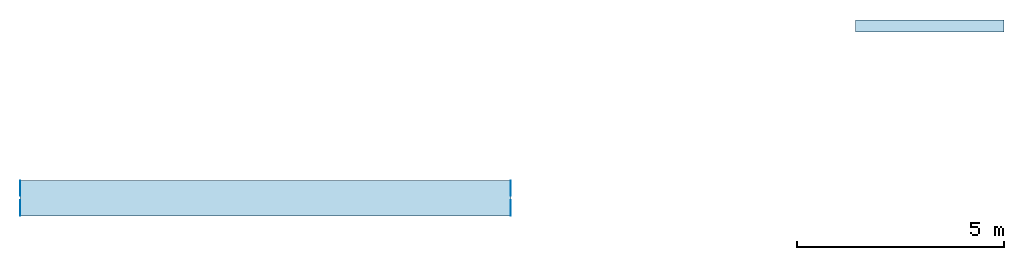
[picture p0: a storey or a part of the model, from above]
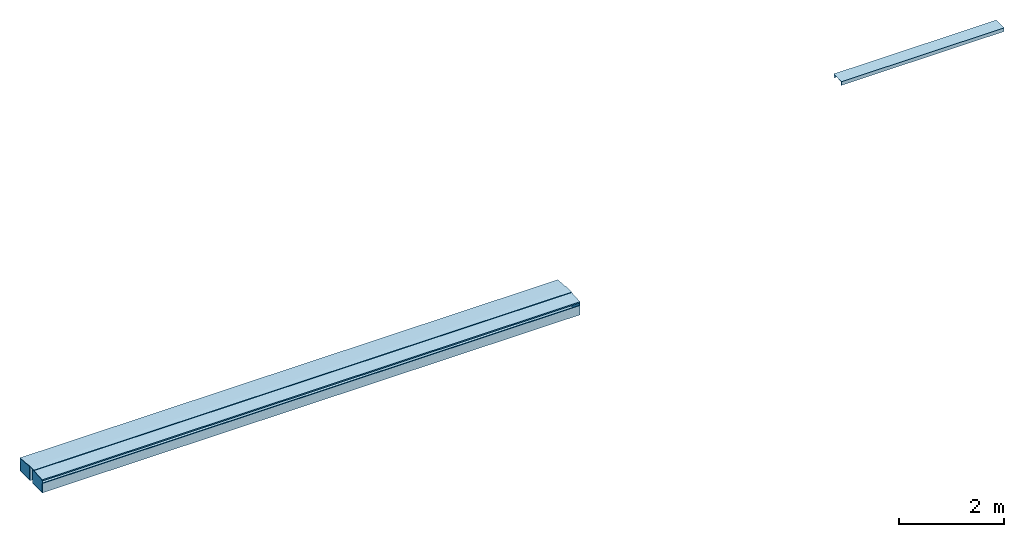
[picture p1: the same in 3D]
Properties of the parts of a building model (IFC2X3), part 1 of 5

# File
Description: ViewDefinition [CoordinationView_V2.0]
File name: ind. 00
Time: 2021-08-19T08:42:44
Written by: The EXPRESS Data Manager Version 5.02.0100.07 : 28 Aug 2013
Made in: 20180216_1515(x64) - Exporter 19.0.0.405 - Interface utilisateur alternative 19.0.0.405
Comment: STEP Physical File produced by: The EXPRESS Data Manager Version 5.02.0100.07 : 28 Aug 2013 * Module: EDMstepFileFactory/EDMstandAlone * Creation date: Thu Aug 19 08:42:44 2021 * Host: djaffar * Database: C:\Users\djaffar\AppData\Local\Temp\{09F7AAD4-CD3B-48EF-BE17-3F017BB1FF19}\ifc * Database version: 5507 * Database creation date: Thu Aug 19 08:42:33 2021 * Schema: IFC2X3 * Model: DataRepository.ifc * Model creation date: Thu Aug 19 08:42:33 2021 * Header model: DataRepository.ifc_HeaderModel * Header model creation date: Thu Aug 19 08:42:33 2021 * EDMuser: sdai-user * EDMgroup: sdai-group * License ID and type: 5605 : Permanent license. Expiry date: * EDMstepFileFactory options: 020000

# IfcProject, ind. 00
LongName: Extension de la préfecture de Mayotte; Phase: DCE

# IfcSite, Surface:959592
RefLatitude: -12, -46, -34, -218063; RefLongitude: 45, 13, 48, 547668; RefElevation: 0 m
Autre - Catégorie: Topographie; Déblais: 0 m3; Déblais/remblais net: 0 m3; Remblais: 0 m3
Cotes - Surface: 0.0941983 m2; Surface projetée: 0.0941764 m2
Données d'identification - Sous-projet: Sous-projet 1; Variantes: Terrain : projet
Matériaux et finitions - Matériau: AA-Herbe
Phase de construction - Phase de création: Nouvelle construction

# IfcBuilding, ExPREF
LongName: ExPREF
Pset_BuildingCommon - NumberOfStoreys: 6
Autre - Adresse du projet: BP 676 - Kawéni, Mamoudzou, Mayotte; Catégorie: Informations sur le projet; Date de fin du projet: Aout. 2021; Etat du projet: DCE; Nom du client: Préfecture de Mayotte; Nom du projet: Extension de la préfecture de Mayotte; Numéro de projet: ind. 00
Données d'identification - Auteur: hugo; Nom de l'organisation: Préfecture de Mayotte; Nom du bâtiment: ExPREF; Sous-projet: Infos sur le projet

# IfcBuildingStorey (6)
In: ExPREF
Autre - Catégorie: Niveaux; Famille: Niveau: Ligne du Niveau; Famille et type: Niveau: Ligne du Niveau; ID du type: Niveau: Ligne du Niveau; Type: Niveau: Ligne du Niveau
Cotes - Hauteur de calcul: 0 m
Données d'identification - Structure: no; Etage de bâtiment: yes; Sous-projet: Niveaux et quadrillages partagés
Autre(Type) - Catégorie: Niveaux; Nom de la famille: Niveau
Contraintes(Type) - Base de l'élévation: Point de base du projet
Données d'identification(Type) - Nom du type: Ligne du Niveau; Sous-projet: Types de niveaux
Graphismes(Type) - Couleur: 0; Epaisseur des lignes: 1; Motif des lignes: Plein; Symbole: Marqueur de niveau élévation 200ieme: Marqueur de niveau élévation 200ieme; Valeur par défaut du symbole à l'extrémité 1: no; Valeur par défaut du symbole à l'extrémité 2: yes
Name | LongName = Nom | Elevation (m) | Elévation (m)
R-1 | R-1 | -4.62 | -4.62 | Données d'identification - Variantes: Modèle de base
RDC | RDC | -6.89719e-12 | 0 | Données d'identification - Variantes: Modèle de base
R+1 | R+1 | 4.27 | 4.27 | Données d'identification - Variantes: Modèle de base
R+2 | R+2 | 7.83 | 7.83
Toiture | Toiture | 11.05 | 11.05
Couverture | Couverture | 13 | 13

# IfcBeam: Poutre - Bois de construction de dimensions courantes:A-24x10 cm (8)
In: R+2
Type - PredefinedType: BEAM
Type - Autre - Catégorie: Ossature; Nom de la famille: Poutre - Bois de construction de dimensions courantes
Type - Cotes - b: 0.24 m; d: 0.1 m
Type - Données d'identification - Nom du type: A-24x10 cm; Sous-projet: Famille : Ossature : Poutre - Bois de construction de dimensions courantes
Type - Structure - A: 0.002419 m2; Forme de coupe: 0
Material: AA-bois poutres
Pset_BeamCommon - LoadBearing: yes; IsExternal: no; Slope: 0 deg; Reference: Poutre - Bois de construction de dimensions courantes:A-24x10 cm
Autre - Famille: Poutre - Bois de construction de dimensions courantes: A-24x10 cm; Famille et type: Poutre - Bois de construction de dimensions courantes: A-24x10 cm; ID du type: Poutre - Bois de construction de dimensions courantes: A-24x10 cm; Type: Poutre - Bois de construction de dimensions courantes: A-24x10 cm
Contraintes - Décalage du niveau d'arrivée: 0.1 m; Décalage du niveau de départ: 0.1 m; Elévation du niveau de référence: 7.83 m; Niveau de référence: Niveau: R+2; Rotation de la section: 0 deg
Cotes - Elévation à la base: 7.83 m; Elévation en haut: 7.93 m; Volume: 0.0168 m3
Données d'identification - Sous-projet: BTC
Matériaux et finitions - Matériau structurel: AA-bois poutres
Phase de construction - Phase de création: Nouvelle construction
Position géométrique - Etat de la jonction: Deux jonctions activées; Extension de départ: 0.00268381 m; Extension de fin: -0.021 m; Justification Y: Origine; Justification YZ: Uniforme; Justification Z: Haut; Valeur de décalage Y: 0 m; Valeur de décalage Z: 0 m
Structure - Activer le modèle analytique: yes; Emplacement du symbole filaire: Centre de la géométrie; Longueur de coupe: 0.7 m; Type d'attachement de début: Elévation d'arrivée; Type d'attachement de fin: Elévation d'arrivée; Utilisation structurelle: Autre
Name (Poutre - Bois de construction de dimensions courantes:A-24x10 cm:...) | Longueur (m) | Réduction du joint de début (m) | Réduction du joint d'extrémité (m) | Group
2029215 | 0.679 | 0.000505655 | 0.000494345 | Groupe de modèles:mur BTC R+2:2029197
2029217 | 0.697 | 0 | -0.001 | Groupe de modèles:mur BTC R+2:2029197 | Données d'identification - Variantes: Modèle de base
2029649 | 0.679 | 0.000505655 | 0.000494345 | Groupe de modèles:mur BTC R+2:2029648
2029651 | 0.697 | 0 | -0.001 | Groupe de modèles:mur BTC R+2:2029648
2029723 | 0.679 | 0.000505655 | 0.000494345 | Groupe de modèles:mur BTC R+2:2029722
2029725 | 0.697 | 0 | -0.001 | Groupe de modèles:mur BTC R+2:2029722
2029801 | 0.679 | 0.000505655 | 0.000494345 | Groupe de modèles:mur BTC R+2:2029800 | Données d'identification - Variantes: Modèle de base
2029803 | 0.697 | 0 | -0.001 | Groupe de modèles:mur BTC R+2:2029800 | Données d'identification - Variantes: Modèle de base

# IfcBuildingElementProxy: R+2 naco + fenetre (3)
In: R+1
Type - Material: AA-Aluminium, AA-vitrage, AA-bois menuiseries
Type - Autre - Catégorie: Modèles génériques; Nom de la famille: R+1 naco + fenetre
Type - Cotes - hauteur: 3.81 m
Type - Données d'identification - Nom du type: R+2 naco + fenetre; Sous-projet: Famille : Modèles génériques : R+1 naco + fenetre
Type - Matériaux et finitions - matériau: AA-bois menuiseries; VITRAGE: AA-vitrage
Pset_BuildingElementProxyCommon - Reference: R+1 naco + fenetre:R+2 naco + fenetre
Autre - Famille: R+1 naco + fenetre: R+2 naco + fenetre; Famille et type: R+1 naco + fenetre: R+2 naco + fenetre; ID du type: R+1 naco + fenetre: R+2 naco + fenetre; Type: R+1 naco + fenetre: R+2 naco + fenetre
Contraintes - Niveau: Niveau: R+1; Décalage: 0 m; Se déplace avec les éléments voisins: no; Hôte: Niveau : R+1
Cotes - Surface: 9.87923 m2; Volume: 0.297217 m3
Données d'identification - Sous-projet: Menuiseries EXT
Phase de construction - Phase de création: Nouvelle construction
Name (R+1 naco + fenetre:R+2 naco + fenetre:...)
1082547 | Données d'identification - Variantes: Modèle de base
1082558
1082559

# IfcBuildingElementProxy: R+2 naco + naco (4)
In: R+2
Type - Material: AA-Aluminium, AA-vitrage, AA-bois menuiseries
Type - Autre - Catégorie: Modèles génériques; Nom de la famille: R+2 naco + naco
Type - Cotes - hauteur 2: 2.94 m
Type - Données d'identification - Nom du type: R+2 naco + naco; Sous-projet: Famille : Modèles génériques : R+2 naco + naco
Type - Matériaux et finitions - matériau: AA-bois menuiseries; VITRAGE: AA-vitrage
Pset_BuildingElementProxyCommon - Reference: R+2 naco + naco:R+2 naco + naco
Autre - Famille: R+2 naco + naco: R+2 naco + naco; Famille et type: R+2 naco + naco: R+2 naco + naco; ID du type: R+2 naco + naco: R+2 naco + naco; Type: R+2 naco + naco: R+2 naco + naco
Contraintes - Niveau: Niveau: R+2; Décalage: 0 m; Se déplace avec les éléments voisins: no; Hôte: Niveau : R+2
Cotes - Surface: 9.59008 m2; Volume: 0.274164 m3
Données d'identification - Sous-projet: Menuiseries EXT
Phase de construction - Phase de création: Nouvelle construction
Name (R+2 naco + naco:R+2 naco + naco:...) | Variantes
689299 | Modèle de base
690346
691358 | Modèle de base
1266362 | Modèle de base

# IfcBuildingElementProxy: R+2 porte + fenetre (18)
In: R+1
Type - Material: AA-Aluminium, AA-vitrage, AA-bois menuiseries
Type - Autre - Catégorie: Modèles génériques; Nom de la famille: R+1 porte + fenetre
Type - Cotes - hauteur: 3.81 m
Type - Données d'identification - Nom du type: R+2 porte + fenetre; Sous-projet: Famille : Modèles génériques : R+1 porte + fenetre
Type - Matériaux et finitions - matériau: AA-bois menuiseries; VITRAGE: AA-vitrage
Pset_BuildingElementProxyCommon - Reference: R+1 porte + fenetre:R+2 porte + fenetre
Autre - Famille: R+1 porte + fenetre: R+2 porte + fenetre; Famille et type: R+1 porte + fenetre: R+2 porte + fenetre; ID du type: R+1 porte + fenetre: R+2 porte + fenetre; Type: R+1 porte + fenetre: R+2 porte + fenetre
Contraintes - Niveau: Niveau: R+1; Décalage: 0 m; Se déplace avec les éléments voisins: no
Cotes - Surface: 9.82578 m2; Volume: 0.313711 m3
Données d'identification - Sous-projet: Menuiseries EXT
Phase de construction - Phase de création: Nouvelle construction
Name (R+1 porte + fenetre:R+2 porte + fenetre:...) | Hôte | Variantes
684139 | Niveau : R+1 | Modèle de base
686462 | Sol : A-sol souple
687418 | Niveau : R+1 | Modèle de base
687426 | Niveau : R+1 | Modèle de base
687459 | Sol : A-sol souple | Modèle de base
687583 | Niveau : R+1 | Modèle de base
687584 | Niveau : R+1
687585 | Niveau : R+1
687586 | Niveau : R+1
687587 | Sol : A-sol souple | Modèle de base
687623 | Sol : A-sol souple
687642 | Niveau : R+1
687659 | Niveau : R+1 | Modèle de base
687676 | Niveau : R+1 | Modèle de base
687716 | Sol : A-sol souple | Modèle de base
687720 | Niveau : R+1 | Modèle de base
687724 | Niveau : R+1 | Modèle de base
687728 | Niveau : R+1 | Modèle de base

# IfcBuildingElementProxy: R+2 porte + fenetre (5)
In: R+2
Type - Material: AA-Aluminium, AA-vitrage, AA-bois menuiseries
Type - Autre - Catégorie: Modèles génériques; Nom de la famille: R+2 porte + fenetre
Type - Cotes - hauteur: 3.81 m; hauteur 2: 2.94 m
Type - Données d'identification - Nom du type: R+2 porte + fenetre; Sous-projet: Famille : Modèles génériques : R+2 porte + fenetre
Type - Matériaux et finitions - matériau: AA-bois menuiseries; VITRAGE: AA-vitrage
Pset_BuildingElementProxyCommon - Reference: R+2 porte + fenetre:R+2 porte + fenetre
Autre - Famille: R+2 porte + fenetre: R+2 porte + fenetre; Famille et type: R+2 porte + fenetre: R+2 porte + fenetre; ID du type: R+2 porte + fenetre: R+2 porte + fenetre; Type: R+2 porte + fenetre: R+2 porte + fenetre
Contraintes - Niveau: Niveau: R+2; Décalage: 0 m; Se déplace avec les éléments voisins: no
Cotes - Surface: 9.43234 m2; Volume: 0.308301 m3
Données d'identification - Sous-projet: Menuiseries EXT
Phase de construction - Phase de création: Nouvelle construction
Name (R+2 porte + fenetre:R+2 porte + fenetre:...) | Hôte | Variantes
689121 | Niveau : R+2 | Modèle de base
689284 | Sol : A-sol souple | Modèle de base
691381 | Niveau : R+2 | Modèle de base
691417 | Niveau : R+2
691418 | Sol : A-sol souple | Modèle de base

# IfcBuildingElementProxy: R+2 porte + fenetre préfet, R+2 porte + fenetre préfet:R+2 porte + fenetre préfet:1084761
In: R+2
Type - Material: AA-vitrage, AA-bois menuiseries
Type - Autre - Catégorie: Modèles génériques; Nom de la famille: R+2 porte + fenetre préfet
Type - Cotes - hauteur: 3.81 m
Type - Données d'identification - Nom du type: R+2 porte + fenetre préfet; Sous-projet: Famille : Modèles génériques : R+2 porte + fenetre préfet
Type - Matériaux et finitions - matériau: AA-bois menuiseries; VITRAGE: AA-vitrage
Pset_BuildingElementProxyCommon - Reference: R+2 porte + fenetre préfet:R+2 porte + fenetre préfet
Autre - Famille: R+2 porte + fenetre préfet: R+2 porte + fenetre préfet; Famille et type: R+2 porte + fenetre préfet: R+2 porte + fenetre préfet; ID du type: R+2 porte + fenetre préfet: R+2 porte + fenetre préfet; Type: R+2 porte + fenetre préfet: R+2 porte + fenetre préfet
Contraintes - Niveau: Niveau: R+2; Décalage: 0 m; Se déplace avec les éléments voisins: no; Hôte: Niveau : R+2
Cotes - Surface: 8.72555 m2; Volume: 0.419537 m3
Données d'identification - Sous-projet: Menuiseries EXT
Phase de construction - Phase de création: Nouvelle construction

# IfcBuildingElementProxy: R+2 porte + fenetre préfet symétrie, R+2 porte + fenetre préfet symétrie:R+2 porte + fenetre préfet symétrie:1084723
In: R+2
Type - Material: AA-vitrage, AA-bois menuiseries
Type - Autre - Catégorie: Modèles génériques; Nom de la famille: R+2 porte + fenetre préfet symétrie
Type - Cotes - hauteur: 3.81 m
Type - Données d'identification - Nom du type: R+2 porte + fenetre préfet symétrie; Sous-projet: Famille : Modèles génériques : R+2 porte + fenetre préfet symétrie
Type - Matériaux et finitions - matériau: AA-bois menuiseries; VITRAGE: AA-vitrage
Pset_BuildingElementProxyCommon - Reference: R+2 porte + fenetre préfet symétrie:R+2 porte + fenetre préfet symétrie
Autre - Famille: R+2 porte + fenetre préfet symétrie: R+2 porte + fenetre préfet symétrie; Famille et type: R+2 porte + fenetre préfet symétrie: R+2 porte + fenetre préfet symétrie; ID du type: R+2 porte + fenetre préfet symétrie: R+2 porte + fenetre préfet symétrie; Type: R+2 porte + fenetre préfet symétrie: R+2 porte + fenetre préfet symétrie
Contraintes - Niveau: Niveau: R+2; Décalage: 0 m; Se déplace avec les éléments voisins: no; Hôte: Niveau : R+2
Cotes - Surface: 8.72555 m2; Volume: 0.419537 m3
Données d'identification - Sous-projet: Menuiseries EXT
Phase de construction - Phase de création: Nouvelle construction

# IfcBuildingElementProxy: R+2 porte + naco, R+1 porte + naco:R+2 porte + naco:687502
In: R+1
Type - Material: AA-Aluminium, AA-vitrage, AA-bois menuiseries
Type - Autre - Catégorie: Modèles génériques; Nom de la famille: R+1 porte + naco
Type - Cotes - hauteur: 3.81 m
Type - Données d'identification - Nom du type: R+2 porte + naco; Sous-projet: Famille : Modèles génériques : R+1 porte + naco
Type - Matériaux et finitions - matériau: AA-bois menuiseries; VITRAGE: AA-vitrage
Pset_BuildingElementProxyCommon - Reference: R+1 porte + naco:R+2 porte + naco
Autre - Famille: R+1 porte + naco: R+2 porte + naco; Famille et type: R+1 porte + naco: R+2 porte + naco; ID du type: R+1 porte + naco: R+2 porte + naco; Type: R+1 porte + naco: R+2 porte + naco
Contraintes - Niveau: Niveau: R+1; Décalage: 0 m; Se déplace avec les éléments voisins: no; Hôte: Niveau : R+1
Cotes - Surface: 9.93006 m2; Volume: 0.296068 m3
Données d'identification - Sous-projet: Menuiseries EXT; Variantes: Modèle de base
Phase de construction - Phase de création: Nouvelle construction

# IfcBuildingElementProxy: R+2 porte + porte préfet, R+2 porte + porte préfet:R+2 porte + porte préfet:2585432
In: R+2
Type - Material: AA-vitrage, AA-bois menuiseries
Type - Autre - Catégorie: Modèles génériques; Nom de la famille: R+2 porte + porte préfet
Type - Cotes - hauteur: 3.81 m
Type - Données d'identification - Nom du type: R+2 porte + porte préfet; Sous-projet: Famille : Modèles génériques : R+2 porte + porte préfet
Type - Matériaux et finitions - matériau: AA-bois menuiseries; VITRAGE: AA-vitrage
Pset_BuildingElementProxyCommon - Reference: R+2 porte + porte préfet:R+2 porte + porte préfet
Autre - Famille: R+2 porte + porte préfet: R+2 porte + porte préfet; Famille et type: R+2 porte + porte préfet: R+2 porte + porte préfet; ID du type: R+2 porte + porte préfet: R+2 porte + porte préfet; Type: R+2 porte + porte préfet: R+2 porte + porte préfet
Contraintes - Niveau: Niveau: R+2; Décalage: 0 m; Se déplace avec les éléments voisins: no; Hôte: Niveau : R+2
Cotes - Surface: 7.6809 m2; Volume: 0.348288 m3
Données d'identification - Sous-projet: Menuiseries EXT; Variantes: Modèle de base
Phase de construction - Phase de création: Nouvelle construction

# IfcBuildingElementProxy: R-1 fenetre, R-1 fenetre:R-1 fenetre:1587044
In: R-1
Type - Material: AA-Aluminium, AA-vitrage
Type - Autre - Catégorie: Modèles génériques; Nom de la famille: R-1 fenetre
Type - Cotes - hauteur: 3.81 m
Type - Données d'identification - Nom du type: R-1 fenetre; Sous-projet: Famille : Modèles génériques : R-1 fenetre
Type - Matériaux et finitions - matériau: AA-Aluminium; VITRAGE: AA-vitrage
Pset_BuildingElementProxyCommon - Reference: R-1 fenetre:R-1 fenetre
Autre - Famille: R-1 fenetre: R-1 fenetre; Famille et type: R-1 fenetre: R-1 fenetre; ID du type: R-1 fenetre: R-1 fenetre; Type: R-1 fenetre: R-1 fenetre
Contraintes - Décalage: 0 m; Se déplace avec les éléments voisins: no; Niveau: Niveau: R-1; Hôte: Niveau : R-1
Cotes - Surface: 4.49756 m2; Volume: 0.131276 m3
Données d'identification - Sous-projet: Menuiseries EXT; Variantes: Modèle de base
Phase de construction - Phase de création: Nouvelle construction

# IfcBuildingElementProxy: R-1 porte + fenetre (4)
In: R-1
Type - Material: AA-Aluminium, AA-vitrage
Type - Autre - Catégorie: Modèles génériques; Nom de la famille: R-1 porte + fenetre
Type - Cotes - hauteur: 3.81 m
Type - Données d'identification - Nom du type: R-1 porte + fenetre; Sous-projet: Famille : Modèles génériques : R-1 porte + fenetre
Type - Matériaux et finitions - matériau: AA-Aluminium; VITRAGE: AA-vitrage
Pset_BuildingElementProxyCommon - Reference: R-1 porte + fenetre:R-1 porte + fenetre
Autre - Famille: R-1 porte + fenetre: R-1 porte + fenetre; Famille et type: R-1 porte + fenetre: R-1 porte + fenetre; ID du type: R-1 porte + fenetre: R-1 porte + fenetre; Type: R-1 porte + fenetre: R-1 porte + fenetre
Contraintes - Décalage: 0 m; Se déplace avec les éléments voisins: no; Niveau: Niveau: R-1
Cotes - Surface: 10.6055 m2; Volume: 0.324278 m3
Données d'identification - Sous-projet: Menuiseries EXT
Phase de construction - Phase de création: Nouvelle construction
Name (R-1 porte + fenetre:R-1 porte + fenetre:...) | Hôte
1079695 | Niveau : R-1 | Données d'identification - Variantes: Modèle de base
1079696 | Niveau : R-1
1079697 | Sol : A-dalle béton 13 cm
1079698 | Sol : A-dalle béton 13 cm | Données d'identification - Variantes: Modèle de base

# IfcBuildingElementProxy: RDC fenetre + fenetre (3)
In: RDC
Type - Material: AA-Aluminium, AA-vitrage, AA-bois menuiseries
Type - Autre - Catégorie: Modèles génériques; Nom de la famille: RDC fenetre + fenetre
Type - Cotes - hauteur: 3.81 m
Type - Données d'identification - Nom du type: RDC fenetre + fenetre; Sous-projet: Famille : Modèles génériques : RDC fenetre + fenetre
Type - Matériaux et finitions - matériau: AA-bois menuiseries; VITRAGE: AA-vitrage
Pset_BuildingElementProxyCommon - Reference: RDC fenetre + fenetre:RDC fenetre + fenetre
Autre - Famille: RDC fenetre + fenetre: RDC fenetre + fenetre; Famille et type: RDC fenetre + fenetre: RDC fenetre + fenetre; ID du type: RDC fenetre + fenetre: RDC fenetre + fenetre; Type: RDC fenetre + fenetre: RDC fenetre + fenetre
Contraintes - Niveau: Niveau: RDC; Décalage: 0 m; Se déplace avec les éléments voisins: no; Hôte: Niveau : RDC
Cotes - Surface: 11.7825 m2; Volume: 0.321997 m3
Données d'identification - Sous-projet: Menuiseries EXT; Variantes: Modèle de base
Phase de construction - Phase de création: Nouvelle construction
Name (RDC fenetre + fenetre:RDC fenetre + fenetre:...)
698890
1082484
1082492

# IfcBuildingElementProxy: RDC naco + naco (11)
In: RDC
Type - Material: AA-bois menuiseries, AA-vitrage
Type - Autre - Catégorie: Modèles génériques; Nom de la famille: RDC naco + naco
Type - Cotes - hauteur: 3.81 m
Type - Données d'identification - Nom du type: RDC naco + naco; Sous-projet: Famille : Modèles génériques : RDC naco + naco
Type - Matériaux et finitions - matériau: AA-bois menuiseries; VITRAGE: AA-vitrage
Pset_BuildingElementProxyCommon - Reference: RDC naco + naco:RDC naco + naco
Autre - Famille: RDC naco + naco: RDC naco + naco; Famille et type: RDC naco + naco: RDC naco + naco; ID du type: RDC naco + naco: RDC naco + naco; Type: RDC naco + naco: RDC naco + naco
Contraintes - Niveau: Niveau: RDC; Décalage: 0 m; Se déplace avec les éléments voisins: no
Cotes - Surface: 11.9298 m2; Volume: 0.318379 m3
Données d'identification - Sous-projet: Menuiseries EXT
Phase de construction - Phase de création: Nouvelle construction
Name (RDC naco + naco:RDC naco + naco:...) | Hôte | Variantes
645344 | Sol : A-dalle béton ext 27.5 cm | Modèle de base
645476 | Sol : A-dalle béton ext 27.5 cm | Modèle de base
645512 | Sol : A-dalle béton ext 27.5 cm
647160 | Niveau : RDC | Modèle de base
680898 | Niveau : RDC | Modèle de base
680917 | Niveau : RDC | Modèle de base
680996 | Niveau : RDC
680997 | Niveau : RDC
681126 | Sol : A-dalle béton ext 27.5 cm
681127 | Sol : A-dalle béton ext 27.5 cm
681128 | Sol : A-dalle béton ext 27.5 cm | Modèle de base

# IfcBuildingElementProxy: RDC porte + fenetre (4)
In: RDC
Type - Material: AA-Aluminium, AA-vitrage, AA-bois menuiseries
Type - Autre - Catégorie: Modèles génériques; Nom de la famille: RDC porte + fenetre
Type - Cotes - hauteur: 3.81 m
Type - Données d'identification - Nom du type: RDC porte + fenetre; Sous-projet: Famille : Modèles génériques : RDC porte + fenetre
Type - Matériaux et finitions - matériau: AA-bois menuiseries; VITRAGE: AA-vitrage
Type - Texte - type porte: ME-pf
Pset_BuildingElementProxyCommon - Reference: RDC porte + fenetre:RDC porte + fenetre
Autre - Famille: RDC porte + fenetre: RDC porte + fenetre; Famille et type: RDC porte + fenetre: RDC porte + fenetre; ID du type: RDC porte + fenetre: RDC porte + fenetre; Type: RDC porte + fenetre: RDC porte + fenetre
Contraintes - Niveau: Niveau: RDC; Décalage: 0 m; Se déplace avec les éléments voisins: no
Cotes - Surface: 11.729 m2; Volume: 0.338491 m3
Données d'identification - Sous-projet: Menuiseries EXT
Phase de construction - Phase de création: Nouvelle construction
Name (RDC porte + fenetre:RDC porte + fenetre:...) | Hôte
642411 | Sol : A-dalle béton ext 27.5 cm
680965 | Niveau : RDC
680998 | Niveau : RDC | Données d'identification - Variantes: Modèle de base
681076 | Niveau : RDC

# IfcBuildingElementProxy: RDC porte + naco, RDC porte + naco:RDC porte + naco:681059
In: RDC
Type - Material: AA-Aluminium, AA-vitrage, AA-bois menuiseries
Type - Autre - Catégorie: Modèles génériques; Nom de la famille: RDC porte + naco
Type - Cotes - hauteur: 3.81 m
Type - Données d'identification - Nom du type: RDC porte + naco; Sous-projet: Famille : Modèles génériques : RDC porte + naco
Type - Matériaux et finitions - matériau: AA-bois menuiseries; VITRAGE: AA-vitrage
Pset_BuildingElementProxyCommon - Reference: RDC porte + naco:RDC porte + naco
Autre - Famille: RDC porte + naco: RDC porte + naco; Famille et type: RDC porte + naco: RDC porte + naco; ID du type: RDC porte + naco: RDC porte + naco; Type: RDC porte + naco: RDC porte + naco
Contraintes - Niveau: Niveau: RDC; Décalage: 0 m; Se déplace avec les éléments voisins: no; Hôte: Niveau : RDC
Cotes - Surface: 11.8539 m2; Volume: 0.327373 m3
Données d'identification - Sous-projet: Menuiseries EXT; Variantes: Modèle de base
Phase de construction - Phase de création: Nouvelle construction

# IfcBuildingElementProxy: RDC porte + naco symétrie (3)
In: RDC
Type - Material: AA-Aluminium, AA-vitrage, AA-bois menuiseries
Type - Autre - Catégorie: Modèles génériques; Nom de la famille: RDC porte + naco symétrie
Type - Cotes - hauteur: 3.81 m
Type - Données d'identification - Nom du type: RDC porte + naco symétrie; Sous-projet: Famille : Modèles génériques : RDC porte + naco symétrie
Type - Matériaux et finitions - matériau: AA-bois menuiseries; VITRAGE: AA-vitrage
Pset_BuildingElementProxyCommon - Reference: RDC porte + naco symétrie:RDC porte + naco symétrie
Autre - Famille: RDC porte + naco symétrie: RDC porte + naco symétrie; Famille et type: RDC porte + naco symétrie: RDC porte + naco symétrie; ID du type: RDC porte + naco symétrie: RDC porte + naco symétrie; Type: RDC porte + naco symétrie: RDC porte + naco symétrie
Contraintes - Niveau: Niveau: RDC; Se déplace avec les éléments voisins: no
Cotes - Surface: 11.8539 m2; Volume: 0.327373 m3
Données d'identification - Sous-projet: Menuiseries EXT
Phase de construction - Phase de création: Nouvelle construction
Name (RDC porte + naco symétrie:RDC porte + naco symétrie:...) | Décalage (m) | Hôte | Variantes
681024 | 0 | Niveau : RDC | Modèle de base
1340747 | 0.01 | Sol : A-isolant 4.5 cm
2572841 | 0 | Sol : A-sol souple | Modèle de base

# IfcColumn: HEA160 (8)
In: R+2
Type - ElementType: HEA160; PredefinedType: COLUMN
Type - Analyse structurelle - Aire sectionnelle: 0.00388 m2; Module d'élasticité - axe faible: 0.0000769 m3; Module d'élasticité - axe fort: 0.00022 m3; Module plastique - axe faible: 0.0001176 m3; Module plastique - axe fort: 0.0002451 m3; Moment d'inertie - axe faible: 0.000713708; Moment d'inertie - axe fort: 0.00193489; Moment d'inertie de torsion: 0; Périmètre: 0.276149 m2; Poids nominal: 298.121; Rayon d'inertie sectoriel: 0
Type - Autre - Catégorie: Poteaux porteurs; Nom de la famille: potelet bois
Type - Cotes - Espacement du boulon: 0.099 m
Type - Données d'identification - Identifiant du nom de la coupe: HEA160; Nom de code: EURONORM 53-62; DIN 1025-3; NF A 45-201; Nom du type: HEA160; Sous-projet: Famille : Poteaux porteurs : potelet bois
Type - Géométrie de coupe structurelle - Centre de gravité horizontal: 0.08 m; Centre de gravité vertical: 0.076 m; Congé de l'âme: 0.015 m; Epaisseur de l'aile: 0.009 m; Epaisseur de l'âme: 0.012 m; Hauteur: 0.152 m; Largeur: 0.16 m
Type - Structure - Forme de coupe: 8
Material: AA-bois poutres
Pset_ColumnCommon - LoadBearing: yes; IsExternal: no; Reference: potelet bois:HEA160
Autre - Famille: potelet bois: HEA160; Famille et type: potelet bois: HEA160; ID du type: potelet bois: HEA160; Type: potelet bois: HEA160
Contraintes - Niveau: Niveau: R+2; Décalage inférieur: 0 m; Décalage supérieur: -0.28 m; Niveau de base: Niveau: R+2; Niveau supérieur: Niveau: Toiture; Se déplace avec les quadrillages: yes; Style de poteau: Vertical
Cotes - Longueur: 2.94 m; Surface: 1.1484 m2; Volume: 0.091728 m3
Données d'identification - Sous-projet: BTC
Matériaux et finitions - Matériau structurel: AA-bois poutres
Phase de construction - Phase de création: Nouvelle construction
Structure - Activer le modèle analytique: yes
Name (potelet bois:HEA160:...) | Marque d'emplacement du poteau | Group
1349774 | G(0.97)-4 | Groupe de modèles:mur BTC R+2:2029197 | Pset_ColumnCommon - Slope: 0 deg
1349776 | H(-0.97)-4 | Groupe de modèles:mur BTC R+2:2029197 | Pset_ColumnCommon - Slope: 0 deg; Données d'identification - Variantes: Modèle de base
2029644 | H(0.97)-4 | Groupe de modèles:mur BTC R+2:2029648
2029646 | I(-0.97)-4 | Groupe de modèles:mur BTC R+2:2029648 | Données d'identification - Variantes: Modèle de base
2029718 | I(0.97)-4 | Groupe de modèles:mur BTC R+2:2029722
2029720 | J(-0.97)-4 | Groupe de modèles:mur BTC R+2:2029722 | Données d'identification - Variantes: Modèle de base
2029796 | J(0.97)-4 | Groupe de modèles:mur BTC R+2:2029800 | Données d'identification - Variantes: Modèle de base
2029798 | K(-0.97)-4 | Groupe de modèles:mur BTC R+2:2029800

# IfcColumn: HEA160 (395)
Type - ElementType: HEA160; PredefinedType: COLUMN
Type - Analyse structurelle - Moment d'inertie de torsion: 0; Rayon d'inertie sectoriel: 0; Aire sectionnelle: 0.00388 m2; Module d'élasticité - axe faible: 0.0000769 m3; Module d'élasticité - axe fort: 0.00022 m3; Module plastique - axe faible: 0.0001176 m3; Module plastique - axe fort: 0.0002451 m3; Moment d'inertie - axe faible: 0.000713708; Moment d'inertie - axe fort: 0.00193489; Périmètre: 0.276149 m2; Poids nominal: 298.121
Type - Autre - Catégorie: Poteaux porteurs; Nom de la famille: poteau bois 8x4.5 cm
Type - Cotes - Espacement du boulon: 0.099 m
Type - Données d'identification - Identifiant du nom de la coupe: HEA160; Nom de code: EURONORM 53-62; DIN 1025-3; NF A 45-201; Nom du type: HEA160; Sous-projet: Famille : Poteaux porteurs : poteau bois 8x4.5 cm
Type - Géométrie de coupe structurelle - Centre de gravité horizontal: 0.0225 m; Centre de gravité vertical: 0.04 m; Congé de l'âme: 0.015 m; Epaisseur de l'aile: 0.009 m; Epaisseur de l'âme: 0.006 m; Hauteur: 0.08 m; Largeur: 0.045 m
Type - Structure - Forme de coupe: 8
Pset_ColumnCommon - LoadBearing: yes; IsExternal: no; Reference: poteau bois 8x4.5 cm:HEA160
Autre - Famille: poteau bois 8x4.5 cm: HEA160; Famille et type: poteau bois 8x4.5 cm: HEA160; ID du type: poteau bois 8x4.5 cm: HEA160; Type: poteau bois 8x4.5 cm: HEA160
Contraintes - Se déplace avec les quadrillages: yes; Style de poteau: Vertical
Données d'identification - Sous-projet: Cloisons
Phase de construction - Phase de création: Nouvelle construction
Structure - Activer le modèle analytique: yes
Name (poteau bois 8x4.5 cm:HEA160:...) | In | Material = Matériau structurel | Niveau = Niveau de base | Décalage inférieur (m) | Décalage supérieur (m) | Marque d'emplacement du poteau | Niveau supérieur | Longueur (m) | Surface (m2) | Volume (m3) | Group
1442329 | RDC | AA-bois poutres | Niveau: RDC | -0.055 | -0.94 | E(-0.57)-3 | Niveau: R+1 | 3.385 | 0.426725 | 0.012186 | Groupe de modèles:POTEAUX CLOISONS RDC (membre exclu):1442762 | Pset_ColumnCommon - Slope: 0 deg
2027374 | RDC | AA-bois poutres | Niveau: RDC | -0.055 | -0.94 | E(-0.57)-3(0.50) | Niveau: R+1 | 3.385 | 0.426725 | 0.012186 | Groupe de modèles:POTEAUX CLOISONS RDC (membre exclu):1442762
2027427 | RDC | AA-bois poutres | Niveau: RDC | -0.055 | -0.94 | E(-0.57)-3(1.00) | Niveau: R+1 | 3.385 | 0.426725 | 0.012186 | Groupe de modèles:POTEAUX CLOISONS RDC (membre exclu):1442762
2027444 | RDC | AA-bois poutres | Niveau: RDC | -0.055 | -0.94 | E(-0.57)-3(1.38) | Niveau: R+1 | 3.385 | 0.426725 | 0.012186 | Groupe de modèles:POTEAUX CLOISONS RDC (membre exclu):1442762
2027509 | RDC | AA-bois poutres | Niveau: RDC | -0.055 | -0.94 | E(0.09)-3(1.44) | Niveau: R+1 | 3.385 | 0.426725 | 0.012186 | Groupe de modèles:POTEAUX CLOISONS RDC (membre exclu):1442762 | Données d'identification - Variantes: Modèle de base
2027569 | RDC | AA-bois poutres | Niveau: RDC | -0.055 | -0.94 | E(-0.51)-3(1.44) | Niveau: R+1 | 3.385 | 0.426725 | 0.012186 | Groupe de modèles:POTEAUX CLOISONS RDC (membre exclu):1442762
2027595 | RDC | AA-bois poutres | Niveau: RDC | -0.055 | -0.94 | E(-0.57)-3(-0.50) | Niveau: R+1 | 3.385 | 0.426725 | 0.012186 | Groupe de modèles:POTEAUX CLOISONS RDC (membre exclu):1442762 | Pset_ColumnCommon - Slope: 0 deg
2027597 | RDC | AA-bois poutres | Niveau: RDC | -0.055 | -0.94 | E(-0.57)-3(-1.00) | Niveau: R+1 | 3.385 | 0.426725 | 0.012186 | Groupe de modèles:POTEAUX CLOISONS RDC (membre exclu):1442762 | Données d'identification - Variantes: Modèle de base
2027599 | RDC | AA-bois poutres | Niveau: RDC | -0.055 | -0.94 | E(-0.57)-3(-1.38) | Niveau: R+1 | 3.385 | 0.426725 | 0.012186 | Groupe de modèles:POTEAUX CLOISONS RDC (membre exclu):1442762 | Données d'identification - Variantes: Modèle de base
2027601 | RDC | AA-bois poutres | Niveau: RDC | -0.055 | -0.94 | E(0.09)-3(-1.44) | Niveau: R+1 | 3.385 | 0.426725 | 0.012186 | Groupe de modèles:POTEAUX CLOISONS RDC (membre exclu):1442762
2027603 | RDC | AA-bois poutres | Niveau: RDC | -0.055 | -0.94 | E(-0.51)-3(-1.44) | Niveau: R+1 | 3.385 | 0.426725 | 0.012186 | Groupe de modèles:POTEAUX CLOISONS RDC (membre exclu):1442762
2027687 | RDC | AA-bois poutres | Niveau: RDC | -0.055 | -0.94 | A(0.57)-3 | Niveau: R+1 | 3.385 | 0.426725 | 0.012186 | Groupe de modèles:POTEAUX CLOISONS RDC (membre exclu):1442762
2027689 | RDC | AA-bois poutres | Niveau: RDC | -0.055 | -0.94 | A(0.57)-3(0.50) | Niveau: R+1 | 3.385 | 0.426725 | 0.012186 | Groupe de modèles:POTEAUX CLOISONS RDC (membre exclu):1442762
2027691 | RDC | AA-bois poutres | Niveau: RDC | -0.055 | -0.94 | A(0.57)-3(1.00) | Niveau: R+1 | 3.385 | 0.426725 | 0.012186 | Groupe de modèles:POTEAUX CLOISONS RDC (membre exclu):1442762
2027693 | RDC | AA-bois poutres | Niveau: RDC | -0.055 | -0.94 | A(0.57)-3(1.38) | Niveau: R+1 | 3.385 | 0.426725 | 0.012186 | Groupe de modèles:POTEAUX CLOISONS RDC (membre exclu):1442762
2027695 | RDC | AA-bois poutres | Niveau: RDC | -0.055 | -0.94 | A(-0.05)-3(1.44) | Niveau: R+1 | 3.385 | 0.426725 | 0.012186 | Groupe de modèles:POTEAUX CLOISONS RDC (membre exclu):1442762 | Données d'identification - Variantes: Modèle de base
2027697 | RDC | AA-bois poutres | Niveau: RDC | -0.055 | -0.94 | A(0.51)-3(1.44) | Niveau: R+1 | 3.385 | 0.426725 | 0.012186 | Groupe de modèles:POTEAUX CLOISONS RDC (membre exclu):1442762 | Données d'identification - Variantes: Modèle de base
2027699 | RDC | AA-bois poutres | Niveau: RDC | -0.055 | -0.94 | A(0.57)-3(-0.50) | Niveau: R+1 | 3.385 | 0.426725 | 0.012186 | Groupe de modèles:POTEAUX CLOISONS RDC (membre exclu):1442762
2027701 | RDC | AA-bois poutres | Niveau: RDC | -0.055 | -0.94 | A(0.57)-3(-1.00) | Niveau: R+1 | 3.385 | 0.426725 | 0.012186 | Groupe de modèles:POTEAUX CLOISONS RDC (membre exclu):1442762 | Données d'identification - Variantes: Modèle de base
2027703 | RDC | AA-bois poutres | Niveau: RDC | -0.055 | -0.94 | A(0.57)-3(-1.38) | Niveau: R+1 | 3.385 | 0.426725 | 0.012186 | Groupe de modèles:POTEAUX CLOISONS RDC (membre exclu):1442762 | Données d'identification - Variantes: Modèle de base
2027705 | RDC | AA-bois poutres | Niveau: RDC | -0.055 | -0.94 | A(-0.05)-3(-1.44) | Niveau: R+1 | 3.385 | 0.426725 | 0.012186 | Groupe de modèles:POTEAUX CLOISONS RDC (membre exclu):1442762 | Données d'identification - Variantes: Modèle de base
2027707 | RDC | AA-bois poutres | Niveau: RDC | -0.055 | -0.94 | A(0.51)-3(-1.44) | Niveau: R+1 | 3.385 | 0.426725 | 0.012186 | Groupe de modèles:POTEAUX CLOISONS RDC (membre exclu):1442762 | Données d'identification - Variantes: Modèle de base
2167933 | RDC | AA-bois tasseau cloison | Niveau: RDC | -0.055 | -0.94 | G-3 | Niveau: R+1 | 3.385 | 0.426725 | 0.012186 | Groupe de modèles:POTEAUX CLOISONS RDC (membre exclu):1442762 | Pset_ColumnCommon - Slope: 0 deg
2167935 | RDC | AA-bois tasseau cloison | Niveau: RDC | -0.055 | -0.94 | G-3(0.50) | Niveau: R+1 | 3.385 | 0.426725 | 0.012186 | Groupe de modèles:POTEAUX CLOISONS RDC (membre exclu):1442762
2167937 | RDC | AA-bois tasseau cloison | Niveau: RDC | -0.055 | -0.94 | G-3(1.00) | Niveau: R+1 | 3.385 | 0.426725 | 0.012186 | Groupe de modèles:POTEAUX CLOISONS RDC (membre exclu):1442762 | Données d'identification - Variantes: Modèle de base
2167939 | RDC | AA-bois tasseau cloison | Niveau: RDC | -0.055 | -0.94 | G-3(1.50) | Niveau: R+1 | 3.385 | 0.426725 | 0.012186 | Groupe de modèles:POTEAUX CLOISONS RDC (membre exclu):1442762 | Données d'identification - Variantes: Modèle de base
2167941 | RDC | AA-bois tasseau cloison | Niveau: RDC | -0.055 | -0.94 | G-3(2.00) | Niveau: R+1 | 3.385 | 0.426725 | 0.012186 | Groupe de modèles:POTEAUX CLOISONS RDC (membre exclu):1442762
2167943 | RDC | AA-bois tasseau cloison | Niveau: RDC | -0.055 | -0.94 | G-4(-1.65) | Niveau: R+1 | 3.385 | 0.426725 | 0.012186 | Groupe de modèles:POTEAUX CLOISONS RDC (membre exclu):1442762 | Données d'identification - Variantes: Modèle de base
2167951 | RDC | AA-bois tasseau cloison | Niveau: RDC | -0.055 | -0.94 | G-3(-0.50) | Niveau: R+1 | 3.385 | 0.426725 | 0.012186 | Groupe de modèles:POTEAUX CLOISONS RDC (membre exclu):1442762 | Pset_ColumnCommon - Slope: 0 deg; Données d'identification - Variantes: Modèle de base
2168451 | RDC | AA-bois tasseau cloison | Niveau: RDC | -0.055 | -0.94 | G(-1.52)-4(-2.01) | Niveau: R+1 | 3.385 | 0.426725 | 0.012186 | Groupe de modèles:POTEAUX CLOISONS RDC (membre exclu):1442762 | Données d'identification - Variantes: Modèle de base
2168480 | RDC | AA-bois tasseau cloison | Niveau: RDC | -0.055 | -0.94 | G(-1.08)-4(-2.01) | Niveau: R+1 | 3.385 | 0.426725 | 0.012186 | Groupe de modèles:POTEAUX CLOISONS RDC (membre exclu):1442762 | Données d'identification - Variantes: Modèle de base
2168510 | RDC | AA-bois tasseau cloison | Niveau: RDC | -0.055 | -0.94 | G-4(-0.14) | Niveau: R+1 | 3.385 | 0.426725 | 0.012186 | Groupe de modèles:POTEAUX CLOISONS RDC (membre exclu):1442762 | Données d'identification - Variantes: Modèle de base
2168512 | RDC | AA-bois tasseau cloison | Niveau: RDC | -0.055 | -0.94 | G-4(-1.37) | Niveau: R+1 | 3.385 | 0.426725 | 0.012186 | Groupe de modèles:POTEAUX CLOISONS RDC (membre exclu):1442762 | Données d'identification - Variantes: Modèle de base
2168514 | RDC | AA-bois tasseau cloison | Niveau: RDC | -0.055 | -0.94 | G-4(-0.33) | Niveau: R+1 | 3.385 | 0.426725 | 0.012186 | Groupe de modèles:POTEAUX CLOISONS RDC (membre exclu):1442762
2168553 | RDC | AA-bois tasseau cloison | Niveau: RDC | -0.055 | -0.94 | H-3 | Niveau: R+1 | 3.385 | 0.426725 | 0.012186 | Groupe de modèles:POTEAUX CLOISONS RDC (membre exclu):1442762
2168555 | RDC | AA-bois tasseau cloison | Niveau: RDC | -0.055 | -0.94 | H-3(0.50) | Niveau: R+1 | 3.385 | 0.426725 | 0.012186 | Groupe de modèles:POTEAUX CLOISONS RDC (membre exclu):1442762 | Données d'identification - Variantes: Modèle de base
2168557 | RDC | AA-bois tasseau cloison | Niveau: RDC | -0.055 | -0.94 | H-3(1.00) | Niveau: R+1 | 3.385 | 0.426725 | 0.012186 | Groupe de modèles:POTEAUX CLOISONS RDC (membre exclu):1442762 | Données d'identification - Variantes: Modèle de base
2168559 | RDC | AA-bois tasseau cloison | Niveau: RDC | -0.055 | -0.94 | H-3(1.50) | Niveau: R+1 | 3.385 | 0.426725 | 0.012186 | Groupe de modèles:POTEAUX CLOISONS RDC (membre exclu):1442762
2168561 | RDC | AA-bois tasseau cloison | Niveau: RDC | -0.055 | -0.94 | H-3(2.00) | Niveau: R+1 | 3.385 | 0.426725 | 0.012186 | Groupe de modèles:POTEAUX CLOISONS RDC (membre exclu):1442762 | Données d'identification - Variantes: Modèle de base
2168563 | RDC | AA-bois tasseau cloison | Niveau: RDC | -0.055 | -0.94 | H-4(-1.65) | Niveau: R+1 | 3.385 | 0.426725 | 0.012186 | Groupe de modèles:POTEAUX CLOISONS RDC (membre exclu):1442762
2168565 | RDC | AA-bois tasseau cloison | Niveau: RDC | -0.055 | -0.94 | H-2(0.14) | Niveau: R+1 | 3.385 | 0.426725 | 0.012186 | Groupe de modèles:POTEAUX CLOISONS RDC (membre exclu):1442762
2168567 | RDC | AA-bois tasseau cloison | Niveau: RDC | -0.055 | -0.94 | H-3(-0.50) | Niveau: R+1 | 3.385 | 0.426725 | 0.012186 | Groupe de modèles:POTEAUX CLOISONS RDC (membre exclu):1442762 | Données d'identification - Variantes: Modèle de base
2168569 | RDC | AA-bois tasseau cloison | Niveau: RDC | -0.055 | -0.94 | H-3(-1.00) | Niveau: R+1 | 3.385 | 0.426725 | 0.012186 | Groupe de modèles:POTEAUX CLOISONS RDC (membre exclu):1442762
2168571 | RDC | AA-bois tasseau cloison | Niveau: RDC | -0.055 | -0.94 | H-3(-1.50) | Niveau: R+1 | 3.385 | 0.426725 | 0.012186 | Groupe de modèles:POTEAUX CLOISONS RDC (membre exclu):1442762
2168573 | RDC | AA-bois tasseau cloison | Niveau: RDC | -0.055 | -0.94 | H-3(-2.00) | Niveau: R+1 | 3.385 | 0.426725 | 0.012186 | Groupe de modèles:POTEAUX CLOISONS RDC (membre exclu):1442762 | Données d'identification - Variantes: Modèle de base
2168575 | RDC | AA-bois tasseau cloison | Niveau: RDC | -0.055 | -0.94 | H-2(1.65) | Niveau: R+1 | 3.385 | 0.426725 | 0.012186 | Groupe de modèles:POTEAUX CLOISONS RDC (membre exclu):1442762
2168577 | RDC | AA-bois tasseau cloison | Niveau: RDC | -0.055 | -0.94 | H-2(1.37) | Niveau: R+1 | 3.385 | 0.426725 | 0.012186 | Groupe de modèles:POTEAUX CLOISONS RDC (membre exclu):1442762
2168579 | RDC | AA-bois tasseau cloison | Niveau: RDC | -0.055 | -0.94 | H-2(0.33) | Niveau: R+1 | 3.385 | 0.426725 | 0.012186 | Groupe de modèles:POTEAUX CLOISONS RDC (membre exclu):1442762
2168583 | RDC | AA-bois tasseau cloison | Niveau: RDC | -0.055 | -0.94 | H-4(-0.14) | Niveau: R+1 | 3.385 | 0.426725 | 0.012186 | Groupe de modèles:POTEAUX CLOISONS RDC (membre exclu):1442762 | Données d'identification - Variantes: Modèle de base
2168585 | RDC | AA-bois tasseau cloison | Niveau: RDC | -0.055 | -0.94 | H-4(-1.37) | Niveau: R+1 | 3.385 | 0.426725 | 0.012186 | Groupe de modèles:POTEAUX CLOISONS RDC (membre exclu):1442762
2168587 | RDC | AA-bois tasseau cloison | Niveau: RDC | -0.055 | -0.94 | H-4(-0.33) | Niveau: R+1 | 3.385 | 0.426725 | 0.012186 | Groupe de modèles:POTEAUX CLOISONS RDC (membre exclu):1442762
2169894 | RDC | AA-bois tasseau cloison | Niveau: RDC | -0.055 | -0.94 | G(0.60)-3(1.69) | Niveau: R+1 | 3.385 | 0.426725 | 0.012186 | Groupe de modèles:POTEAUX CLOISONS RDC (membre exclu):1442762
2169937 | RDC | AA-bois tasseau cloison | Niveau: RDC | -0.055 | -0.94 | G(0.06)-3(1.69) | Niveau: R+1 | 3.385 | 0.426725 | 0.012186 | Groupe de modèles:POTEAUX CLOISONS RDC (membre exclu):1442762
2169980 | RDC | AA-bois tasseau cloison | Niveau: RDC | -0.055 | -0.94 | G(0.66)-3(1.63) | Niveau: R+1 | 3.385 | 0.426725 | 0.012186 | Groupe de modèles:POTEAUX CLOISONS RDC (membre exclu):1442762
2170041 | RDC | AA-bois tasseau cloison | Niveau: RDC | -0.055 | -0.94 | G(0.66)-3(1.13) | Niveau: R+1 | 3.385 | 0.426725 | 0.012186 | Groupe de modèles:POTEAUX CLOISONS RDC (membre exclu):1442762
2170058 | RDC | AA-bois tasseau cloison | Niveau: RDC | -0.055 | -0.94 | G(0.66)-3(0.63) | Niveau: R+1 | 3.385 | 0.426725 | 0.012186 | Groupe de modèles:POTEAUX CLOISONS RDC (membre exclu):1442762 | Données d'identification - Variantes: Modèle de base
2170131 | RDC | AA-bois tasseau cloison | Niveau: RDC | -0.055 | -0.94 | G(0.66)-3(0.13) | Niveau: R+1 | 3.385 | 0.426725 | 0.012186 | Groupe de modèles:POTEAUX CLOISONS RDC (membre exclu):1442762 | Données d'identification - Variantes: Modèle de base
2170148 | RDC | AA-bois tasseau cloison | Niveau: RDC | -0.055 | -0.94 | G(0.66)-3(-0.37) | Niveau: R+1 | 3.385 | 0.426725 | 0.012186 | Groupe de modèles:POTEAUX CLOISONS RDC (membre exclu):1442762
2170165 | RDC | AA-bois tasseau cloison | Niveau: RDC | -0.055 | -0.94 | G(0.66)-3(-0.87) | Niveau: R+1 | 3.385 | 0.426725 | 0.012186 | Groupe de modèles:POTEAUX CLOISONS RDC (membre exclu):1442762 | Données d'identification - Variantes: Modèle de base
2170184 | RDC | AA-bois tasseau cloison | Niveau: RDC | -0.055 | -0.94 | G(0.66)-3(-1.30) | Niveau: R+1 | 3.385 | 0.426725 | 0.012186 | Groupe de modèles:POTEAUX CLOISONS RDC (membre exclu):1442762 | Données d'identification - Variantes: Modèle de base
2170223 | RDC | AA-bois tasseau cloison | Niveau: RDC | -0.055 | -0.94 | G(0.60)-3(0.77) | Niveau: R+1 | 3.385 | 0.426725 | 0.012186 | Groupe de modèles:POTEAUX CLOISONS RDC (membre exclu):1442762
2170225 | RDC | AA-bois tasseau cloison | Niveau: RDC | -0.055 | -0.94 | G(0.06)-3(0.77) | Niveau: R+1 | 3.385 | 0.426725 | 0.012186 | Groupe de modèles:POTEAUX CLOISONS RDC (membre exclu):1442762
2241453 | RDC | AA-bois tasseau cloison | Niveau: RDC | -0.055 | -0.94 | G(-0.11)-3(-1.36) | Niveau: R+1 | 3.385 | 0.426725 | 0.012186 | Groupe de modèles:POTEAUX CLOISONS RDC (membre exclu):1442762 | Données d'identification - Variantes: Modèle de base
2241455 | RDC | AA-bois tasseau cloison | Niveau: RDC | -0.055 | -0.94 | G(-0.61)-3(-1.36) | Niveau: R+1 | 3.385 | 0.426725 | 0.012186 | Groupe de modèles:POTEAUX CLOISONS RDC (membre exclu):1442762 | Données d'identification - Variantes: Modèle de base
2241457 | RDC | AA-bois tasseau cloison | Niveau: RDC | -0.055 | -0.94 | G(-1.11)-3(-1.36) | Niveau: R+1 | 3.385 | 0.426725 | 0.012186 | Groupe de modèles:POTEAUX CLOISONS RDC (membre exclu):1442762
2241459 | RDC | AA-bois tasseau cloison | Niveau: RDC | -0.055 | -0.94 | G(-1.61)-3(-1.36) | Niveau: R+1 | 3.385 | 0.426725 | 0.012186 | Groupe de modèles:POTEAUX CLOISONS RDC (membre exclu):1442762 | Données d'identification - Variantes: Modèle de base
2241508 | RDC | AA-bois tasseau cloison | Niveau: RDC | -0.055 | -0.94 | F(1.89)-3(-1.36) | Niveau: R+1 | 3.385 | 0.426725 | 0.012186 | Groupe de modèles:POTEAUX CLOISONS RDC (membre exclu):1442762
2241510 | RDC | AA-bois tasseau cloison | Niveau: RDC | -0.055 | -0.94 | F(1.39)-3(-1.36) | Niveau: R+1 | 3.385 | 0.426725 | 0.012186 | Groupe de modèles:POTEAUX CLOISONS RDC (membre exclu):1442762
2241512 | RDC | AA-bois tasseau cloison | Niveau: RDC | -0.055 | -0.94 | F(0.89)-3(-1.36) | Niveau: R+1 | 3.385 | 0.426725 | 0.012186 | Groupe de modèles:POTEAUX CLOISONS RDC (membre exclu):1442762
2241514 | RDC | AA-bois tasseau cloison | Niveau: RDC | -0.055 | -0.94 | F(0.39)-3(-1.36) | Niveau: R+1 | 3.385 | 0.426725 | 0.012186 | Groupe de modèles:POTEAUX CLOISONS RDC (membre exclu):1442762
2241516 | RDC | AA-bois tasseau cloison | Niveau: RDC | -0.055 | -0.94 | F(-0.09)-3(-1.36) | Niveau: R+1 | 3.385 | 0.426725 | 0.012186 | Groupe de modèles:POTEAUX CLOISONS RDC (membre exclu):1442762 | Données d'identification - Variantes: Modèle de base
2274630 | RDC | AA-bois tasseau cloison | Niveau: RDC | -0.055 | -0.94 | D-4(-0.14) | Niveau: R+1 | 3.385 | 0.426725 | 0.012186 | Groupe de modèles:POTEAUX CLOISONS RDC (membre exclu):1442762
2274663 | RDC | AA-bois tasseau cloison | Niveau: RDC | -0.055 | -0.94 | D-4(-0.59) | Niveau: R+1 | 3.385 | 0.426725 | 0.012186 | Groupe de modèles:POTEAUX CLOISONS RDC (membre exclu):1442762
2274680 | RDC | AA-bois tasseau cloison | Niveau: RDC | -0.055 | -0.94 | D-4(-1.09) | Niveau: R+1 | 3.385 | 0.426725 | 0.012186 | Groupe de modèles:POTEAUX CLOISONS RDC (membre exclu):1442762
2274697 | RDC | AA-bois tasseau cloison | Niveau: RDC | -0.055 | -0.94 | D-4(-1.59) | Niveau: R+1 | 3.385 | 0.426725 | 0.012186 | Groupe de modèles:POTEAUX CLOISONS RDC (membre exclu):1442762
2274714 | RDC | AA-bois tasseau cloison | Niveau: RDC | -0.055 | -0.94 | D-3(2.06) | Niveau: R+1 | 3.385 | 0.426725 | 0.012186 | Groupe de modèles:POTEAUX CLOISONS RDC (membre exclu):1442762
2340492 | RDC | AA-bois tasseau cloison | Niveau: RDC | -0.055 | -0.94 | D-3(1.56) | Niveau: R+1 | 3.385 | 0.426725 | 0.012186 | Groupe de modèles:POTEAUX CLOISONS RDC (membre exclu):1442762 | Données d'identification - Variantes: Modèle de base
2340539 | RDC | AA-bois tasseau cloison | Niveau: RDC | -0.055 | -0.94 | D-2(0.14) | Niveau: R+1 | 3.385 | 0.426725 | 0.012186 | Groupe de modèles:POTEAUX CLOISONS RDC (membre exclu):1442762 | Données d'identification - Variantes: Modèle de base
2340541 | RDC | AA-bois tasseau cloison | Niveau: RDC | -0.055 | -0.94 | D-2(0.59) | Niveau: R+1 | 3.385 | 0.426725 | 0.012186 | Groupe de modèles:POTEAUX CLOISONS RDC (membre exclu):1442762 | Données d'identification - Variantes: Modèle de base
2340543 | RDC | AA-bois tasseau cloison | Niveau: RDC | -0.055 | -0.94 | D-2(1.09) | Niveau: R+1 | 3.385 | 0.426725 | 0.012186 | Groupe de modèles:POTEAUX CLOISONS RDC (membre exclu):1442762
2340545 | RDC | AA-bois tasseau cloison | Niveau: RDC | -0.055 | -0.94 | D-2(1.59) | Niveau: R+1 | 3.385 | 0.426725 | 0.012186 | Groupe de modèles:POTEAUX CLOISONS RDC (membre exclu):1442762
2340547 | RDC | AA-bois tasseau cloison | Niveau: RDC | -0.055 | -0.94 | D-3(-2.06) | Niveau: R+1 | 3.385 | 0.426725 | 0.012186 | Groupe de modèles:POTEAUX CLOISONS RDC (membre exclu):1442762
2340549 | RDC | AA-bois tasseau cloison | Niveau: RDC | -0.055 | -0.94 | D-3(-1.56) | Niveau: R+1 | 3.385 | 0.426725 | 0.012186 | Groupe de modèles:POTEAUX CLOISONS RDC (membre exclu):1442762 | Données d'identification - Variantes: Modèle de base
2513347 | RDC | AA-bois tasseau cloison | Niveau: RDC | -0.055 | -0.94 | G-3(-0.86) | Niveau: R+1 | 3.385 | 0.426725 | 0.012186 | Groupe de modèles:POTEAUX CLOISONS RDC (membre exclu):1442762 | Données d'identification - Variantes: Modèle de base
2517338 | R+2 | AA-bois tasseau cloison | Niveau: R+2 | -0.09 | -0.31 | G(-1.52)-4(-2.01) | Niveau: Toiture | 3 | 0.3786 | 0.0108 | Groupe de modèles:POTEAUX CLOISONS R+2:2514951 | Pset_ColumnCommon - Slope: 0 deg
2517340 | R+2 | AA-bois tasseau cloison | Niveau: R+2 | -0.09 | -0.31 | G(-1.08)-4(-2.01) | Niveau: Toiture | 3 | 0.3786 | 0.0108 | Groupe de modèles:POTEAUX CLOISONS R+2:2514951
2517342 | R+2 | AA-bois tasseau cloison | Niveau: R+2 | -0.09 | -0.31 | G-4(-0.14) | Niveau: Toiture | 3 | 0.3786 | 0.0108 | Groupe de modèles:POTEAUX CLOISONS R+2:2514951 | Pset_ColumnCommon - Slope: 0 deg; Données d'identification - Variantes: Modèle de base
2517344 | R+2 | AA-bois tasseau cloison | Niveau: R+2 | -0.09 | -0.31 | G-4(-1.37) | Niveau: Toiture | 3 | 0.3786 | 0.0108 | Groupe de modèles:POTEAUX CLOISONS R+2:2514951
2517346 | R+2 | AA-bois tasseau cloison | Niveau: R+2 | -0.09 | -0.31 | G-4(-0.33) | Niveau: Toiture | 3 | 0.3786 | 0.0108 | Groupe de modèles:POTEAUX CLOISONS R+2:2514951
2517382 | R+2 | AA-bois tasseau cloison | Niveau: R+2 | -0.09 | -0.31 | G(0.60)-3(-1.69) | Niveau: Toiture | 3 | 0.3786 | 0.0108 | Groupe de modèles:POTEAUX CLOISONS R+2:2514951 | Données d'identification - Variantes: Modèle de base
2517384 | R+2 | AA-bois tasseau cloison | Niveau: R+2 | -0.09 | -0.31 | G(0.60)-3(1.69) | Niveau: Toiture | 3 | 0.3786 | 0.0108 | Groupe de modèles:POTEAUX CLOISONS R+2:2514951
2517386 | R+2 | AA-bois tasseau cloison | Niveau: R+2 | -0.09 | -0.31 | G(0.06)-3(1.69) | Niveau: Toiture | 3 | 0.3786 | 0.0108 | Groupe de modèles:POTEAUX CLOISONS R+2:2514951
2517388 | R+2 | AA-bois tasseau cloison | Niveau: R+2 | -0.09 | -0.31 | G(0.66)-3(1.63) | Niveau: Toiture | 3 | 0.3786 | 0.0108 | Groupe de modèles:POTEAUX CLOISONS R+2:2514951
2517390 | R+2 | AA-bois tasseau cloison | Niveau: R+2 | -0.09 | -0.31 | G(0.66)-3(1.13) | Niveau: Toiture | 3 | 0.3786 | 0.0108 | Groupe de modèles:POTEAUX CLOISONS R+2:2514951
2517392 | R+2 | AA-bois tasseau cloison | Niveau: R+2 | -0.09 | -0.31 | G(0.66)-3(0.63) | Niveau: Toiture | 3 | 0.3786 | 0.0108 | Groupe de modèles:POTEAUX CLOISONS R+2:2514951
2517394 | R+2 | AA-bois tasseau cloison | Niveau: R+2 | -0.09 | -0.31 | G(0.66)-3(0.13) | Niveau: Toiture | 3 | 0.3786 | 0.0108 | Groupe de modèles:POTEAUX CLOISONS R+2:2514951 | Données d'identification - Variantes: Modèle de base
2517396 | R+2 | AA-bois tasseau cloison | Niveau: R+2 | -0.09 | -0.31 | G(0.66)-3(-0.37) | Niveau: Toiture | 3 | 0.3786 | 0.0108 | Groupe de modèles:POTEAUX CLOISONS R+2:2514951
2517398 | R+2 | AA-bois tasseau cloison | Niveau: R+2 | -0.09 | -0.31 | G(0.66)-3(-0.87) | Niveau: Toiture | 3 | 0.3786 | 0.0108 | Groupe de modèles:POTEAUX CLOISONS R+2:2514951 | Données d'identification - Variantes: Modèle de base
2517400 | R+2 | AA-bois tasseau cloison | Niveau: R+2 | -0.09 | -0.31 | G(0.66)-3(-1.30) | Niveau: Toiture | 3 | 0.3786 | 0.0108 | Groupe de modèles:POTEAUX CLOISONS R+2:2514951
2517402 | R+2 | AA-bois tasseau cloison | Niveau: R+2 | -0.09 | -0.31 | G(0.60)-3(0.77) | Niveau: Toiture | 3 | 0.3786 | 0.0108 | Groupe de modèles:POTEAUX CLOISONS R+2:2514951 | Données d'identification - Variantes: Modèle de base
2517404 | R+2 | AA-bois tasseau cloison | Niveau: R+2 | -0.09 | -0.31 | G(0.06)-3(0.77) | Niveau: Toiture | 3 | 0.3786 | 0.0108 | Groupe de modèles:POTEAUX CLOISONS R+2:2514951 | Données d'identification - Variantes: Modèle de base
2517406 | R+2 | AA-bois tasseau cloison | Niveau: R+2 | -0.09 | -0.31 | G(0.06)-3(-0.92) | Niveau: Toiture | 3 | 0.3786 | 0.0108 | Groupe de modèles:POTEAUX CLOISONS R+2:2514951 | Données d'identification - Variantes: Modèle de base
2517426 | R+2 | AA-bois tasseau cloison | Niveau: R+2 | -0.09 | -0.31 | G-3(-1.75) | Niveau: Toiture | 3 | 0.3786 | 0.0108 | Groupe de modèles:POTEAUX CLOISONS R+2:2514951 | Données d'identification - Variantes: Modèle de base
2517455 | R+2 | AA-bois tasseau cloison | Niveau: R+2 | -0.09 | -0.31 | G(0.60)-3(-0.92) | Niveau: Toiture | 3 | 0.3786 | 0.0108 | Groupe de modèles:POTEAUX CLOISONS R+2:2514951
2517457 | R+2 | AA-bois tasseau cloison | Niveau: R+2 | -0.09 | -0.31 | G(0.66)-3(-1.63) | Niveau: Toiture | 3 | 0.3786 | 0.0108 | Groupe de modèles:POTEAUX CLOISONS R+2:2514951 | Données d'identification - Variantes: Modèle de base
2517459 | R+2 | AA-bois tasseau cloison | Niveau: R+2 | -0.09 | -0.31 | G(0.06)-3(-1.69) | Niveau: Toiture | 3 | 0.3786 | 0.0108 | Groupe de modèles:POTEAUX CLOISONS R+2:2514951
2517461 | R+2 | AA-bois tasseau cloison | Niveau: R+2 | -0.09 | -0.31 | G-2(0.14) | Niveau: Toiture | 3 | 0.3786 | 0.0108 | Groupe de modèles:POTEAUX CLOISONS R+2:2514951
2517463 | R+2 | AA-bois tasseau cloison | Niveau: R+2 | -0.09 | -0.31 | G-2(1.37) | Niveau: Toiture | 3 | 0.3786 | 0.0108 | Groupe de modèles:POTEAUX CLOISONS R+2:2514951 | Données d'identification - Variantes: Modèle de base
2517465 | R+2 | AA-bois tasseau cloison | Niveau: R+2 | -0.09 | -0.31 | G-2(0.33) | Niveau: Toiture | 3 | 0.3786 | 0.0108 | Groupe de modèles:POTEAUX CLOISONS R+2:2514951
2517467 | R+2 | AA-bois tasseau cloison | Niveau: R+2 | -0.09 | -0.31 | G-2(1.87) | Niveau: Toiture | 3 | 0.3786 | 0.0108 | Groupe de modèles:POTEAUX CLOISONS R+2:2514951
2519084 | R+1 | AA-bois poutres | Niveau: R+1 | -0.055 | -0.23 | E(-0.57)-3 | Niveau: R+2 | 3.385 | 0.426725 | 0.012186 | Groupe de modèles:POTEAUX CLOISONS R+1:2509806 | Pset_ColumnCommon - Slope: 0 deg; Données d'identification - Variantes: Modèle de base
2519088 | R+1 | AA-bois poutres | Niveau: R+1 | -0.055 | -0.23 | E(-0.57)-3(0.50) | Niveau: R+2 | 3.385 | 0.426725 | 0.012186 | Groupe de modèles:POTEAUX CLOISONS R+1:2509806
2519090 | R+1 | AA-bois poutres | Niveau: R+1 | -0.055 | -0.23 | E(-0.57)-3(1.00) | Niveau: R+2 | 3.385 | 0.426725 | 0.012186 | Groupe de modèles:POTEAUX CLOISONS R+1:2509806
2519092 | R+1 | AA-bois poutres | Niveau: R+1 | -0.055 | -0.23 | E(-0.57)-3(1.38) | Niveau: R+2 | 3.385 | 0.426725 | 0.012186 | Groupe de modèles:POTEAUX CLOISONS R+1:2509806 | Données d'identification - Variantes: Modèle de base
2519094 | R+1 | AA-bois poutres | Niveau: R+1 | -0.055 | -0.23 | E(0.09)-3(1.44) | Niveau: R+2 | 3.385 | 0.426725 | 0.012186 | Groupe de modèles:POTEAUX CLOISONS R+1:2509806 | Données d'identification - Variantes: Modèle de base
2519096 | R+1 | AA-bois poutres | Niveau: R+1 | -0.055 | -0.23 | E(-0.51)-3(1.44) | Niveau: R+2 | 3.385 | 0.426725 | 0.012186 | Groupe de modèles:POTEAUX CLOISONS R+1:2509806 | Données d'identification - Variantes: Modèle de base
2519098 | R+1 | AA-bois poutres | Niveau: R+1 | -0.055 | -0.23 | E(-0.57)-3(-0.50) | Niveau: R+2 | 3.385 | 0.426725 | 0.012186 | Groupe de modèles:POTEAUX CLOISONS R+1:2509806 | Pset_ColumnCommon - Slope: 0 deg; Données d'identification - Variantes: Modèle de base
2519100 | R+1 | AA-bois poutres | Niveau: R+1 | -0.055 | -0.23 | E(-0.57)-3(-1.00) | Niveau: R+2 | 3.385 | 0.426725 | 0.012186 | Groupe de modèles:POTEAUX CLOISONS R+1:2509806
2519102 | R+1 | AA-bois poutres | Niveau: R+1 | -0.055 | -0.23 | E(-0.57)-3(-1.38) | Niveau: R+2 | 3.385 | 0.426725 | 0.012186 | Groupe de modèles:POTEAUX CLOISONS R+1:2509806
2519104 | R+1 | AA-bois poutres | Niveau: R+1 | -0.055 | -0.23 | E(0.09)-3(-1.44) | Niveau: R+2 | 3.385 | 0.426725 | 0.012186 | Groupe de modèles:POTEAUX CLOISONS R+1:2509806
2519106 | R+1 | AA-bois poutres | Niveau: R+1 | -0.055 | -0.23 | E(-0.51)-3(-1.44) | Niveau: R+2 | 3.385 | 0.426725 | 0.012186 | Groupe de modèles:POTEAUX CLOISONS R+1:2509806
2519112 | R+1 | AA-bois poutres | Niveau: R+1 | -0.055 | -0.23 | A(0.57)-3 | Niveau: R+2 | 3.385 | 0.426725 | 0.012186 | Groupe de modèles:POTEAUX CLOISONS R+1:2509806
2519114 | R+1 | AA-bois poutres | Niveau: R+1 | -0.055 | -0.23 | A(0.57)-3(0.50) | Niveau: R+2 | 3.385 | 0.426725 | 0.012186 | Groupe de modèles:POTEAUX CLOISONS R+1:2509806
2519116 | R+1 | AA-bois poutres | Niveau: R+1 | -0.055 | -0.23 | A(0.57)-3(1.00) | Niveau: R+2 | 3.385 | 0.426725 | 0.012186 | Groupe de modèles:POTEAUX CLOISONS R+1:2509806
2519118 | R+1 | AA-bois poutres | Niveau: R+1 | -0.055 | -0.23 | A(0.57)-3(1.38) | Niveau: R+2 | 3.385 | 0.426725 | 0.012186 | Groupe de modèles:POTEAUX CLOISONS R+1:2509806
2519120 | R+1 | AA-bois poutres | Niveau: R+1 | -0.055 | -0.23 | A(-0.05)-3(1.44) | Niveau: R+2 | 3.385 | 0.426725 | 0.012186 | Groupe de modèles:POTEAUX CLOISONS R+1:2509806
2519122 | R+1 | AA-bois poutres | Niveau: R+1 | -0.055 | -0.23 | A(0.51)-3(1.44) | Niveau: R+2 | 3.385 | 0.426725 | 0.012186 | Groupe de modèles:POTEAUX CLOISONS R+1:2509806
2519124 | R+1 | AA-bois poutres | Niveau: R+1 | -0.055 | -0.23 | A(0.57)-3(-0.50) | Niveau: R+2 | 3.385 | 0.426725 | 0.012186 | Groupe de modèles:POTEAUX CLOISONS R+1:2509806
2519126 | R+1 | AA-bois poutres | Niveau: R+1 | -0.055 | -0.23 | A(0.57)-3(-1.00) | Niveau: R+2 | 3.385 | 0.426725 | 0.012186 | Groupe de modèles:POTEAUX CLOISONS R+1:2509806 | Données d'identification - Variantes: Modèle de base
2519128 | R+1 | AA-bois poutres | Niveau: R+1 | -0.055 | -0.23 | A(0.57)-3(-1.38) | Niveau: R+2 | 3.385 | 0.426725 | 0.012186 | Groupe de modèles:POTEAUX CLOISONS R+1:2509806 | Données d'identification - Variantes: Modèle de base
2519130 | R+1 | AA-bois poutres | Niveau: R+1 | -0.055 | -0.23 | A(-0.05)-3(-1.44) | Niveau: R+2 | 3.385 | 0.426725 | 0.012186 | Groupe de modèles:POTEAUX CLOISONS R+1:2509806 | Données d'identification - Variantes: Modèle de base
2519132 | R+1 | AA-bois poutres | Niveau: R+1 | -0.055 | -0.23 | A(0.51)-3(-1.44) | Niveau: R+2 | 3.385 | 0.426725 | 0.012186 | Groupe de modèles:POTEAUX CLOISONS R+1:2509806 | Données d'identification - Variantes: Modèle de base
2519134 | R+1 | AA-bois tasseau cloison | Niveau: R+1 | -0.055 | -0.23 | G-3 | Niveau: R+2 | 3.385 | 0.426725 | 0.012186 | Groupe de modèles:POTEAUX CLOISONS R+1:2509806 | Pset_ColumnCommon - Slope: 0 deg; Données d'identification - Variantes: Modèle de base
2519136 | R+1 | AA-bois tasseau cloison | Niveau: R+1 | -0.055 | -0.23 | G-3(0.50) | Niveau: R+2 | 3.385 | 0.426725 | 0.012186 | Groupe de modèles:POTEAUX CLOISONS R+1:2509806
2519138 | R+1 | AA-bois tasseau cloison | Niveau: R+1 | -0.055 | -0.23 | G-3(1.00) | Niveau: R+2 | 3.385 | 0.426725 | 0.012186 | Groupe de modèles:POTEAUX CLOISONS R+1:2509806
2519140 | R+1 | AA-bois tasseau cloison | Niveau: R+1 | -0.055 | -0.23 | G-3(1.50) | Niveau: R+2 | 3.385 | 0.426725 | 0.012186 | Groupe de modèles:POTEAUX CLOISONS R+1:2509806 | Données d'identification - Variantes: Modèle de base
2519142 | R+1 | AA-bois tasseau cloison | Niveau: R+1 | -0.055 | -0.23 | G-3(2.00) | Niveau: R+2 | 3.385 | 0.426725 | 0.012186 | Groupe de modèles:POTEAUX CLOISONS R+1:2509806 | Données d'identification - Variantes: Modèle de base
2519144 | R+1 | AA-bois tasseau cloison | Niveau: R+1 | -0.055 | -0.23 | G-4(-1.65) | Niveau: R+2 | 3.385 | 0.426725 | 0.012186 | Groupe de modèles:POTEAUX CLOISONS R+1:2509806
2519146 | R+1 | AA-bois tasseau cloison | Niveau: R+1 | -0.055 | -0.23 | G-3(-0.50) | Niveau: R+2 | 3.385 | 0.426725 | 0.012186 | Groupe de modèles:POTEAUX CLOISONS R+1:2509806 | Pset_ColumnCommon - Slope: 0 deg; Données d'identification - Variantes: Modèle de base
2519148 | R+1 | AA-bois tasseau cloison | Niveau: R+1 | -0.055 | -0.23 | G(-1.52)-4(-2.01) | Niveau: R+2 | 3.385 | 0.426725 | 0.012186 | Groupe de modèles:POTEAUX CLOISONS R+1:2509806
2519150 | R+1 | AA-bois tasseau cloison | Niveau: R+1 | -0.055 | -0.23 | G(-1.08)-4(-2.01) | Niveau: R+2 | 3.385 | 0.426725 | 0.012186 | Groupe de modèles:POTEAUX CLOISONS R+1:2509806 | Données d'identification - Variantes: Modèle de base
2519152 | R+1 | AA-bois tasseau cloison | Niveau: R+1 | -0.055 | -0.23 | G-4(-0.14) | Niveau: R+2 | 3.385 | 0.426725 | 0.012186 | Groupe de modèles:POTEAUX CLOISONS R+1:2509806
2519154 | R+1 | AA-bois tasseau cloison | Niveau: R+1 | -0.055 | -0.23 | G-4(-1.37) | Niveau: R+2 | 3.385 | 0.426725 | 0.012186 | Groupe de modèles:POTEAUX CLOISONS R+1:2509806 | Données d'identification - Variantes: Modèle de base
2519156 | R+1 | AA-bois tasseau cloison | Niveau: R+1 | -0.055 | -0.23 | G-4(-0.33) | Niveau: R+2 | 3.385 | 0.426725 | 0.012186 | Groupe de modèles:POTEAUX CLOISONS R+1:2509806
2519158 | R+1 | AA-bois tasseau cloison | Niveau: R+1 | -0.055 | -0.23 | H-3 | Niveau: R+2 | 3.385 | 0.426725 | 0.012186 | Groupe de modèles:POTEAUX CLOISONS R+1:2509806 | Données d'identification - Variantes: Modèle de base
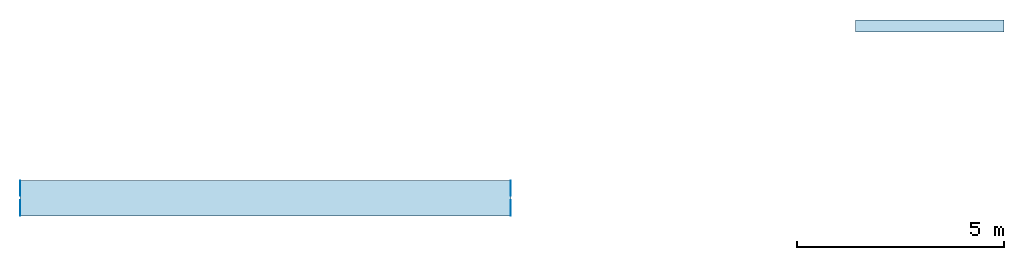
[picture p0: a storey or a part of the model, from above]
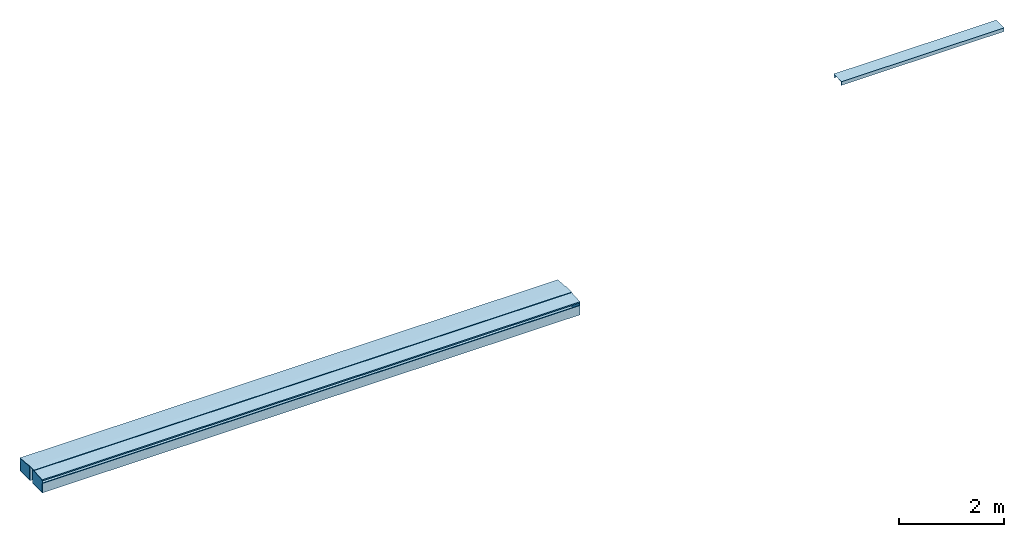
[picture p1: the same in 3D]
Properties of the parts of a building model (IFC2X3), part 2 of 5

# IfcColumn: HEA160 (395)
Name (poteau bois 8x4.5 cm:HEA160:...) | In | Material = Matériau structurel | Niveau = Niveau de base | Décalage inférieur (m) | Décalage supérieur (m) | Marque d'emplacement du poteau | Niveau supérieur | Longueur (m) | Surface (m2) | Volume (m3) | Group
2519160 | R+1 | AA-bois tasseau cloison | Niveau: R+1 | -0.055 | -0.23 | H-3(0.50) | Niveau: R+2 | 3.385 | 0.426725 | 0.012186 | Groupe de modèles:POTEAUX CLOISONS R+1:2509806 | Données d'identification - Variantes: Modèle de base
2519162 | R+1 | AA-bois tasseau cloison | Niveau: R+1 | -0.055 | -0.23 | H-3(1.00) | Niveau: R+2 | 3.385 | 0.426725 | 0.012186 | Groupe de modèles:POTEAUX CLOISONS R+1:2509806
2519164 | R+1 | AA-bois tasseau cloison | Niveau: R+1 | -0.055 | -0.23 | H-3(1.50) | Niveau: R+2 | 3.385 | 0.426725 | 0.012186 | Groupe de modèles:POTEAUX CLOISONS R+1:2509806 | Données d'identification - Variantes: Modèle de base
2519166 | R+1 | AA-bois tasseau cloison | Niveau: R+1 | -0.055 | -0.23 | H-3(2.00) | Niveau: R+2 | 3.385 | 0.426725 | 0.012186 | Groupe de modèles:POTEAUX CLOISONS R+1:2509806
2519168 | R+1 | AA-bois tasseau cloison | Niveau: R+1 | -0.055 | -0.23 | H-4(-1.65) | Niveau: R+2 | 3.385 | 0.426725 | 0.012186 | Groupe de modèles:POTEAUX CLOISONS R+1:2509806
2519170 | R+1 | AA-bois tasseau cloison | Niveau: R+1 | -0.055 | -0.23 | H-2(0.14) | Niveau: R+2 | 3.385 | 0.426725 | 0.012186 | Groupe de modèles:POTEAUX CLOISONS R+1:2509806 | Données d'identification - Variantes: Modèle de base
2519172 | R+1 | AA-bois tasseau cloison | Niveau: R+1 | -0.055 | -0.23 | H-3(-0.50) | Niveau: R+2 | 3.385 | 0.426725 | 0.012186 | Groupe de modèles:POTEAUX CLOISONS R+1:2509806 | Données d'identification - Variantes: Modèle de base
2519174 | R+1 | AA-bois tasseau cloison | Niveau: R+1 | -0.055 | -0.23 | H-3(-1.00) | Niveau: R+2 | 3.385 | 0.426725 | 0.012186 | Groupe de modèles:POTEAUX CLOISONS R+1:2509806 | Données d'identification - Variantes: Modèle de base
2519176 | R+1 | AA-bois tasseau cloison | Niveau: R+1 | -0.055 | -0.23 | H-3(-1.50) | Niveau: R+2 | 3.385 | 0.426725 | 0.012186 | Groupe de modèles:POTEAUX CLOISONS R+1:2509806
2519178 | R+1 | AA-bois tasseau cloison | Niveau: R+1 | -0.055 | -0.23 | H-3(-2.00) | Niveau: R+2 | 3.385 | 0.426725 | 0.012186 | Groupe de modèles:POTEAUX CLOISONS R+1:2509806 | Données d'identification - Variantes: Modèle de base
2519180 | R+1 | AA-bois tasseau cloison | Niveau: R+1 | -0.055 | -0.23 | H-2(1.65) | Niveau: R+2 | 3.385 | 0.426725 | 0.012186 | Groupe de modèles:POTEAUX CLOISONS R+1:2509806
2519182 | R+1 | AA-bois tasseau cloison | Niveau: R+1 | -0.055 | -0.23 | H-2(1.37) | Niveau: R+2 | 3.385 | 0.426725 | 0.012186 | Groupe de modèles:POTEAUX CLOISONS R+1:2509806
2519184 | R+1 | AA-bois tasseau cloison | Niveau: R+1 | -0.055 | -0.23 | H-2(0.33) | Niveau: R+2 | 3.385 | 0.426725 | 0.012186 | Groupe de modèles:POTEAUX CLOISONS R+1:2509806
2519186 | R+1 | AA-bois tasseau cloison | Niveau: R+1 | -0.055 | -0.23 | H-4(-0.14) | Niveau: R+2 | 3.385 | 0.426725 | 0.012186 | Groupe de modèles:POTEAUX CLOISONS R+1:2509806
2519188 | R+1 | AA-bois tasseau cloison | Niveau: R+1 | -0.055 | -0.23 | H-4(-1.37) | Niveau: R+2 | 3.385 | 0.426725 | 0.012186 | Groupe de modèles:POTEAUX CLOISONS R+1:2509806
2519190 | R+1 | AA-bois tasseau cloison | Niveau: R+1 | -0.055 | -0.23 | H-4(-0.33) | Niveau: R+2 | 3.385 | 0.426725 | 0.012186 | Groupe de modèles:POTEAUX CLOISONS R+1:2509806 | Données d'identification - Variantes: Modèle de base
2519192 | R+1 | AA-bois tasseau cloison | Niveau: R+1 | -0.055 | -0.23 | G(0.60)-3(-1.69) | Niveau: R+2 | 3.385 | 0.426725 | 0.012186 | Groupe de modèles:POTEAUX CLOISONS R+1:2509806
2519194 | R+1 | AA-bois tasseau cloison | Niveau: R+1 | -0.055 | -0.23 | G(0.60)-3(1.69) | Niveau: R+2 | 3.385 | 0.426725 | 0.012186 | Groupe de modèles:POTEAUX CLOISONS R+1:2509806
2519196 | R+1 | AA-bois tasseau cloison | Niveau: R+1 | -0.055 | -0.23 | G(0.06)-3(1.69) | Niveau: R+2 | 3.385 | 0.426725 | 0.012186 | Groupe de modèles:POTEAUX CLOISONS R+1:2509806 | Données d'identification - Variantes: Modèle de base
2519198 | R+1 | AA-bois tasseau cloison | Niveau: R+1 | -0.055 | -0.23 | G(0.66)-3(1.63) | Niveau: R+2 | 3.385 | 0.426725 | 0.012186 | Groupe de modèles:POTEAUX CLOISONS R+1:2509806 | Données d'identification - Variantes: Modèle de base
2519200 | R+1 | AA-bois tasseau cloison | Niveau: R+1 | -0.055 | -0.23 | G(0.66)-3(1.13) | Niveau: R+2 | 3.385 | 0.426725 | 0.012186 | Groupe de modèles:POTEAUX CLOISONS R+1:2509806
2519202 | R+1 | AA-bois tasseau cloison | Niveau: R+1 | -0.055 | -0.23 | G(0.66)-3(0.63) | Niveau: R+2 | 3.385 | 0.426725 | 0.012186 | Groupe de modèles:POTEAUX CLOISONS R+1:2509806
2519204 | R+1 | AA-bois tasseau cloison | Niveau: R+1 | -0.055 | -0.23 | G(0.66)-3(0.13) | Niveau: R+2 | 3.385 | 0.426725 | 0.012186 | Groupe de modèles:POTEAUX CLOISONS R+1:2509806 | Données d'identification - Variantes: Modèle de base
2519206 | R+1 | AA-bois tasseau cloison | Niveau: R+1 | -0.055 | -0.23 | G(0.66)-3(-0.37) | Niveau: R+2 | 3.385 | 0.426725 | 0.012186 | Groupe de modèles:POTEAUX CLOISONS R+1:2509806
2519208 | R+1 | AA-bois tasseau cloison | Niveau: R+1 | -0.055 | -0.23 | G(0.66)-3(-0.87) | Niveau: R+2 | 3.385 | 0.426725 | 0.012186 | Groupe de modèles:POTEAUX CLOISONS R+1:2509806 | Données d'identification - Variantes: Modèle de base
2519210 | R+1 | AA-bois tasseau cloison | Niveau: R+1 | -0.055 | -0.23 | G(0.66)-3(-1.30) | Niveau: R+2 | 3.385 | 0.426725 | 0.012186 | Groupe de modèles:POTEAUX CLOISONS R+1:2509806
2519212 | R+1 | AA-bois tasseau cloison | Niveau: R+1 | -0.055 | -0.23 | G(0.60)-3(0.77) | Niveau: R+2 | 3.385 | 0.426725 | 0.012186 | Groupe de modèles:POTEAUX CLOISONS R+1:2509806 | Données d'identification - Variantes: Modèle de base
2519214 | R+1 | AA-bois tasseau cloison | Niveau: R+1 | -0.055 | -0.23 | G(0.06)-3(0.77) | Niveau: R+2 | 3.385 | 0.426725 | 0.012186 | Groupe de modèles:POTEAUX CLOISONS R+1:2509806
2519216 | R+1 | AA-bois tasseau cloison | Niveau: R+1 | -0.055 | -0.23 | G(0.06)-3(-0.92) | Niveau: R+2 | 3.385 | 0.426725 | 0.012186 | Groupe de modèles:POTEAUX CLOISONS R+1:2509806
2519236 | R+1 | AA-bois tasseau cloison | Niveau: R+1 | -0.055 | -0.23 | G-3(-1.75) | Niveau: R+2 | 3.385 | 0.426725 | 0.012186 | Groupe de modèles:POTEAUX CLOISONS R+1:2509806
2519238 | R+1 | AA-bois tasseau cloison | Niveau: R+1 | -0.055 | -0.23 | D-4(-0.14) | Niveau: R+2 | 3.385 | 0.426725 | 0.012186 | Groupe de modèles:POTEAUX CLOISONS R+1:2509806
2519240 | R+1 | AA-bois tasseau cloison | Niveau: R+1 | -0.055 | -0.23 | D-4(-0.59) | Niveau: R+2 | 3.385 | 0.426725 | 0.012186 | Groupe de modèles:POTEAUX CLOISONS R+1:2509806 | Données d'identification - Variantes: Modèle de base
2519242 | R+1 | AA-bois tasseau cloison | Niveau: R+1 | -0.055 | -0.23 | D-4(-1.09) | Niveau: R+2 | 3.385 | 0.426725 | 0.012186 | Groupe de modèles:POTEAUX CLOISONS R+1:2509806
2519244 | R+1 | AA-bois tasseau cloison | Niveau: R+1 | -0.055 | -0.23 | D-4(-1.59) | Niveau: R+2 | 3.385 | 0.426725 | 0.012186 | Groupe de modèles:POTEAUX CLOISONS R+1:2509806 | Données d'identification - Variantes: Modèle de base
2519246 | R+1 | AA-bois tasseau cloison | Niveau: R+1 | -0.055 | -0.23 | D-3(2.06) | Niveau: R+2 | 3.385 | 0.426725 | 0.012186 | Groupe de modèles:POTEAUX CLOISONS R+1:2509806 | Données d'identification - Variantes: Modèle de base
2519248 | R+1 | AA-bois tasseau cloison | Niveau: R+1 | -0.055 | -0.23 | D-3(1.56) | Niveau: R+2 | 3.385 | 0.426725 | 0.012186 | Groupe de modèles:POTEAUX CLOISONS R+1:2509806 | Données d'identification - Variantes: Modèle de base
2519250 | R+1 | AA-bois tasseau cloison | Niveau: R+1 | -0.055 | -0.23 | D-2(0.14) | Niveau: R+2 | 3.385 | 0.426725 | 0.012186 | Groupe de modèles:POTEAUX CLOISONS R+1:2509806 | Données d'identification - Variantes: Modèle de base
2519252 | R+1 | AA-bois tasseau cloison | Niveau: R+1 | -0.055 | -0.23 | D-2(0.59) | Niveau: R+2 | 3.385 | 0.426725 | 0.012186 | Groupe de modèles:POTEAUX CLOISONS R+1:2509806 | Données d'identification - Variantes: Modèle de base
2519254 | R+1 | AA-bois tasseau cloison | Niveau: R+1 | -0.055 | -0.23 | D-2(1.09) | Niveau: R+2 | 3.385 | 0.426725 | 0.012186 | Groupe de modèles:POTEAUX CLOISONS R+1:2509806 | Données d'identification - Variantes: Modèle de base
2519256 | R+1 | AA-bois tasseau cloison | Niveau: R+1 | -0.055 | -0.23 | D-2(1.59) | Niveau: R+2 | 3.385 | 0.426725 | 0.012186 | Groupe de modèles:POTEAUX CLOISONS R+1:2509806 | Données d'identification - Variantes: Modèle de base
2519258 | R+1 | AA-bois tasseau cloison | Niveau: R+1 | -0.055 | -0.23 | D-3(-2.06) | Niveau: R+2 | 3.385 | 0.426725 | 0.012186 | Groupe de modèles:POTEAUX CLOISONS R+1:2509806 | Données d'identification - Variantes: Modèle de base
2519260 | R+1 | AA-bois tasseau cloison | Niveau: R+1 | -0.055 | -0.23 | D-3(-1.56) | Niveau: R+2 | 3.385 | 0.426725 | 0.012186 | Groupe de modèles:POTEAUX CLOISONS R+1:2509806 | Données d'identification - Variantes: Modèle de base
2519263 | R+1 | AA-bois tasseau cloison | Niveau: R+1 | -0.055 | -0.23 | G-3(-0.86) | Niveau: R+2 | 3.385 | 0.426725 | 0.012186 | Groupe de modèles:POTEAUX CLOISONS R+1:2509806
2519265 | R+1 | AA-bois tasseau cloison | Niveau: R+1 | -0.055 | -0.23 | G(0.60)-3(-0.92) | Niveau: R+2 | 3.385 | 0.426725 | 0.012186 | Groupe de modèles:POTEAUX CLOISONS R+1:2509806
2519267 | R+1 | AA-bois tasseau cloison | Niveau: R+1 | -0.055 | -0.23 | G(0.66)-3(-1.63) | Niveau: R+2 | 3.385 | 0.426725 | 0.012186 | Groupe de modèles:POTEAUX CLOISONS R+1:2509806
2519269 | R+1 | AA-bois tasseau cloison | Niveau: R+1 | -0.055 | -0.23 | G(0.06)-3(-1.69) | Niveau: R+2 | 3.385 | 0.426725 | 0.012186 | Groupe de modèles:POTEAUX CLOISONS R+1:2509806
2519271 | R+1 | AA-bois tasseau cloison | Niveau: R+1 | -0.055 | -0.23 | G-2(0.14) | Niveau: R+2 | 3.385 | 0.426725 | 0.012186 | Groupe de modèles:POTEAUX CLOISONS R+1:2509806
2519273 | R+1 | AA-bois tasseau cloison | Niveau: R+1 | -0.055 | -0.23 | G-2(1.37) | Niveau: R+2 | 3.385 | 0.426725 | 0.012186 | Groupe de modèles:POTEAUX CLOISONS R+1:2509806
2519275 | R+1 | AA-bois tasseau cloison | Niveau: R+1 | -0.055 | -0.23 | G-2(0.33) | Niveau: R+2 | 3.385 | 0.426725 | 0.012186 | Groupe de modèles:POTEAUX CLOISONS R+1:2509806
2519277 | R+1 | AA-bois tasseau cloison | Niveau: R+1 | -0.055 | -0.23 | G-2(1.87) | Niveau: R+2 | 3.385 | 0.426725 | 0.012186 | Groupe de modèles:POTEAUX CLOISONS R+1:2509806 | Données d'identification - Variantes: Modèle de base
2519279 | R+1 | AA-bois tasseau cloison | Niveau: R+1 | -0.055 | -0.23 | I-3 | Niveau: R+2 | 3.385 | 0.426725 | 0.012186 | Groupe de modèles:POTEAUX CLOISONS R+1:2509806 | Données d'identification - Variantes: Modèle de base
2519281 | R+1 | AA-bois tasseau cloison | Niveau: R+1 | -0.055 | -0.23 | I-3(0.51) | Niveau: R+2 | 3.385 | 0.426725 | 0.012186 | Groupe de modèles:POTEAUX CLOISONS R+1:2509806 | Données d'identification - Variantes: Modèle de base
2519283 | R+1 | AA-bois tasseau cloison | Niveau: R+1 | -0.055 | -0.23 | I-3(1.55) | Niveau: R+2 | 3.385 | 0.426725 | 0.012186 | Groupe de modèles:POTEAUX CLOISONS R+1:2509806
2519285 | R+1 | AA-bois tasseau cloison | Niveau: R+1 | -0.055 | -0.23 | I-3(2.00) | Niveau: R+2 | 3.385 | 0.426725 | 0.012186 | Groupe de modèles:POTEAUX CLOISONS R+1:2509806 | Données d'identification - Variantes: Modèle de base
2519287 | R+1 | AA-bois tasseau cloison | Niveau: R+1 | -0.055 | -0.23 | I-4(-1.65) | Niveau: R+2 | 3.385 | 0.426725 | 0.012186 | Groupe de modèles:POTEAUX CLOISONS R+1:2509806 | Données d'identification - Variantes: Modèle de base
2519289 | R+1 | AA-bois tasseau cloison | Niveau: R+1 | -0.055 | -0.23 | I-2(0.14) | Niveau: R+2 | 3.385 | 0.426725 | 0.012186 | Groupe de modèles:POTEAUX CLOISONS R+1:2509806
2519291 | R+1 | AA-bois tasseau cloison | Niveau: R+1 | -0.055 | -0.23 | I-3(-0.50) | Niveau: R+2 | 3.385 | 0.426725 | 0.012186 | Groupe de modèles:POTEAUX CLOISONS R+1:2509806 | Données d'identification - Variantes: Modèle de base
2519293 | R+1 | AA-bois tasseau cloison | Niveau: R+1 | -0.055 | -0.23 | I-3(-1.00) | Niveau: R+2 | 3.385 | 0.426725 | 0.012186 | Groupe de modèles:POTEAUX CLOISONS R+1:2509806 | Données d'identification - Variantes: Modèle de base
2519295 | R+1 | AA-bois tasseau cloison | Niveau: R+1 | -0.055 | -0.23 | I-3(-1.50) | Niveau: R+2 | 3.385 | 0.426725 | 0.012186 | Groupe de modèles:POTEAUX CLOISONS R+1:2509806
2519297 | R+1 | AA-bois tasseau cloison | Niveau: R+1 | -0.055 | -0.23 | I-3(-2.00) | Niveau: R+2 | 3.385 | 0.426725 | 0.012186 | Groupe de modèles:POTEAUX CLOISONS R+1:2509806 | Données d'identification - Variantes: Modèle de base
2519299 | R+1 | AA-bois tasseau cloison | Niveau: R+1 | -0.055 | -0.23 | I-2(1.65) | Niveau: R+2 | 3.385 | 0.426725 | 0.012186 | Groupe de modèles:POTEAUX CLOISONS R+1:2509806
2519301 | R+1 | AA-bois tasseau cloison | Niveau: R+1 | -0.055 | -0.23 | I-4(-0.14) | Niveau: R+2 | 3.385 | 0.426725 | 0.012186 | Groupe de modèles:POTEAUX CLOISONS R+1:2509806
2519303 | R+1 | AA-bois tasseau cloison | Niveau: R+1 | -0.055 | -0.23 | I-4(-1.37) | Niveau: R+2 | 3.385 | 0.426725 | 0.012186 | Groupe de modèles:POTEAUX CLOISONS R+1:2509806
2519305 | R+1 | AA-bois tasseau cloison | Niveau: R+1 | -0.055 | -0.23 | I-4(-0.33) | Niveau: R+2 | 3.385 | 0.426725 | 0.012186 | Groupe de modèles:POTEAUX CLOISONS R+1:2509806
2519307 | R+1 | AA-bois tasseau cloison | Niveau: R+1 | -0.055 | -0.23 | J-3 | Niveau: R+2 | 3.385 | 0.426725 | 0.012186 | Groupe de modèles:POTEAUX CLOISONS R+1:2509806 | Données d'identification - Variantes: Modèle de base
2519309 | R+1 | AA-bois tasseau cloison | Niveau: R+1 | -0.055 | -0.23 | J-3(0.50) | Niveau: R+2 | 3.385 | 0.426725 | 0.012186 | Groupe de modèles:POTEAUX CLOISONS R+1:2509806
2519311 | R+1 | AA-bois tasseau cloison | Niveau: R+1 | -0.055 | -0.23 | J-3(1.00) | Niveau: R+2 | 3.385 | 0.426725 | 0.012186 | Groupe de modèles:POTEAUX CLOISONS R+1:2509806 | Données d'identification - Variantes: Modèle de base
2519313 | R+1 | AA-bois tasseau cloison | Niveau: R+1 | -0.055 | -0.23 | J-3(1.50) | Niveau: R+2 | 3.385 | 0.426725 | 0.012186 | Groupe de modèles:POTEAUX CLOISONS R+1:2509806 | Données d'identification - Variantes: Modèle de base
2519315 | R+1 | AA-bois tasseau cloison | Niveau: R+1 | -0.055 | -0.23 | J-3(2.00) | Niveau: R+2 | 3.385 | 0.426725 | 0.012186 | Groupe de modèles:POTEAUX CLOISONS R+1:2509806
2519317 | R+1 | AA-bois tasseau cloison | Niveau: R+1 | -0.055 | -0.23 | J-4(-1.65) | Niveau: R+2 | 3.385 | 0.426725 | 0.012186 | Groupe de modèles:POTEAUX CLOISONS R+1:2509806
2519319 | R+1 | AA-bois tasseau cloison | Niveau: R+1 | -0.055 | -0.23 | J-2(0.14) | Niveau: R+2 | 3.385 | 0.426725 | 0.012186 | Groupe de modèles:POTEAUX CLOISONS R+1:2509806 | Données d'identification - Variantes: Modèle de base
2519321 | R+1 | AA-bois tasseau cloison | Niveau: R+1 | -0.055 | -0.23 | J-3(-0.50) | Niveau: R+2 | 3.385 | 0.426725 | 0.012186 | Groupe de modèles:POTEAUX CLOISONS R+1:2509806 | Données d'identification - Variantes: Modèle de base
2519323 | R+1 | AA-bois tasseau cloison | Niveau: R+1 | -0.055 | -0.23 | J-3(-1.00) | Niveau: R+2 | 3.385 | 0.426725 | 0.012186 | Groupe de modèles:POTEAUX CLOISONS R+1:2509806
2519325 | R+1 | AA-bois tasseau cloison | Niveau: R+1 | -0.055 | -0.23 | J-3(-1.50) | Niveau: R+2 | 3.385 | 0.426725 | 0.012186 | Groupe de modèles:POTEAUX CLOISONS R+1:2509806
2519327 | R+1 | AA-bois tasseau cloison | Niveau: R+1 | -0.055 | -0.23 | J-3(-2.00) | Niveau: R+2 | 3.385 | 0.426725 | 0.012186 | Groupe de modèles:POTEAUX CLOISONS R+1:2509806 | Données d'identification - Variantes: Modèle de base
2519329 | R+1 | AA-bois tasseau cloison | Niveau: R+1 | -0.055 | -0.23 | J-2(1.65) | Niveau: R+2 | 3.385 | 0.426725 | 0.012186 | Groupe de modèles:POTEAUX CLOISONS R+1:2509806 | Données d'identification - Variantes: Modèle de base
2519331 | R+1 | AA-bois tasseau cloison | Niveau: R+1 | -0.055 | -0.23 | J-4(-0.14) | Niveau: R+2 | 3.385 | 0.426725 | 0.012186 | Groupe de modèles:POTEAUX CLOISONS R+1:2509806
2519333 | R+1 | AA-bois tasseau cloison | Niveau: R+1 | -0.055 | -0.23 | J-4(-1.37) | Niveau: R+2 | 3.385 | 0.426725 | 0.012186 | Groupe de modèles:POTEAUX CLOISONS R+1:2509806
2519335 | R+1 | AA-bois tasseau cloison | Niveau: R+1 | -0.055 | -0.23 | J-4(-0.33) | Niveau: R+2 | 3.385 | 0.426725 | 0.012186 | Groupe de modèles:POTEAUX CLOISONS R+1:2509806
2519337 | R+1 | AA-bois tasseau cloison | Niveau: R+1 | -0.055 | -0.23 | I-2(1.15) | Niveau: R+2 | 3.385 | 0.426725 | 0.012186 | Groupe de modèles:POTEAUX CLOISONS R+1:2509806
2519339 | R+1 | AA-bois tasseau cloison | Niveau: R+1 | -0.055 | -0.23 | I-2(0.65) | Niveau: R+2 | 3.385 | 0.426725 | 0.012186 | Groupe de modèles:POTEAUX CLOISONS R+1:2509806 | Données d'identification - Variantes: Modèle de base
2519341 | R+1 | AA-bois tasseau cloison | Niveau: R+1 | -0.055 | -0.23 | J-2(1.15) | Niveau: R+2 | 3.385 | 0.426725 | 0.012186 | Groupe de modèles:POTEAUX CLOISONS R+1:2509806
2519343 | R+1 | AA-bois tasseau cloison | Niveau: R+1 | -0.055 | -0.23 | J-2(0.65) | Niveau: R+2 | 3.385 | 0.426725 | 0.012186 | Groupe de modèles:POTEAUX CLOISONS R+1:2509806
2519345 | R+1 | AA-bois tasseau cloison | Niveau: R+1 | -0.055 | -0.23 | K-3 | Niveau: R+2 | 3.385 | 0.426725 | 0.012186 | Groupe de modèles:POTEAUX CLOISONS R+1:2509806
2519347 | R+1 | AA-bois tasseau cloison | Niveau: R+1 | -0.055 | -0.23 | K-3(0.50) | Niveau: R+2 | 3.385 | 0.426725 | 0.012186 | Groupe de modèles:POTEAUX CLOISONS R+1:2509806 | Données d'identification - Variantes: Modèle de base
2519349 | R+1 | AA-bois tasseau cloison | Niveau: R+1 | -0.055 | -0.23 | K-3(1.00) | Niveau: R+2 | 3.385 | 0.426725 | 0.012186 | Groupe de modèles:POTEAUX CLOISONS R+1:2509806
2519351 | R+1 | AA-bois tasseau cloison | Niveau: R+1 | -0.055 | -0.23 | K-3(1.50) | Niveau: R+2 | 3.385 | 0.426725 | 0.012186 | Groupe de modèles:POTEAUX CLOISONS R+1:2509806 | Données d'identification - Variantes: Modèle de base
2519353 | R+1 | AA-bois tasseau cloison | Niveau: R+1 | -0.055 | -0.23 | K-3(2.00) | Niveau: R+2 | 3.385 | 0.426725 | 0.012186 | Groupe de modèles:POTEAUX CLOISONS R+1:2509806
2519355 | R+1 | AA-bois tasseau cloison | Niveau: R+1 | -0.055 | -0.23 | K-4(-1.65) | Niveau: R+2 | 3.385 | 0.426725 | 0.012186 | Groupe de modèles:POTEAUX CLOISONS R+1:2509806
2519357 | R+1 | AA-bois tasseau cloison | Niveau: R+1 | -0.055 | -0.23 | K-2(0.14) | Niveau: R+2 | 3.385 | 0.426725 | 0.012186 | Groupe de modèles:POTEAUX CLOISONS R+1:2509806 | Données d'identification - Variantes: Modèle de base
2519359 | R+1 | AA-bois tasseau cloison | Niveau: R+1 | -0.055 | -0.23 | K-3(-0.50) | Niveau: R+2 | 3.385 | 0.426725 | 0.012186 | Groupe de modèles:POTEAUX CLOISONS R+1:2509806
2519361 | R+1 | AA-bois tasseau cloison | Niveau: R+1 | -0.055 | -0.23 | K-3(-1.00) | Niveau: R+2 | 3.385 | 0.426725 | 0.012186 | Groupe de modèles:POTEAUX CLOISONS R+1:2509806
2519363 | R+1 | AA-bois tasseau cloison | Niveau: R+1 | -0.055 | -0.23 | K-3(-1.50) | Niveau: R+2 | 3.385 | 0.426725 | 0.012186 | Groupe de modèles:POTEAUX CLOISONS R+1:2509806
2519365 | R+1 | AA-bois tasseau cloison | Niveau: R+1 | -0.055 | -0.23 | K-3(-2.00) | Niveau: R+2 | 3.385 | 0.426725 | 0.012186 | Groupe de modèles:POTEAUX CLOISONS R+1:2509806
2519367 | R+1 | AA-bois tasseau cloison | Niveau: R+1 | -0.055 | -0.23 | K-2(1.65) | Niveau: R+2 | 3.385 | 0.426725 | 0.012186 | Groupe de modèles:POTEAUX CLOISONS R+1:2509806
2519369 | R+1 | AA-bois tasseau cloison | Niveau: R+1 | -0.055 | -0.23 | K-4(-0.14) | Niveau: R+2 | 3.385 | 0.426725 | 0.012186 | Groupe de modèles:POTEAUX CLOISONS R+1:2509806
2519371 | R+1 | AA-bois tasseau cloison | Niveau: R+1 | -0.055 | -0.23 | K-4(-1.37) | Niveau: R+2 | 3.385 | 0.426725 | 0.012186 | Groupe de modèles:POTEAUX CLOISONS R+1:2509806 | Données d'identification - Variantes: Modèle de base
2519373 | R+1 | AA-bois tasseau cloison | Niveau: R+1 | -0.055 | -0.23 | K-4(-0.33) | Niveau: R+2 | 3.385 | 0.426725 | 0.012186 | Groupe de modèles:POTEAUX CLOISONS R+1:2509806
2519375 | R+1 | AA-bois tasseau cloison | Niveau: R+1 | -0.055 | -0.23 | K-2(1.15) | Niveau: R+2 | 3.385 | 0.426725 | 0.012186 | Groupe de modèles:POTEAUX CLOISONS R+1:2509806 | Données d'identification - Variantes: Modèle de base
2519377 | R+1 | AA-bois tasseau cloison | Niveau: R+1 | -0.055 | -0.23 | K-2(0.65) | Niveau: R+2 | 3.385 | 0.426725 | 0.012186 | Groupe de modèles:POTEAUX CLOISONS R+1:2509806 | Données d'identification - Variantes: Modèle de base
2519379 | R+1 | AA-bois tasseau cloison | Niveau: R+1 | -0.055 | -0.23 | D-3(-1.06) | Niveau: R+2 | 3.385 | 0.426725 | 0.012186 | Groupe de modèles:POTEAUX CLOISONS R+1:2509806
2519381 | R+1 | AA-bois tasseau cloison | Niveau: R+1 | -0.055 | -0.23 | D-3(-0.56) | Niveau: R+2 | 3.385 | 0.426725 | 0.012186 | Groupe de modèles:POTEAUX CLOISONS R+1:2509806
2519383 | R+1 | AA-bois tasseau cloison | Niveau: R+1 | -0.055 | -0.23 | D-3(-0.06) | Niveau: R+2 | 3.385 | 0.426725 | 0.012186 | Groupe de modèles:POTEAUX CLOISONS R+1:2509806 | Données d'identification - Variantes: Modèle de base
2519385 | R+1 | AA-bois tasseau cloison | Niveau: R+1 | -0.055 | -0.23 | D-3(0.21) | Niveau: R+2 | 3.385 | 0.426725 | 0.012186 | Groupe de modèles:POTEAUX CLOISONS R+1:2509806 | Données d'identification - Variantes: Modèle de base
2519387 | R+1 | AA-bois tasseau cloison | Niveau: R+1 | -0.055 | -0.23 | D-3(1.26) | Niveau: R+2 | 3.385 | 0.426725 | 0.012186 | Groupe de modèles:POTEAUX CLOISONS R+1:2509806 | Données d'identification - Variantes: Modèle de base
2519389 | R+1 | AA-bois tasseau cloison | Niveau: R+1 | -0.055 | -0.23 | C-4(-0.14) | Niveau: R+2 | 3.385 | 0.426725 | 0.012186 | Groupe de modèles:POTEAUX CLOISONS R+1:2509806
2519391 | R+1 | AA-bois tasseau cloison | Niveau: R+1 | -0.055 | -0.23 | C-4(-0.65) | Niveau: R+2 | 3.385 | 0.426725 | 0.012186 | Groupe de modèles:POTEAUX CLOISONS R+1:2509806 | Données d'identification - Variantes: Modèle de base
2519393 | R+1 | AA-bois tasseau cloison | Niveau: R+1 | -0.055 | -0.23 | C-4(-1.15) | Niveau: R+2 | 3.385 | 0.426725 | 0.012186 | Groupe de modèles:POTEAUX CLOISONS R+1:2509806 | Données d'identification - Variantes: Modèle de base
2519395 | R+1 | AA-bois tasseau cloison | Niveau: R+1 | -0.055 | -0.23 | C-4(-1.65) | Niveau: R+2 | 3.385 | 0.426725 | 0.012186 | Groupe de modèles:POTEAUX CLOISONS R+1:2509806
2519397 | R+1 | AA-bois tasseau cloison | Niveau: R+1 | -0.055 | -0.23 | C-3(2.00) | Niveau: R+2 | 3.385 | 0.426725 | 0.012186 | Groupe de modèles:POTEAUX CLOISONS R+1:2509806
2519399 | R+1 | AA-bois tasseau cloison | Niveau: R+1 | -0.055 | -0.23 | C-3(1.50) | Niveau: R+2 | 3.385 | 0.426725 | 0.012186 | Groupe de modèles:POTEAUX CLOISONS R+1:2509806 | Données d'identification - Variantes: Modèle de base
2519401 | R+1 | AA-bois tasseau cloison | Niveau: R+1 | -0.055 | -0.23 | C-2(0.14) | Niveau: R+2 | 3.385 | 0.426725 | 0.012186 | Groupe de modèles:POTEAUX CLOISONS R+1:2509806
2519403 | R+1 | AA-bois tasseau cloison | Niveau: R+1 | -0.055 | -0.23 | C-3(1.00) | Niveau: R+2 | 3.385 | 0.426725 | 0.012186 | Groupe de modèles:POTEAUX CLOISONS R+1:2509806 | Données d'identification - Variantes: Modèle de base
2519405 | R+1 | AA-bois tasseau cloison | Niveau: R+1 | -0.055 | -0.23 | C-3(0.50) | Niveau: R+2 | 3.385 | 0.426725 | 0.012186 | Groupe de modèles:POTEAUX CLOISONS R+1:2509806 | Données d'identification - Variantes: Modèle de base
2519407 | R+1 | AA-bois tasseau cloison | Niveau: R+1 | -0.055 | -0.23 | C-3 | Niveau: R+2 | 3.385 | 0.426725 | 0.012186 | Groupe de modèles:POTEAUX CLOISONS R+1:2509806 | Données d'identification - Variantes: Modèle de base
2519409 | R+1 | AA-bois tasseau cloison | Niveau: R+1 | -0.055 | -0.23 | C-2(0.65) | Niveau: R+2 | 3.385 | 0.426725 | 0.012186 | Groupe de modèles:POTEAUX CLOISONS R+1:2509806 | Données d'identification - Variantes: Modèle de base
2519411 | R+1 | AA-bois tasseau cloison | Niveau: R+1 | -0.055 | -0.23 | C-2(1.15) | Niveau: R+2 | 3.385 | 0.426725 | 0.012186 | Groupe de modèles:POTEAUX CLOISONS R+1:2509806
2519413 | R+1 | AA-bois tasseau cloison | Niveau: R+1 | -0.055 | -0.23 | C-2(1.65) | Niveau: R+2 | 3.385 | 0.426725 | 0.012186 | Groupe de modèles:POTEAUX CLOISONS R+1:2509806 | Données d'identification - Variantes: Modèle de base
2519415 | R+1 | AA-bois tasseau cloison | Niveau: R+1 | -0.055 | -0.23 | C-3(-2.00) | Niveau: R+2 | 3.385 | 0.426725 | 0.012186 | Groupe de modèles:POTEAUX CLOISONS R+1:2509806
2519417 | R+1 | AA-bois tasseau cloison | Niveau: R+1 | -0.055 | -0.23 | C-3(-1.50) | Niveau: R+2 | 3.385 | 0.426725 | 0.012186 | Groupe de modèles:POTEAUX CLOISONS R+1:2509806 | Données d'identification - Variantes: Modèle de base
2519419 | R+1 | AA-bois tasseau cloison | Niveau: R+1 | -0.055 | -0.23 | C-3(-1.00) | Niveau: R+2 | 3.385 | 0.426725 | 0.012186 | Groupe de modèles:POTEAUX CLOISONS R+1:2509806
2519421 | R+1 | AA-bois tasseau cloison | Niveau: R+1 | -0.055 | -0.23 | C-3(-0.50) | Niveau: R+2 | 3.385 | 0.426725 | 0.012186 | Groupe de modèles:POTEAUX CLOISONS R+1:2509806 | Données d'identification - Variantes: Modèle de base
2519423 | R+1 | AA-bois tasseau cloison | Niveau: R+1 | -0.055 | -0.23 | B-4(-0.14) | Niveau: R+2 | 3.385 | 0.426725 | 0.012186 | Groupe de modèles:POTEAUX CLOISONS R+1:2509806
2519425 | R+1 | AA-bois tasseau cloison | Niveau: R+1 | -0.055 | -0.23 | B-4(-0.65) | Niveau: R+2 | 3.385 | 0.426725 | 0.012186 | Groupe de modèles:POTEAUX CLOISONS R+1:2509806 | Données d'identification - Variantes: Modèle de base
2519427 | R+1 | AA-bois tasseau cloison | Niveau: R+1 | -0.055 | -0.23 | B-4(-1.15) | Niveau: R+2 | 3.385 | 0.426725 | 0.012186 | Groupe de modèles:POTEAUX CLOISONS R+1:2509806 | Données d'identification - Variantes: Modèle de base
2519429 | R+1 | AA-bois tasseau cloison | Niveau: R+1 | -0.055 | -0.23 | B-4(-1.65) | Niveau: R+2 | 3.385 | 0.426725 | 0.012186 | Groupe de modèles:POTEAUX CLOISONS R+1:2509806 | Données d'identification - Variantes: Modèle de base
2519431 | R+1 | AA-bois tasseau cloison | Niveau: R+1 | -0.055 | -0.23 | B-3(2.00) | Niveau: R+2 | 3.385 | 0.426725 | 0.012186 | Groupe de modèles:POTEAUX CLOISONS R+1:2509806 | Données d'identification - Variantes: Modèle de base
2519433 | R+1 | AA-bois tasseau cloison | Niveau: R+1 | -0.055 | -0.23 | B-3(1.50) | Niveau: R+2 | 3.385 | 0.426725 | 0.012186 | Groupe de modèles:POTEAUX CLOISONS R+1:2509806 | Données d'identification - Variantes: Modèle de base
2519435 | R+1 | AA-bois tasseau cloison | Niveau: R+1 | -0.055 | -0.23 | B-2(0.14) | Niveau: R+2 | 3.385 | 0.426725 | 0.012186 | Groupe de modèles:POTEAUX CLOISONS R+1:2509806
2519437 | R+1 | AA-bois tasseau cloison | Niveau: R+1 | -0.055 | -0.23 | B(0.94)-3(1.00) | Niveau: R+2 | 3.385 | 0.426725 | 0.012186 | Groupe de modèles:POTEAUX CLOISONS R+1:2509806
2519439 | R+1 | AA-bois tasseau cloison | Niveau: R+1 | -0.055 | -0.23 | B(0.94)-3(0.50) | Niveau: R+2 | 3.385 | 0.426725 | 0.012186 | Groupe de modèles:POTEAUX CLOISONS R+1:2509806 | Données d'identification - Variantes: Modèle de base
2519441 | R+1 | AA-bois tasseau cloison | Niveau: R+1 | -0.055 | -0.23 | B(0.94)-3 | Niveau: R+2 | 3.385 | 0.426725 | 0.012186 | Groupe de modèles:POTEAUX CLOISONS R+1:2509806 | Données d'identification - Variantes: Modèle de base
2519443 | R+1 | AA-bois tasseau cloison | Niveau: R+1 | -0.055 | -0.23 | B-2(0.65) | Niveau: R+2 | 3.385 | 0.426725 | 0.012186 | Groupe de modèles:POTEAUX CLOISONS R+1:2509806 | Données d'identification - Variantes: Modèle de base
2519445 | R+1 | AA-bois tasseau cloison | Niveau: R+1 | -0.055 | -0.23 | B-2(1.15) | Niveau: R+2 | 3.385 | 0.426725 | 0.012186 | Groupe de modèles:POTEAUX CLOISONS R+1:2509806
2519447 | R+1 | AA-bois tasseau cloison | Niveau: R+1 | -0.055 | -0.23 | B-2(1.65) | Niveau: R+2 | 3.385 | 0.426725 | 0.012186 | Groupe de modèles:POTEAUX CLOISONS R+1:2509806 | Données d'identification - Variantes: Modèle de base
2519449 | R+1 | AA-bois tasseau cloison | Niveau: R+1 | -0.055 | -0.23 | B-3(-2.00) | Niveau: R+2 | 3.385 | 0.426725 | 0.012186 | Groupe de modèles:POTEAUX CLOISONS R+1:2509806 | Données d'identification - Variantes: Modèle de base
2519451 | R+1 | AA-bois tasseau cloison | Niveau: R+1 | -0.055 | -0.23 | B-3(-1.50) | Niveau: R+2 | 3.385 | 0.426725 | 0.012186 | Groupe de modèles:POTEAUX CLOISONS R+1:2509806 | Données d'identification - Variantes: Modèle de base
2519453 | R+1 | AA-bois tasseau cloison | Niveau: R+1 | -0.055 | -0.23 | B(0.94)-3(-1.00) | Niveau: R+2 | 3.385 | 0.426725 | 0.012186 | Groupe de modèles:POTEAUX CLOISONS R+1:2509806
2519455 | R+1 | AA-bois tasseau cloison | Niveau: R+1 | -0.055 | -0.23 | B(0.94)-3(-0.50) | Niveau: R+2 | 3.385 | 0.426725 | 0.012186 | Groupe de modèles:POTEAUX CLOISONS R+1:2509806
2519457 | R+1 | AA-bois tasseau cloison | Niveau: R+1 | -0.055 | -0.23 | D(0.06)-3 | Niveau: R+2 | 3.385 | 0.426725 | 0.012186 | Groupe de modèles:POTEAUX CLOISONS R+1:2509806 | Données d'identification - Variantes: Modèle de base
2519459 | R+1 | AA-bois tasseau cloison | Niveau: R+1 | -0.055 | -0.23 | D(0.50)-3 | Niveau: R+2 | 3.385 | 0.426725 | 0.012186 | Groupe de modèles:POTEAUX CLOISONS R+1:2509806 | Données d'identification - Variantes: Modèle de base
2519461 | R+1 | AA-bois tasseau cloison | Niveau: R+1 | -0.055 | -0.23 | D(1.00)-3 | Niveau: R+2 | 3.385 | 0.426725 | 0.012186 | Groupe de modèles:POTEAUX CLOISONS R+1:2509806
2519463 | R+1 | AA-bois tasseau cloison | Niveau: R+1 | -0.055 | -0.23 | D(1.50)-3 | Niveau: R+2 | 3.385 | 0.426725 | 0.012186 | Groupe de modèles:POTEAUX CLOISONS R+1:2509806
2519465 | R+1 | AA-bois tasseau cloison | Niveau: R+1 | -0.055 | -0.23 | D(2.00)-3 | Niveau: R+2 | 3.385 | 0.426725 | 0.012186 | Groupe de modèles:POTEAUX CLOISONS R+1:2509806 | Données d'identification - Variantes: Modèle de base
2519467 | R+1 | AA-bois tasseau cloison | Niveau: R+1 | -0.055 | -0.23 | E(-1.50)-3 | Niveau: R+2 | 3.385 | 0.426725 | 0.012186 | Groupe de modèles:POTEAUX CLOISONS R+1:2509806
2519469 | R+1 | AA-bois tasseau cloison | Niveau: R+1 | -0.055 | -0.23 | E(-1.00)-3 | Niveau: R+2 | 3.385 | 0.426725 | 0.012186 | Groupe de modèles:POTEAUX CLOISONS R+1:2509806
2519471 | R+1 | AA-bois tasseau cloison | Niveau: R+1 | -0.055 | -0.23 | E(-0.63)-3 | Niveau: R+2 | 3.385 | 0.426725 | 0.012186 | Groupe de modèles:POTEAUX CLOISONS R+1:2509806
2522079 | R+2 | AA-bois tasseau cloison | Niveau: R+2 | -0.09 | -0.31 | G-3(-0.73) | Niveau: Toiture | 3 | 0.3786 | 0.0108 | Groupe de modèles:POTEAUX CLOISONS R+2:2514951 | Données d'identification - Variantes: Modèle de base
2522081 | R+2 | AA-bois tasseau cloison | Niveau: R+2 | -0.09 | -0.31 | G-3(-1.25) | Niveau: Toiture | 3 | 0.3786 | 0.0108 | Groupe de modèles:POTEAUX CLOISONS R+2:2514951
2522112 | R+2 | AA-bois tasseau cloison | Niveau: R+2 | -0.09 | -0.31 | G-3(0.29) | Niveau: Toiture | 3 | 0.3786 | 0.0108 | Groupe de modèles:POTEAUX CLOISONS R+2:2514951
2522114 | R+2 | AA-bois tasseau cloison | Niveau: R+2 | -0.09 | -0.31 | G-3(-0.23) | Niveau: Toiture | 3 | 0.3786 | 0.0108 | Groupe de modèles:POTEAUX CLOISONS R+2:2514951 | Données d'identification - Variantes: Modèle de base
2522137 | R+2 | AA-bois tasseau cloison | Niveau: R+2 | -0.09 | -0.31 | G-3(1.32) | Niveau: Toiture | 3 | 0.3786 | 0.0108 | Groupe de modèles:POTEAUX CLOISONS R+2:2514951 | Données d'identification - Variantes: Modèle de base
2522139 | R+2 | AA-bois tasseau cloison | Niveau: R+2 | -0.09 | -0.31 | G-3(0.79) | Niveau: Toiture | 3 | 0.3786 | 0.0108 | Groupe de modèles:POTEAUX CLOISONS R+2:2514951 | Données d'identification - Variantes: Modèle de base
2522166 | R+2 | AA-bois tasseau cloison | Niveau: R+2 | -0.09 | -0.31 | G-4(-1.81) | Niveau: Toiture | 3 | 0.3786 | 0.0108 | Groupe de modèles:POTEAUX CLOISONS R+2:2514951
2522168 | R+2 | AA-bois tasseau cloison | Niveau: R+2 | -0.09 | -0.31 | G-3(1.82) | Niveau: Toiture | 3 | 0.3786 | 0.0108 | Groupe de modèles:POTEAUX CLOISONS R+2:2514951
2522390 | R+2 | AA-bois tasseau cloison | Niveau: R+2 | -0.09 | -0.31 | I-3 | Niveau: Toiture | 3 | 0.3786 | 0.0108 | Groupe de modèles:POTEAUX CLOISONS R+2:2514951
2522392 | R+2 | AA-bois tasseau cloison | Niveau: R+2 | -0.09 | -0.31 | I-3(0.50) | Niveau: Toiture | 3 | 0.3786 | 0.0108 | Groupe de modèles:POTEAUX CLOISONS R+2:2514951 | Données d'identification - Variantes: Modèle de base
2522394 | R+2 | AA-bois tasseau cloison | Niveau: R+2 | -0.09 | -0.31 | I-3(1.00) | Niveau: Toiture | 3 | 0.3786 | 0.0108 | Groupe de modèles:POTEAUX CLOISONS R+2:2514951
2522396 | R+2 | AA-bois tasseau cloison | Niveau: R+2 | -0.09 | -0.31 | I-3(1.50) | Niveau: Toiture | 3 | 0.3786 | 0.0108 | Groupe de modèles:POTEAUX CLOISONS R+2:2514951
2522398 | R+2 | AA-bois tasseau cloison | Niveau: R+2 | -0.09 | -0.31 | I-3(2.00) | Niveau: Toiture | 3 | 0.3786 | 0.0108 | Groupe de modèles:POTEAUX CLOISONS R+2:2514951 | Données d'identification - Variantes: Modèle de base
2522400 | R+2 | AA-bois tasseau cloison | Niveau: R+2 | -0.09 | -0.31 | I-4(-1.65) | Niveau: Toiture | 3 | 0.3786 | 0.0108 | Groupe de modèles:POTEAUX CLOISONS R+2:2514951 | Données d'identification - Variantes: Modèle de base
2522402 | R+2 | AA-bois tasseau cloison | Niveau: R+2 | -0.09 | -0.31 | I-2(0.14) | Niveau: Toiture | 3 | 0.3786 | 0.0108 | Groupe de modèles:POTEAUX CLOISONS R+2:2514951
2522404 | R+2 | AA-bois tasseau cloison | Niveau: R+2 | -0.09 | -0.31 | I-3(-0.50) | Niveau: Toiture | 3 | 0.3786 | 0.0108 | Groupe de modèles:POTEAUX CLOISONS R+2:2514951
2522406 | R+2 | AA-bois tasseau cloison | Niveau: R+2 | -0.09 | -0.31 | I-3(-1.00) | Niveau: Toiture | 3 | 0.3786 | 0.0108 | Groupe de modèles:POTEAUX CLOISONS R+2:2514951 | Données d'identification - Variantes: Modèle de base
2522408 | R+2 | AA-bois tasseau cloison | Niveau: R+2 | -0.09 | -0.31 | I-3(-1.50) | Niveau: Toiture | 3 | 0.3786 | 0.0108 | Groupe de modèles:POTEAUX CLOISONS R+2:2514951 | Données d'identification - Variantes: Modèle de base
2522410 | R+2 | AA-bois tasseau cloison | Niveau: R+2 | -0.09 | -0.31 | I-3(-2.00) | Niveau: Toiture | 3 | 0.3786 | 0.0108 | Groupe de modèles:POTEAUX CLOISONS R+2:2514951
2522412 | R+2 | AA-bois tasseau cloison | Niveau: R+2 | -0.09 | -0.31 | I-2(1.65) | Niveau: Toiture | 3 | 0.3786 | 0.0108 | Groupe de modèles:POTEAUX CLOISONS R+2:2514951 | Données d'identification - Variantes: Modèle de base
2522414 | R+2 | AA-bois tasseau cloison | Niveau: R+2 | -0.09 | -0.31 | I-4(-0.14) | Niveau: Toiture | 3 | 0.3786 | 0.0108 | Groupe de modèles:POTEAUX CLOISONS R+2:2514951 | Données d'identification - Variantes: Modèle de base
2522416 | R+2 | AA-bois tasseau cloison | Niveau: R+2 | -0.09 | -0.31 | I-4(-1.37) | Niveau: Toiture | 3 | 0.3786 | 0.0108 | Groupe de modèles:POTEAUX CLOISONS R+2:2514951
2522418 | R+2 | AA-bois tasseau cloison | Niveau: R+2 | -0.09 | -0.31 | I-4(-0.33) | Niveau: Toiture | 3 | 0.3786 | 0.0108 | Groupe de modèles:POTEAUX CLOISONS R+2:2514951
2522420 | R+2 | AA-bois tasseau cloison | Niveau: R+2 | -0.09 | -0.31 | I-2(1.15) | Niveau: Toiture | 3 | 0.3786 | 0.0108 | Groupe de modèles:POTEAUX CLOISONS R+2:2514951 | Données d'identification - Variantes: Modèle de base
2522422 | R+2 | AA-bois tasseau cloison | Niveau: R+2 | -0.09 | -0.31 | I-2(0.65) | Niveau: Toiture | 3 | 0.3786 | 0.0108 | Groupe de modèles:POTEAUX CLOISONS R+2:2514951
2524199 | RDC | AA-bois tasseau cloison | Niveau: RDC | -0.055 | -0.94 | G-3(-1.30) | Niveau: R+1 | 3.385 | 0.426725 | 0.012186 | Groupe de modèles:POTEAUX CLOISONS RDC (membre exclu):1442762 | Données d'identification - Variantes: Modèle de base
2524238 | RDC | AA-bois tasseau cloison | Niveau: RDC | -0.055 | -0.94 | G(1.89)-3(-1.36) | Niveau: R+1 | 3.385 | 0.426725 | 0.012186 | Groupe de modèles:POTEAUX CLOISONS RDC (membre exclu):1442762
2524240 | RDC | AA-bois tasseau cloison | Niveau: RDC | -0.055 | -0.94 | G(1.39)-3(-1.36) | Niveau: R+1 | 3.385 | 0.426725 | 0.012186 | Groupe de modèles:POTEAUX CLOISONS RDC (membre exclu):1442762 | Données d'identification - Variantes: Modèle de base
2524242 | RDC | AA-bois tasseau cloison | Niveau: RDC | -0.055 | -0.94 | G(0.89)-3(-1.36) | Niveau: R+1 | 3.385 | 0.426725 | 0.012186 | Groupe de modèles:POTEAUX CLOISONS RDC (membre exclu):1442762 | Données d'identification - Variantes: Modèle de base
2524244 | RDC | AA-bois tasseau cloison | Niveau: RDC | -0.055 | -0.94 | G(0.39)-3(-1.36) | Niveau: R+1 | 3.385 | 0.426725 | 0.012186 | Groupe de modèles:POTEAUX CLOISONS RDC (membre exclu):1442762
2524281 | RDC | AA-bois tasseau cloison | Niveau: RDC | -0.055 | -0.94 | H(-0.07)-3(-1.36) | Niveau: R+1 | 3.385 | 0.426725 | 0.012186 | Groupe de modèles:POTEAUX CLOISONS RDC (membre exclu):1442762 | Données d'identification - Variantes: Modèle de base
2524285 | RDC | AA-bois tasseau cloison | Niveau: RDC | -0.055 | -0.94 | H(-1.11)-3(-1.36) | Niveau: R+1 | 3.385 | 0.426725 | 0.012186 | Groupe de modèles:POTEAUX CLOISONS RDC (membre exclu):1442762 | Données d'identification - Variantes: Modèle de base
2524287 | RDC | AA-bois tasseau cloison | Niveau: RDC | -0.055 | -0.94 | H(-1.61)-3(-1.36) | Niveau: R+1 | 3.385 | 0.426725 | 0.012186 | Groupe de modèles:POTEAUX CLOISONS RDC (membre exclu):1442762
2563670 | R+1 | AA-bois tasseau cloison | Niveau: R+1 | -0.055 | -0.23 | B(0.94)-3(-1.38) | Niveau: R+2 | 3.385 | 0.426725 | 0.012186 | Groupe de modèles:POTEAUX CLOISONS R+1:2509806
2563709 | R+1 | AA-bois tasseau cloison | Niveau: R+1 | -0.055 | -0.23 | B(0.88)-3(-1.44) | Niveau: R+2 | 3.385 | 0.426725 | 0.012186 | Groupe de modèles:POTEAUX CLOISONS R+1:2509806 | Données d'identification - Variantes: Modèle de base
2563744 | R+1 | AA-bois tasseau cloison | Niveau: R+1 | -0.055 | -0.23 | B-3(-1.44) | Niveau: R+2 | 3.385 | 0.426725 | 0.012186 | Groupe de modèles:POTEAUX CLOISONS R+1:2509806
2563777 | R+1 | AA-bois tasseau cloison | Niveau: R+1 | -0.055 | -0.23 | B(0.50)-3(-1.44) | Niveau: R+2 | 3.385 | 0.426725 | 0.012186 | Groupe de modèles:POTEAUX CLOISONS R+1:2509806 | Données d'identification - Variantes: Modèle de base
2563808 | R+1 | AA-bois tasseau cloison | Niveau: R+1 | -0.055 | -0.23 | B(-0.88)-3(-1.44) | Niveau: R+2 | 3.385 | 0.426725 | 0.012186 | Groupe de modèles:POTEAUX CLOISONS R+1:2509806 | Données d'identification - Variantes: Modèle de base
2563810 | R+1 | AA-bois tasseau cloison | Niveau: R+1 | -0.055 | -0.23 | B(-0.50)-3(-1.44) | Niveau: R+2 | 3.385 | 0.426725 | 0.012186 | Groupe de modèles:POTEAUX CLOISONS R+1:2509806 | Données d'identification - Variantes: Modèle de base
2563836 | R+1 | AA-bois tasseau cloison | Niveau: R+1 | -0.055 | -0.23 | B(-0.94)-3(-1.38) | Niveau: R+2 | 3.385 | 0.426725 | 0.012186 | Groupe de modèles:POTEAUX CLOISONS R+1:2509806 | Données d'identification - Variantes: Modèle de base
2563858 | R+1 | AA-bois tasseau cloison | Niveau: R+1 | -0.055 | -0.23 | B(0.94)-3(1.38) | Niveau: R+2 | 3.385 | 0.426725 | 0.012186 | Groupe de modèles:POTEAUX CLOISONS R+1:2509806
2563860 | R+1 | AA-bois tasseau cloison | Niveau: R+1 | -0.055 | -0.23 | B(0.88)-3(1.44) | Niveau: R+2 | 3.385 | 0.426725 | 0.012186 | Groupe de modèles:POTEAUX CLOISONS R+1:2509806 | Données d'identification - Variantes: Modèle de base
2563862 | R+1 | AA-bois tasseau cloison | Niveau: R+1 | -0.055 | -0.23 | B-3(1.44) | Niveau: R+2 | 3.385 | 0.426725 | 0.012186 | Groupe de modèles:POTEAUX CLOISONS R+1:2509806
2563864 | R+1 | AA-bois tasseau cloison | Niveau: R+1 | -0.055 | -0.23 | B(0.50)-3(1.44) | Niveau: R+2 | 3.385 | 0.426725 | 0.012186 | Groupe de modèles:POTEAUX CLOISONS R+1:2509806
2563866 | R+1 | AA-bois tasseau cloison | Niveau: R+1 | -0.055 | -0.23 | B(-0.88)-3(1.44) | Niveau: R+2 | 3.385 | 0.426725 | 0.012186 | Groupe de modèles:POTEAUX CLOISONS R+1:2509806 | Données d'identification - Variantes: Modèle de base
2563868 | R+1 | AA-bois tasseau cloison | Niveau: R+1 | -0.055 | -0.23 | B(-0.50)-3(1.44) | Niveau: R+2 | 3.385 | 0.426725 | 0.012186 | Groupe de modèles:POTEAUX CLOISONS R+1:2509806
2563870 | R+1 | AA-bois tasseau cloison | Niveau: R+1 | -0.055 | -0.23 | B(-0.94)-3(1.38) | Niveau: R+2 | 3.385 | 0.426725 | 0.012186 | Groupe de modèles:POTEAUX CLOISONS R+1:2509806 | Données d'identification - Variantes: Modèle de base
2563922 | R+1 | AA-bois tasseau cloison | Niveau: R+1 | -0.055 | -0.23 | B(-0.94)-3(0.33) | Niveau: R+2 | 3.385 | 0.426725 | 0.012186 | Groupe de modèles:POTEAUX CLOISONS R+1:2509806
2563924 | R+1 | AA-bois tasseau cloison | Niveau: R+1 | -0.055 | -0.23 | B(-0.94)-3 | Niveau: R+2 | 3.385 | 0.426725 | 0.012186 | Groupe de modèles:POTEAUX CLOISONS R+1:2509806 | Données d'identification - Variantes: Modèle de base
2563926 | R+1 | AA-bois tasseau cloison | Niveau: R+1 | -0.055 | -0.23 | B(-0.94)-3(-1.00) | Niveau: R+2 | 3.385 | 0.426725 | 0.012186 | Groupe de modèles:POTEAUX CLOISONS R+1:2509806
2563928 | R+1 | AA-bois tasseau cloison | Niveau: R+1 | -0.055 | -0.23 | B(-0.94)-3(-0.50) | Niveau: R+2 | 3.385 | 0.426725 | 0.012186 | Groupe de modèles:POTEAUX CLOISONS R+1:2509806 | Données d'identification - Variantes: Modèle de base
2566318 | R+2 | AA-bois tasseau cloison | Niveau: R+2 | -0.09 | -0.31 | H-3 | Niveau: Toiture | 3 | 0.3786 | 0.0108 | Groupe de modèles:POTEAUX CLOISONS R+2:2514951 | Données d'identification - Variantes: Modèle de base
2566320 | R+2 | AA-bois tasseau cloison | Niveau: R+2 | -0.09 | -0.31 | H-3(0.50) | Niveau: Toiture | 3 | 0.3786 | 0.0108 | Groupe de modèles:POTEAUX CLOISONS R+2:2514951 | Données d'identification - Variantes: Modèle de base
2566322 | R+2 | AA-bois tasseau cloison | Niveau: R+2 | -0.09 | -0.31 | H-3(1.00) | Niveau: Toiture | 3 | 0.3786 | 0.0108 | Groupe de modèles:POTEAUX CLOISONS R+2:2514951
2566324 | R+2 | AA-bois tasseau cloison | Niveau: R+2 | -0.09 | -0.31 | H-3(1.50) | Niveau: Toiture | 3 | 0.3786 | 0.0108 | Groupe de modèles:POTEAUX CLOISONS R+2:2514951 | Données d'identification - Variantes: Modèle de base
2566326 | R+2 | AA-bois tasseau cloison | Niveau: R+2 | -0.09 | -0.31 | H-3(2.00) | Niveau: Toiture | 3 | 0.3786 | 0.0108 | Groupe de modèles:POTEAUX CLOISONS R+2:2514951
2566328 | R+2 | AA-bois tasseau cloison | Niveau: R+2 | -0.09 | -0.31 | H-4(-1.65) | Niveau: Toiture | 3 | 0.3786 | 0.0108 | Groupe de modèles:POTEAUX CLOISONS R+2:2514951 | Données d'identification - Variantes: Modèle de base
2566330 | R+2 | AA-bois tasseau cloison | Niveau: R+2 | -0.09 | -0.31 | H-2(0.14) | Niveau: Toiture | 3 | 0.3786 | 0.0108 | Groupe de modèles:POTEAUX CLOISONS R+2:2514951 | Données d'identification - Variantes: Modèle de base
2566332 | R+2 | AA-bois tasseau cloison | Niveau: R+2 | -0.09 | -0.31 | H-3(-0.50) | Niveau: Toiture | 3 | 0.3786 | 0.0108 | Groupe de modèles:POTEAUX CLOISONS R+2:2514951 | Données d'identification - Variantes: Modèle de base
2566334 | R+2 | AA-bois tasseau cloison | Niveau: R+2 | -0.09 | -0.31 | H-3(-1.00) | Niveau: Toiture | 3 | 0.3786 | 0.0108 | Groupe de modèles:POTEAUX CLOISONS R+2:2514951 | Données d'identification - Variantes: Modèle de base
2566336 | R+2 | AA-bois tasseau cloison | Niveau: R+2 | -0.09 | -0.31 | H-3(-1.50) | Niveau: Toiture | 3 | 0.3786 | 0.0108 | Groupe de modèles:POTEAUX CLOISONS R+2:2514951 | Données d'identification - Variantes: Modèle de base
2566338 | R+2 | AA-bois tasseau cloison | Niveau: R+2 | -0.09 | -0.31 | H-3(-2.00) | Niveau: Toiture | 3 | 0.3786 | 0.0108 | Groupe de modèles:POTEAUX CLOISONS R+2:2514951 | Données d'identification - Variantes: Modèle de base
2566340 | R+2 | AA-bois tasseau cloison | Niveau: R+2 | -0.09 | -0.31 | H-2(1.65) | Niveau: Toiture | 3 | 0.3786 | 0.0108 | Groupe de modèles:POTEAUX CLOISONS R+2:2514951
2566342 | R+2 | AA-bois tasseau cloison | Niveau: R+2 | -0.09 | -0.31 | H-4(-0.14) | Niveau: Toiture | 3 | 0.3786 | 0.0108 | Groupe de modèles:POTEAUX CLOISONS R+2:2514951 | Données d'identification - Variantes: Modèle de base
2566344 | R+2 | AA-bois tasseau cloison | Niveau: R+2 | -0.09 | -0.31 | H-4(-1.37) | Niveau: Toiture | 3 | 0.3786 | 0.0108 | Groupe de modèles:POTEAUX CLOISONS R+2:2514951
2566346 | R+2 | AA-bois tasseau cloison | Niveau: R+2 | -0.09 | -0.31 | H-4(-0.33) | Niveau: Toiture | 3 | 0.3786 | 0.0108 | Groupe de modèles:POTEAUX CLOISONS R+2:2514951
2566348 | R+2 | AA-bois tasseau cloison | Niveau: R+2 | -0.09 | -0.31 | H-2(1.15) | Niveau: Toiture | 3 | 0.3786 | 0.0108 | Groupe de modèles:POTEAUX CLOISONS R+2:2514951
2566350 | R+2 | AA-bois tasseau cloison | Niveau: R+2 | -0.09 | -0.31 | H-2(0.65) | Niveau: Toiture | 3 | 0.3786 | 0.0108 | Groupe de modèles:POTEAUX CLOISONS R+2:2514951
2591712 | R+1 | AA-bois tasseau cloison | Niveau: R+1 | -0.055 | -0.23 | G(-0.06)-3(-0.60) | Niveau: R+2 | 3.385 | 0.426725 | 0.012186 | Groupe de modèles:POTEAUX CLOISONS R+1:2509806 | Données d'identification - Variantes: Modèle de base
2591714 | R+1 | AA-bois tasseau cloison | Niveau: R+1 | -0.055 | -0.23 | G(-0.56)-3(-0.60) | Niveau: R+2 | 3.385 | 0.426725 | 0.012186 | Groupe de modèles:POTEAUX CLOISONS R+1:2509806
2591716 | R+1 | AA-bois tasseau cloison | Niveau: R+1 | -0.055 | -0.23 | G(-1.06)-3(-0.60) | Niveau: R+2 | 3.385 | 0.426725 | 0.012186 | Groupe de modèles:POTEAUX CLOISONS R+1:2509806 | Données d'identification - Variantes: Modèle de base
2591718 | R+1 | AA-bois tasseau cloison | Niveau: R+1 | -0.055 | -0.23 | G(-1.56)-3(-0.60) | Niveau: R+2 | 3.385 | 0.426725 | 0.012186 | Groupe de modèles:POTEAUX CLOISONS R+1:2509806
2591720 | R+1 | AA-bois tasseau cloison | Niveau: R+1 | -0.055 | -0.23 | F(1.94)-3(-0.60) | Niveau: R+2 | 3.385 | 0.426725 | 0.012186 | Groupe de modèles:POTEAUX CLOISONS R+1:2509806 | Données d'identification - Variantes: Modèle de base
2591722 | R+1 | AA-bois tasseau cloison | Niveau: R+1 | -0.055 | -0.23 | F(1.44)-3(-0.60) | Niveau: R+2 | 3.385 | 0.426725 | 0.012186 | Groupe de modèles:POTEAUX CLOISONS R+1:2509806 | Données d'identification - Variantes: Modèle de base
2591724 | R+1 | AA-bois tasseau cloison | Niveau: R+1 | -0.055 | -0.23 | F(0.94)-3(-0.60) | Niveau: R+2 | 3.385 | 0.426725 | 0.012186 | Groupe de modèles:POTEAUX CLOISONS R+1:2509806 | Données d'identification - Variantes: Modèle de base
2591726 | R+1 | AA-bois tasseau cloison | Niveau: R+1 | -0.055 | -0.23 | F(0.44)-3(-0.60) | Niveau: R+2 | 3.385 | 0.426725 | 0.012186 | Groupe de modèles:POTEAUX CLOISONS R+1:2509806 | Données d'identification - Variantes: Modèle de base
2591728 | R+1 | AA-bois tasseau cloison | Niveau: R+1 | -0.055 | -0.23 | F(-0.04)-3(-0.60) | Niveau: R+2 | 3.385 | 0.426725 | 0.012186 | Groupe de modèles:POTEAUX CLOISONS R+1:2509806
2592626 | R+2 | AA-bois tasseau cloison | Niveau: R+2 | -0.09 | -0.31 | G(-0.06)-3(-0.60) | Niveau: Toiture | 3 | 0.3786 | 0.0108 | Groupe de modèles:POTEAUX CLOISONS R+2:2514951
2592628 | R+2 | AA-bois tasseau cloison | Niveau: R+2 | -0.09 | -0.31 | G(-0.56)-3(-0.60) | Niveau: Toiture | 3 | 0.3786 | 0.0108 | Groupe de modèles:POTEAUX CLOISONS R+2:2514951
2592630 | R+2 | AA-bois tasseau cloison | Niveau: R+2 | -0.09 | -0.31 | G(-1.06)-3(-0.60) | Niveau: Toiture | 3 | 0.3786 | 0.0108 | Groupe de modèles:POTEAUX CLOISONS R+2:2514951 | Données d'identification - Variantes: Modèle de base
2592632 | R+2 | AA-bois tasseau cloison | Niveau: R+2 | -0.09 | -0.31 | G(-1.56)-3(-0.60) | Niveau: Toiture | 3 | 0.3786 | 0.0108 | Groupe de modèles:POTEAUX CLOISONS R+2:2514951 | Données d'identification - Variantes: Modèle de base
2592634 | R+2 | AA-bois tasseau cloison | Niveau: R+2 | -0.09 | -0.31 | F(1.94)-3(-0.60) | Niveau: Toiture | 3 | 0.3786 | 0.0108 | Groupe de modèles:POTEAUX CLOISONS R+2:2514951 | Données d'identification - Variantes: Modèle de base
2592636 | R+2 | AA-bois tasseau cloison | Niveau: R+2 | -0.09 | -0.31 | F(1.44)-3(-0.60) | Niveau: Toiture | 3 | 0.3786 | 0.0108 | Groupe de modèles:POTEAUX CLOISONS R+2:2514951 | Données d'identification - Variantes: Modèle de base
2592638 | R+2 | AA-bois tasseau cloison | Niveau: R+2 | -0.09 | -0.31 | F(0.94)-3(-0.60) | Niveau: Toiture | 3 | 0.3786 | 0.0108 | Groupe de modèles:POTEAUX CLOISONS R+2:2514951 | Données d'identification - Variantes: Modèle de base
2592640 | R+2 | AA-bois tasseau cloison | Niveau: R+2 | -0.09 | -0.31 | F(0.44)-3(-0.60) | Niveau: Toiture | 3 | 0.3786 | 0.0108 | Groupe de modèles:POTEAUX CLOISONS R+2:2514951 | Données d'identification - Variantes: Modèle de base
2592642 | R+2 | AA-bois tasseau cloison | Niveau: R+2 | -0.09 | -0.31 | F(-0.05)-3(-0.60) | Niveau: Toiture | 3 | 0.3786 | 0.0108 | Groupe de modèles:POTEAUX CLOISONS R+2:2514951 | Données d'identification - Variantes: Modèle de base
2677009 | RDC | AA-bois tasseau cloison | Niveau: RDC | -0.055 | -0.92 | D(-0.14)-3(2.02) | Niveau: R+1 | 3.405 | 0.429225 | 0.012258 | Groupe de modèles:PORTE MUR COULISSANT:2677156 | Pset_ColumnCommon - Slope: 0 deg; Données d'identification - Variantes: Modèle de base
2677055 | RDC | AA-bois tasseau cloison | Niveau: RDC | -0.055 | -0.92 | D(-0.14)-3(0.48) | Niveau: R+1 | 3.405 | 0.429225 | 0.012258 | Groupe de modèles:PORTE MUR COULISSANT:2677156
2677098 | RDC | AA-bois tasseau cloison | Niveau: RDC | -0.055 | -0.92 | D(-0.14)-3(0.99) | Niveau: R+1 | 3.405 | 0.429225 | 0.012258 | Groupe de modèles:PORTE MUR COULISSANT:2677156
2677131 | RDC | AA-bois tasseau cloison | Niveau: RDC | -0.055 | -0.92 | D(-0.14)-3(1.51) | Niveau: R+1 | 3.405 | 0.429225 | 0.012258 | Groupe de modèles:PORTE MUR COULISSANT:2677156
2677408 | RDC | AA-bois tasseau cloison | Niveau: RDC | -0.055 | -0.92 | D(-0.14)-2(1.33) | Niveau: R+1 | 3.405 | 0.429225 | 0.012258 | Groupe de modèles:PORTE MUR COULISSANT:2677416 | Pset_ColumnCommon - Slope: 0 deg
2677410 | RDC | AA-bois tasseau cloison | Niveau: RDC | -0.055 | -0.92 | D(-0.14)-3(-1.28) | Niveau: R+1 | 3.405 | 0.429225 | 0.012258 | Groupe de modèles:PORTE MUR COULISSANT:2677416 | Données d'identification - Variantes: Modèle de base
2677412 | RDC | AA-bois tasseau cloison | Niveau: RDC | -0.055 | -0.92 | D(-0.14)-3(-1.79) | Niveau: R+1 | 3.405 | 0.429225 | 0.012258 | Groupe de modèles:PORTE MUR COULISSANT:2677416 | Données d'identification - Variantes: Modèle de base
2677414 | RDC | AA-bois tasseau cloison | Niveau: RDC | -0.055 | -0.92 | D(-0.14)-2(1.84) | Niveau: R+1 | 3.405 | 0.429225 | 0.012258 | Groupe de modèles:PORTE MUR COULISSANT:2677416 | Données d'identification - Variantes: Modèle de base
2757907 | R+1 | AA-bois tasseau cloison | Niveau: R+1 | -0.055 | -0.23 | J(0.06)-3 | Niveau: R+2 | 3.385 | 0.426725 | 0.012186 | Groupe de modèles:POTEAUX CLOISONS R+1:2509806 | Données d'identification - Variantes: Modèle de base
2757965 | R+1 | AA-bois tasseau cloison | Niveau: R+1 | -0.055 | -0.23 | J(0.14)-3 | Niveau: R+2 | 3.385 | 0.426725 | 0.012186 | Groupe de modèles:POTEAUX CLOISONS R+1:2509806
2758017 | R+1 | AA-bois tasseau cloison | Niveau: R+1 | -0.055 | -0.23 | J(1.44)-3 | Niveau: R+2 | 3.385 | 0.426725 | 0.012186 | Groupe de modèles:POTEAUX CLOISONS R+1:2509806 | Données d'identification - Variantes: Modèle de base
2758036 | R+1 | AA-bois tasseau cloison | Niveau: R+1 | -0.055 | -0.23 | J(1.94)-3 | Niveau: R+2 | 3.385 | 0.426725 | 0.012186 | Groupe de modèles:POTEAUX CLOISONS R+1:2509806
2758053 | R+1 | AA-bois tasseau cloison | Niveau: R+1 | -0.055 | -0.23 | K(-1.56)-3 | Niveau: R+2 | 3.385 | 0.426725 | 0.012186 | Groupe de modèles:POTEAUX CLOISONS R+1:2509806 | Données d'identification - Variantes: Modèle de base
2758072 | R+1 | AA-bois tasseau cloison | Niveau: R+1 | -0.055 | -0.23 | K(-1.06)-3 | Niveau: R+2 | 3.385 | 0.426725 | 0.012186 | Groupe de modèles:POTEAUX CLOISONS R+1:2509806
2758089 | R+1 | AA-bois tasseau cloison | Niveau: R+1 | -0.055 | -0.23 | K(-0.56)-3 | Niveau: R+2 | 3.385 | 0.426725 | 0.012186 | Groupe de modèles:POTEAUX CLOISONS R+1:2509806 | Données d'identification - Variantes: Modèle de base
2759058 | R+1 | AA-bois tasseau cloison | Niveau: R+1 | -0.055 | -0.23 | K(-0.06)-3 | Niveau: R+2 | 3.385 | 0.426725 | 0.012186 | Groupe de modèles:POTEAUX CLOISONS R+1:2509806
2759123 | R+1 | AA-bois tasseau cloison | Niveau: R+1 | -0.055 | -0.23 | J(1.19)-3 | Niveau: R+2 | 3.385 | 0.426725 | 0.012186 | Groupe de modèles:POTEAUX CLOISONS R+1:2509806 | Données d'identification - Variantes: Modèle de base

# IfcDoor: 1.4m x 2.1m, Coulissante - Apparente:1.4m x 2.1m:1643670
In: R+2
Type - OperationType: SLIDING_TO_RIGHT; ParameterTakesPrecedence: no; Sizeable: no; Material: Porte - Poignée, AA-Aluminium, AA-vitrage
Type - Coulissante - Apparente:1.4m x 2.1m:1643670 - PanelOperation: SLIDING
Type - Autre - Catégorie: Portes; Nom de la famille: Coulissante - Apparente
Type - Construction - Fonction: Extérieur; Fermeture du mur: Les deux
Type - Cotes - Epaisseur: 0.02 m; Hauteur: 2.1 m; Hauteur de la poignée: 0.9 m; Largeur: 1.4 m; Largeur du cadre: 0.015 m; Retour: 0.02 m
Type - Données d'identification - Marque de type: 39; Nom du type: 1.4m x 2.1m; Sous-projet: Famille : Portes : Coulissante - Apparente
Type - Matériaux et finitions - Dormants: AA-Aluminium; Panneaux: AA-vitrage; Poignée: Porte - Poignée
Type - Propriétés analytiques - Coefficient d'apport thermique solaire: 0; Transmission de la lumière visible: 0; Coefficient de transfert de chaleur (U): 3.7021; Construction analytique: Métal; Résistance thermique (R): 0.270117
OverallHeight: 2.1 m; OverallWidth: 1.43 m
Pset_DoorCommon - IsExternal: yes; Reference: Coulissante - Apparente:1.4m x 2.1m; ThermalTransmittance: 3.7021 kg/K/s3
Autre - ID hôte: Mur de base: A-prémur BTC; Famille: Coulissante - Apparente: 1.4m x 2.1m; Famille et type: Coulissante - Apparente: 1.4m x 2.1m; Hauteur sous linteau: 2.1 m; ID du type: Coulissante - Apparente: 1.4m x 2.1m; Type: Coulissante - Apparente: 1.4m x 2.1m
Contraintes - Niveau: Niveau: R+2; Hauteur de l'appui: 0 m
Cotes - Surface: 4.72137 m2; Volume: 0.08541 m3
Données d'identification - Sous-projet: Menuiseries INT; Identifiant: 129
Phase de construction - Phase de création: Nouvelle construction

# IfcDoor: Garage sectionnelle, Garage sectionnelle:Garage sectionnelle:954205
In: R-1
Type - OperationType: ROLLINGUP; ParameterTakesPrecedence: no; Sizeable: no; Material: Plastique - Noir, AA-Aluminium, Verre
Type - Garage sectionnelle:Garage sectionnelle:954205 - PanelOperation: ROLLINGUP
Type - Autre - Catégorie: Portes; Nom de la famille: Garage sectionnelle
Type - Construction - Fonction: Extérieur; Fermeture du mur: Par hôte
Type - Cotes - Hauteur: 2.8 m; Hauteur de la poignée: 0.5 m; Largeur: 3 m; Largeur du cadre: 0.06 m
Type - Données d'identification - Marque de type: 33; Nom du type: Garage sectionnelle; Sous-projet: Famille : Portes : Garage sectionnelle
Type - Matériaux et finitions - Image: AA-Aluminium; Panneau: AA-Aluminium; Poignée: Plastique - Noir
Type - Propriétés analytiques - Coefficient d'apport thermique solaire: 0; Coefficient de transfert de chaleur (U): 3.7021; Construction analytique: Métal; Résistance thermique (R): 0.270117; Transmission de la lumière visible: 0
OverallHeight: 2.86 m; OverallWidth: 3.12 m
Pset_DoorCommon - IsExternal: yes; Reference: Garage sectionnelle:Garage sectionnelle; ThermalTransmittance: 3.7021 kg/K/s3
Autre - ID hôte: Mur de base: A-mur BA pierre 20 cm; Famille: Garage sectionnelle: Garage sectionnelle; Famille et type: Garage sectionnelle: Garage sectionnelle; Hauteur sous linteau: 2.8 m; ID du type: Garage sectionnelle: Garage sectionnelle; Type: Garage sectionnelle: Garage sectionnelle
Contraintes - Hauteur de l'appui: 0 m; Niveau: Niveau: R-1
Cotes - Surface: 9.5942 m2; Volume: 0.36216 m3
Données d'identification - Sous-projet: Menuiseries EXT; Identifiant: 44; Variantes: Modèle de base
Phase de construction - Phase de création: Nouvelle construction

# IfcDoor: PP (0.73m x 2.04m), Porte intérieur bois:PP (0.73m x 2.04m):1643992
In: R-1
Type - OperationType: SINGLE_SWING_LEFT; ParameterTakesPrecedence: no; Sizeable: no; Material: AA-Blanc satiné
Type - Autre(Type) - Catégorie: Portes; Nom de la famille: Porte intérieur bois
Type - Construction(Type) - Fonction: Intérieur; Fermeture du mur: Par hôte
Type - Cotes(Type) - Epaisseur: 0.04 m; Hauteur: 2.04 m; Largeur: 0.73 m
Type - Données d'identification(Type) - Sous-projet: Famille : Portes : Porte intérieur bois; Marque de type: 52; Modèle: MI-p73; Nom du type: PP (0.73m x 2.04m)
Type - Matériaux et finitions(Type) - Ajuster: AA-Blanc satiné; Image: AA-Blanc satiné; Panneau: AA-Blanc satiné; Poignée: AA-Blanc satiné
Type - Propriétés analytiques(Type) - Construction analytique: <Aucun>
Type - Texte(Type) - type porte: MI-p
Type - Porte intérieur bois:PP (0.73m x 2.04m):1643992 - PanelOperation: SWINGING
OverallHeight: 2.075 m; OverallWidth: 0.8 m
Pset_DoorCommon - IsExternal: no; Reference: Porte intérieur bois:PP (0.73m x 2.04m)
Autre - Catégorie: Portes; ID hôte: Mur de base: Générique - Int. 70 mm; Famille: Porte intérieur bois: PP (0.73m x 2.04m); Famille et type: Porte intérieur bois: PP (0.73m x 2.04m); ID du type: Porte intérieur bois: PP (0.73m x 2.04m); Type: Porte intérieur bois: PP (0.73m x 2.04m); Hauteur sous linteau: 2.04 m
Contraintes - Hauteur de l'appui: 0 m; Niveau: Niveau: R-1
Cotes - Surface: 2.11485 m2; Volume: 0.071524 m3
Données d'identification - Sous-projet: Menuiseries INT; Identifiant: 130
Graphismes - Angle d'ouverture 3D: 90 deg; Angle d'ouverture 2D fixe: yes
Phase de construction - Phase de création: Nouvelle construction

# IfcDoor: PP (0.73m x 2.04m) (2)
In: R-1
Type - OperationType: SINGLE_SWING_RIGHT; ParameterTakesPrecedence: no; Sizeable: no; Material: AA-Blanc satiné
Type - Autre(Type) - Catégorie: Portes; Nom de la famille: Porte intérieur bois
Type - Construction(Type) - Fonction: Intérieur; Fermeture du mur: Par hôte
Type - Cotes(Type) - Epaisseur: 0.04 m; Hauteur: 2.04 m; Largeur: 0.73 m
Type - Données d'identification(Type) - Sous-projet: Famille : Portes : Porte intérieur bois; Marque de type: 52; Modèle: MI-p73; Nom du type: PP (0.73m x 2.04m)
Type - Matériaux et finitions(Type) - Ajuster: AA-Blanc satiné; Image: AA-Blanc satiné; Panneau: AA-Blanc satiné; Poignée: AA-Blanc satiné
Type - Propriétés analytiques(Type) - Construction analytique: <Aucun>
Type - Texte(Type) - type porte: MI-p
Type - Porte intérieur bois:PP (0.73m x 2.04m):1689552 - PanelOperation: SWINGING
OverallHeight: 2.075 m; OverallWidth: 0.8 m
Pset_DoorCommon - IsExternal: no; Reference: Porte intérieur bois:PP (0.73m x 2.04m)
Autre - Catégorie: Portes; Famille: Porte intérieur bois: PP (0.73m x 2.04m); Famille et type: Porte intérieur bois: PP (0.73m x 2.04m); ID du type: Porte intérieur bois: PP (0.73m x 2.04m); Type: Porte intérieur bois: PP (0.73m x 2.04m); ID hôte: Mur de base: A-mur parpaing 10; Hauteur sous linteau: 2.04 m
Contraintes - Hauteur de l'appui: 0 m; Niveau: Niveau: R-1
Cotes - Surface: 2.2623 m2; Volume: 0.076648 m3
Données d'identification - Sous-projet: Menuiseries INT
Graphismes - Angle d'ouverture 3D: 90 deg; Angle d'ouverture 2D fixe: yes
Phase de construction - Phase de création: Nouvelle construction
Name (Porte intérieur bois:PP (0.73m x 2.04m):...) | Identifiant
1689552 | 137
1689553 | 138

# IfcDoor: PP (0.73m x 2.04m) (2)
In: RDC
Type - OperationType: SINGLE_SWING_RIGHT; ParameterTakesPrecedence: no; Sizeable: no; Material: AA-Blanc satiné
Type - Autre(Type) - Catégorie: Portes; Nom de la famille: Porte intérieur bois
Type - Construction(Type) - Fonction: Intérieur; Fermeture du mur: Par hôte
Type - Cotes(Type) - Epaisseur: 0.04 m; Hauteur: 2.04 m; Largeur: 0.73 m
Type - Données d'identification(Type) - Sous-projet: Famille : Portes : Porte intérieur bois; Marque de type: 52; Modèle: MI-p73; Nom du type: PP (0.73m x 2.04m)
Type - Matériaux et finitions(Type) - Ajuster: AA-Blanc satiné; Image: AA-Blanc satiné; Panneau: AA-Blanc satiné; Poignée: AA-Blanc satiné
Type - Propriétés analytiques(Type) - Construction analytique: <Aucun>
Type - Texte(Type) - type porte: MI-p
Type - Porte intérieur bois:PP (0.73m x 2.04m):2247725 - PanelOperation: SWINGING
OverallHeight: 2.075 m; OverallWidth: 0.8 m
Pset_DoorCommon - IsExternal: no; Reference: Porte intérieur bois:PP (0.73m x 2.04m)
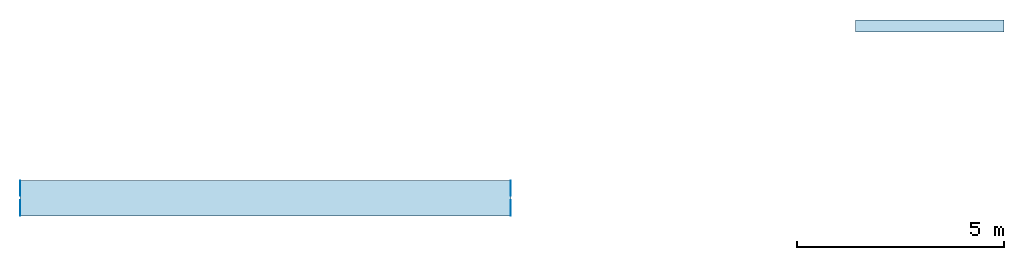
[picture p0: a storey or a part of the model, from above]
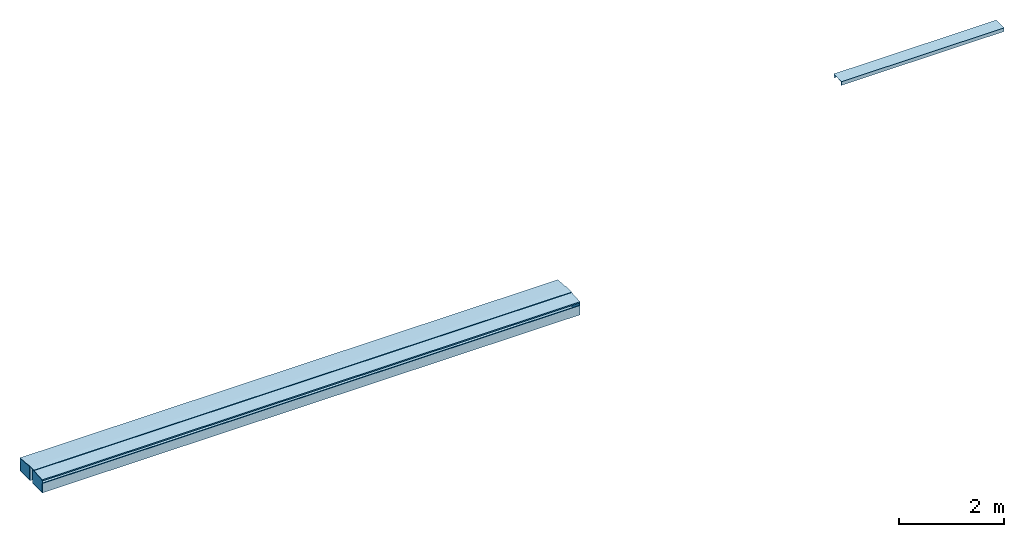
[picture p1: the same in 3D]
Properties of the parts of a building model (IFC2X3), part 3 of 5

# IfcDoor: PP (0.73m x 2.04m) (2)
Autre - Catégorie: Portes; ID hôte: Mur de base: Générique - Int. 70 mm; Famille: Porte intérieur bois: PP (0.73m x 2.04m); Famille et type: Porte intérieur bois: PP (0.73m x 2.04m); ID du type: Porte intérieur bois: PP (0.73m x 2.04m); Type: Porte intérieur bois: PP (0.73m x 2.04m); Hauteur sous linteau: 2.04 m
Contraintes - Hauteur de l'appui: 0 m; Niveau: Niveau: RDC
Cotes - Surface: 2.11485 m2; Volume: 0.071524 m3
Données d'identification - Sous-projet: Menuiseries INT
Graphismes - Angle d'ouverture 2D fixe: no; Angle d'ouverture 3D: 45 deg
Phase de construction - Phase de création: Nouvelle construction
Name (Porte intérieur bois:PP (0.73m x 2.04m):...) | Identifiant
2247725 | 169 | Données d'identification - Variantes: Modèle de base
2247726 | 170

# IfcDoor: PP (0.73m x 2.04m) (2)
Type - OperationType: SINGLE_SWING_RIGHT; ParameterTakesPrecedence: no; Sizeable: no; Material: AA-Blanc satiné
Type - Autre(Type) - Catégorie: Portes; Nom de la famille: Porte intérieur bois
Type - Construction(Type) - Fonction: Intérieur; Fermeture du mur: Par hôte
Type - Cotes(Type) - Epaisseur: 0.04 m; Hauteur: 2.04 m; Largeur: 0.73 m
Type - Données d'identification(Type) - Sous-projet: Famille : Portes : Porte intérieur bois; Marque de type: 52; Modèle: MI-p73; Nom du type: PP (0.73m x 2.04m)
Type - Matériaux et finitions(Type) - Ajuster: AA-Blanc satiné; Image: AA-Blanc satiné; Panneau: AA-Blanc satiné; Poignée: AA-Blanc satiné
Type - Propriétés analytiques(Type) - Construction analytique: <Aucun>
Type - Texte(Type) - type porte: MI-p
Type - Porte intérieur bois:PP (0.73m x 2.04m):2592097 - PanelOperation: SWINGING
OverallHeight: 2.075 m; OverallWidth: 0.8 m
Pset_DoorCommon - IsExternal: no; Reference: Porte intérieur bois:PP (0.73m x 2.04m)
Autre - Catégorie: Portes; ID hôte: Mur de base: Générique - Int. 70 mm; Famille: Porte intérieur bois: PP (0.73m x 2.04m); Famille et type: Porte intérieur bois: PP (0.73m x 2.04m); ID du type: Porte intérieur bois: PP (0.73m x 2.04m); Type: Porte intérieur bois: PP (0.73m x 2.04m); Hauteur sous linteau: 2.04 m
Contraintes - Hauteur de l'appui: 0 m
Cotes - Surface: 2.11485 m2; Volume: 0.071524 m3
Données d'identification - Sous-projet: Menuiseries INT; Variantes: Modèle de base
Graphismes - Angle d'ouverture 2D fixe: no; Angle d'ouverture 3D: 90 deg
Phase de construction - Phase de création: Nouvelle construction
Name (Porte intérieur bois:PP (0.73m x 2.04m):...) | In | Niveau | Identifiant
2592097 | R+1 | Niveau: R+1 | 190
2592781 | R+2 | Niveau: R+2 | 191

# IfcDoor: PP (0.83m x 2.04m), Porte intérieur bois:PP (0.83m x 2.04m):1687137
In: R-1
Type - OperationType: SINGLE_SWING_LEFT; ParameterTakesPrecedence: no; Sizeable: no; Material: AA-Blanc satiné, AA-bois menuiseries
Type - Porte intérieur bois:PP (0.83m x 2.04m):1687137 - PanelOperation: SWINGING
Type - Autre - Catégorie: Portes; Nom de la famille: Porte intérieur bois
Type - Construction - Fonction: Intérieur; Fermeture du mur: Par hôte
Type - Cotes - Epaisseur: 0.04 m; Hauteur: 2.04 m; Largeur: 0.83 m
Type - Données d'identification - Sous-projet: Famille : Portes : Porte intérieur bois; Marque de type: 31; Nom du type: PP (0.83m x 2.04m)
Type - Matériaux et finitions - Poignée: AA-Blanc satiné; Ajuster: AA-bois menuiseries; Image: AA-bois menuiseries; Panneau: AA-bois menuiseries
Type - Propriétés analytiques - Construction analytique: <Aucun>
Type - Texte - type porte: MI-p
OverallHeight: 2.075 m; OverallWidth: 0.9 m
Pset_DoorCommon - IsExternal: no; Reference: Porte intérieur bois:PP (0.83m x 2.04m)
Autre - ID hôte: Mur de base: A-mur parpaing 10; Famille: Porte intérieur bois: PP (0.83m x 2.04m); Famille et type: Porte intérieur bois: PP (0.83m x 2.04m); Hauteur sous linteau: 2.04 m; ID du type: Porte intérieur bois: PP (0.83m x 2.04m); Type: Porte intérieur bois: PP (0.83m x 2.04m)
Contraintes - Hauteur de l'appui: 0 m; Niveau: Niveau: R-1
Cotes - Surface: 2.4838 m2; Volume: 0.085158 m3
Données d'identification - Sous-projet: Menuiseries INT; Identifiant: 131; Variantes: Modèle de base
Graphismes - Angle d'ouverture 3D: 90 deg; Angle d'ouverture 2D fixe: yes
Phase de construction - Phase de création: Nouvelle construction

# IfcDoor: PP (0.93m x 2.04m), Porte extérieur + naco RDC:PP (0.93m x 2.04m):2242261
In: RDC
Type - OperationType: SINGLE_SWING_LEFT; ParameterTakesPrecedence: no; Sizeable: no; Material: AA-Aluminium, AA-vitrage, AA-Blanc satiné, AA-bois menuiseries
Type - Porte extérieur + naco RDC:PP (0.93m x 2.04m):2242261 - PanelOperation: SWINGING
Type - Autre - Catégorie: Portes; Nom de la famille: Porte extérieur + naco RDC
Type - Construction - Fonction: Intérieur; Fermeture du mur: Par hôte
Type - Cotes - Epaisseur: 0.04 m; Hauteur: 2.04 m; Largeur: 0.93 m
Type - Données d'identification - Marque de type: 63; Nom du type: PP (0.93m x 2.04m); Sous-projet: Famille : Portes : Porte extérieur + naco RDC
Type - Matériaux et finitions - Ajuster: AA-bois menuiseries; Image: AA-bois menuiseries; Panneau: AA-bois menuiseries; Poignée: AA-Blanc satiné
Type - Propriétés analytiques - Construction analytique: <Aucun>
Type - Texte - type porte: MI-p
OverallHeight: 3.75571 m; OverallWidth: 1 m
Pset_DoorCommon - IsExternal: no; Reference: Porte extérieur + naco RDC:PP (0.93m x 2.04m)
Autre - ID hôte: Mur de base: A-prémur BTC; Famille: Porte extérieur + naco RDC: PP (0.93m x 2.04m); Famille et type: Porte extérieur + naco RDC: PP (0.93m x 2.04m); Hauteur sous linteau: 2.04 m; ID du type: Porte extérieur + naco RDC: PP (0.93m x 2.04m); Type: Porte extérieur + naco RDC: PP (0.93m x 2.04m)
Contraintes - Hauteur de l'appui: 0 m; Niveau: Niveau: RDC
Cotes - Surface: 6.88361 m2; Volume: 0.175179 m3
Données d'identification - Sous-projet: Menuiseries EXT; Identifiant: 167; Variantes: Modèle de base
Graphismes - Angle d'ouverture 2D fixe: yes; Angle d'ouverture 3D: 0 deg
Phase de construction - Phase de création: Nouvelle construction

# IfcDoor: PP (0.93m x 2.04m) (2)
In: R-1
Type - OperationType: SINGLE_SWING_LEFT; ParameterTakesPrecedence: no; Sizeable: no; Material: AA-Blanc satiné
Type - Autre(Type) - Catégorie: Portes; Nom de la famille: Porte intérieur bois
Type - Construction(Type) - Fonction: Intérieur; Fermeture du mur: Par hôte
Type - Cotes(Type) - Epaisseur: 0.04 m; Hauteur: 2.04 m; Largeur: 0.93 m
Type - Données d'identification(Type) - Marque de type: 36; Nom du type: PP (0.93m x 2.04m); Note d'identification: MI-p93; Sous-projet: Famille : Portes : Porte intérieur bois
Type - Matériaux et finitions(Type) - Ajuster: AA-Blanc satiné; Image: AA-Blanc satiné; Panneau: AA-Blanc satiné; Poignée: AA-Blanc satiné
Type - Propriétés analytiques(Type) - Construction analytique: <Aucun>
Type - Texte(Type) - type porte: MI-p
Type - Porte intérieur bois:PP (0.93m x 2.04m):1014766 - PanelOperation: SWINGING
OverallHeight: 2.075 m; OverallWidth: 1.01603 m
Pset_DoorCommon - IsExternal: no; Reference: Porte intérieur bois:PP (0.93m x 2.04m)
Autre - Catégorie: Portes; Famille: Porte intérieur bois: PP (0.93m x 2.04m); Famille et type: Porte intérieur bois: PP (0.93m x 2.04m); ID du type: Porte intérieur bois: PP (0.93m x 2.04m); Type: Porte intérieur bois: PP (0.93m x 2.04m); ID hôte: Mur de base: A-mur BA 20 cm; Hauteur sous linteau: 2.04 m
Contraintes - Hauteur de l'appui: 0 m; Niveau: Niveau: R-1
Cotes - Surface: 3.2168 m2; Volume: 0.111448 m3
Données d'identification - Sous-projet: Menuiseries INT
Graphismes - Angle d'ouverture 3D: 90 deg; Angle d'ouverture 2D fixe: yes
Phase de construction - Phase de création: Nouvelle construction
Name (Porte intérieur bois:PP (0.93m x 2.04m):...) | Identifiant
1014766 | 73
1969503 | 148 | Données d'identification - Variantes: Modèle de base

# IfcDoor: PP (0.93m x 2.04m), Porte intérieur bois:PP (0.93m x 2.04m):1687186
In: R-1
Type - OperationType: SINGLE_SWING_LEFT; ParameterTakesPrecedence: no; Sizeable: no; Material: AA-Blanc satiné
Type - Autre(Type) - Catégorie: Portes; Nom de la famille: Porte intérieur bois
Type - Construction(Type) - Fonction: Intérieur; Fermeture du mur: Par hôte
Type - Cotes(Type) - Epaisseur: 0.04 m; Hauteur: 2.04 m; Largeur: 0.93 m
Type - Données d'identification(Type) - Marque de type: 36; Nom du type: PP (0.93m x 2.04m); Note d'identification: MI-p93; Sous-projet: Famille : Portes : Porte intérieur bois
Type - Matériaux et finitions(Type) - Ajuster: AA-Blanc satiné; Image: AA-Blanc satiné; Panneau: AA-Blanc satiné; Poignée: AA-Blanc satiné
Type - Propriétés analytiques(Type) - Construction analytique: <Aucun>
Type - Texte(Type) - type porte: MI-p
Type - Porte intérieur bois:PP (0.93m x 2.04m):1687186 - PanelOperation: SWINGING
OverallHeight: 2.075 m; OverallWidth: 1.01603 m
Pset_DoorCommon - IsExternal: no; Reference: Porte intérieur bois:PP (0.93m x 2.04m)
Autre - Catégorie: Portes; Famille: Porte intérieur bois: PP (0.93m x 2.04m); Famille et type: Porte intérieur bois: PP (0.93m x 2.04m); ID du type: Porte intérieur bois: PP (0.93m x 2.04m); Type: Porte intérieur bois: PP (0.93m x 2.04m); ID hôte: Mur de base: A-mur BA pierre 20 cm; Hauteur sous linteau: 2.04 m
Contraintes - Hauteur de l'appui: 0 m; Niveau: Niveau: R-1
Cotes - Surface: 3.2168 m2; Volume: 0.111448 m3
Données d'identification - Sous-projet: Menuiseries INT; Identifiant: 132; Variantes: Modèle de base
Graphismes - Angle d'ouverture 3D: 90 deg; Angle d'ouverture 2D fixe: yes
Phase de construction - Phase de création: Nouvelle construction

# IfcDoor: PP (0.93m x 2.04m) (2)
In: R-1
Type - OperationType: SINGLE_SWING_LEFT; ParameterTakesPrecedence: no; Sizeable: no; Material: AA-Blanc satiné
Type - Autre(Type) - Catégorie: Portes; Nom de la famille: Porte intérieur bois
Type - Construction(Type) - Fonction: Intérieur; Fermeture du mur: Par hôte
Type - Cotes(Type) - Epaisseur: 0.04 m; Hauteur: 2.04 m; Largeur: 0.93 m
Type - Données d'identification(Type) - Marque de type: 36; Nom du type: PP (0.93m x 2.04m); Note d'identification: MI-p93; Sous-projet: Famille : Portes : Porte intérieur bois
Type - Matériaux et finitions(Type) - Ajuster: AA-Blanc satiné; Image: AA-Blanc satiné; Panneau: AA-Blanc satiné; Poignée: AA-Blanc satiné
Type - Propriétés analytiques(Type) - Construction analytique: <Aucun>
Type - Texte(Type) - type porte: MI-p
Type - Porte intérieur bois:PP (0.93m x 2.04m):1689171 - PanelOperation: SWINGING
OverallHeight: 2.075 m; OverallWidth: 1 m
Pset_DoorCommon - IsExternal: no; Reference: Porte intérieur bois:PP (0.93m x 2.04m)
Autre - Catégorie: Portes; Famille: Porte intérieur bois: PP (0.93m x 2.04m); Famille et type: Porte intérieur bois: PP (0.93m x 2.04m); ID du type: Porte intérieur bois: PP (0.93m x 2.04m); Type: Porte intérieur bois: PP (0.93m x 2.04m); ID hôte: Mur de base: A-mur parpaing 10; Hauteur sous linteau: 2.04 m
Contraintes - Hauteur de l'appui: 0 m; Niveau: Niveau: R-1
Cotes - Surface: 2.7053 m2; Volume: 0.093668 m3
Données d'identification - Sous-projet: Menuiseries INT; Variantes: Modèle de base
Graphismes - Angle d'ouverture 3D: 90 deg; Angle d'ouverture 2D fixe: yes
Phase de construction - Phase de création: Nouvelle construction
Name (Porte intérieur bois:PP (0.93m x 2.04m):...) | Identifiant
1689171 | 136
1689555 | 139

# IfcDoor: PP (0.93m x 2.04m) (2)
Type - OperationType: SINGLE_SWING_LEFT; ParameterTakesPrecedence: no; Sizeable: no; Material: AA-Blanc satiné
Type - Autre(Type) - Catégorie: Portes; Nom de la famille: Porte intérieur bois
Type - Construction(Type) - Fonction: Intérieur; Fermeture du mur: Par hôte
Type - Cotes(Type) - Epaisseur: 0.04 m; Hauteur: 2.04 m; Largeur: 0.93 m
Type - Données d'identification(Type) - Marque de type: 36; Nom du type: PP (0.93m x 2.04m); Note d'identification: MI-p93; Sous-projet: Famille : Portes : Porte intérieur bois
Type - Matériaux et finitions(Type) - Ajuster: AA-Blanc satiné; Image: AA-Blanc satiné; Panneau: AA-Blanc satiné; Poignée: AA-Blanc satiné
Type - Propriétés analytiques(Type) - Construction analytique: <Aucun>
Type - Texte(Type) - type porte: MI-p
Type - Porte intérieur bois:PP (0.93m x 2.04m):2247722 - PanelOperation: SWINGING
OverallHeight: 2.075 m; OverallWidth: 1 m
Pset_DoorCommon - IsExternal: no; Reference: Porte intérieur bois:PP (0.93m x 2.04m)
Autre - Catégorie: Portes; Famille: Porte intérieur bois: PP (0.93m x 2.04m); Famille et type: Porte intérieur bois: PP (0.93m x 2.04m); ID du type: Porte intérieur bois: PP (0.93m x 2.04m); Type: Porte intérieur bois: PP (0.93m x 2.04m); ID hôte: Mur de base: Générique - Int. 70 mm; Hauteur sous linteau: 2.04 m
Contraintes - Hauteur de l'appui: 0 m
Cotes - Surface: 2.55185 m2; Volume: 0.088334 m3
Données d'identification - Sous-projet: Menuiseries INT; Variantes: Modèle de base
Graphismes - Angle d'ouverture 2D fixe: no; Angle d'ouverture 3D: 45 deg
Phase de construction - Phase de création: Nouvelle construction
Name (Porte intérieur bois:PP (0.93m x 2.04m):...) | In | Niveau | Identifiant
2247722 | RDC | Niveau: RDC | 168
2521086 | R+2 | Niveau: R+2 | 186

# IfcDoor: PP (0.93m x 2.04m) (8)
Type - OperationType: SINGLE_SWING_LEFT; ParameterTakesPrecedence: no; Sizeable: no; Material: AA-Blanc satiné
Type - Autre(Type) - Catégorie: Portes; Nom de la famille: Porte intérieur bois
Type - Construction(Type) - Fonction: Intérieur; Fermeture du mur: Par hôte
Type - Cotes(Type) - Epaisseur: 0.04 m; Hauteur: 2.04 m; Largeur: 0.93 m
Type - Données d'identification(Type) - Marque de type: 36; Nom du type: PP (0.93m x 2.04m); Note d'identification: MI-p93; Sous-projet: Famille : Portes : Porte intérieur bois
Type - Matériaux et finitions(Type) - Ajuster: AA-Blanc satiné; Image: AA-Blanc satiné; Panneau: AA-Blanc satiné; Poignée: AA-Blanc satiné
Type - Propriétés analytiques(Type) - Construction analytique: <Aucun>
Type - Texte(Type) - type porte: MI-p
Type - Porte intérieur bois:PP (0.93m x 2.04m):340214 - PanelOperation: SWINGING
OverallHeight: 2.075 m; OverallWidth: 1 m
Pset_DoorCommon - IsExternal: no; Reference: Porte intérieur bois:PP (0.93m x 2.04m)
Autre - Catégorie: Portes; Famille: Porte intérieur bois: PP (0.93m x 2.04m); Famille et type: Porte intérieur bois: PP (0.93m x 2.04m); ID du type: Porte intérieur bois: PP (0.93m x 2.04m); Type: Porte intérieur bois: PP (0.93m x 2.04m); Hauteur sous linteau: 2.04 m; ID hôte: Mur de base: A-cloison CP 11.6 cm
Contraintes - Hauteur de l'appui: 0 m
Cotes - Surface: 2.78714 m2; Volume: 0.0965128 m3
Données d'identification - Sous-projet: Menuiseries INT
Graphismes - Angle d'ouverture 2D fixe: no; Angle d'ouverture 3D: 45 deg
Phase de construction - Phase de création: Nouvelle construction
Name (Porte intérieur bois:PP (0.93m x 2.04m):...) | In | Niveau | Identifiant
340214 | R+1 | Niveau: R+1 | 2 | Données d'identification - Variantes: Modèle de base
349355 | RDC | Niveau: RDC | 4 | Données d'identification - Variantes: Modèle de base
350800 | RDC | Niveau: RDC | 7
2250794 | R+1 | Niveau: R+1 | 173
2262081 | R+1 | Niveau: R+1 | 178
2262082 | R+1 | Niveau: R+1 | 179
2520686 | R+2 | Niveau: R+2 | 183 | Données d'identification - Variantes: Modèle de base
2521271 | R+2 | Niveau: R+2 | 187

# IfcDoor: PP (0.93m x 2.04m) (7)
Type - OperationType: SINGLE_SWING_LEFT; ParameterTakesPrecedence: no; Sizeable: no; Material: AA-Blanc satiné
Type - Autre(Type) - Catégorie: Portes; Nom de la famille: Porte intérieur bois
Type - Construction(Type) - Fonction: Intérieur; Fermeture du mur: Par hôte
Type - Cotes(Type) - Epaisseur: 0.04 m; Hauteur: 2.04 m; Largeur: 0.93 m
Type - Données d'identification(Type) - Marque de type: 36; Nom du type: PP (0.93m x 2.04m); Note d'identification: MI-p93; Sous-projet: Famille : Portes : Porte intérieur bois
Type - Matériaux et finitions(Type) - Ajuster: AA-Blanc satiné; Image: AA-Blanc satiné; Panneau: AA-Blanc satiné; Poignée: AA-Blanc satiné
Type - Propriétés analytiques(Type) - Construction analytique: <Aucun>
Type - Texte(Type) - type porte: MI-p
Type - Porte intérieur bois:PP (0.93m x 2.04m):351049 - PanelOperation: SWINGING
OverallHeight: 2.075 m; OverallWidth: 1 m
Pset_DoorCommon - IsExternal: no; Reference: Porte intérieur bois:PP (0.93m x 2.04m)
Autre - Catégorie: Portes; Famille: Porte intérieur bois: PP (0.93m x 2.04m); Famille et type: Porte intérieur bois: PP (0.93m x 2.04m); ID du type: Porte intérieur bois: PP (0.93m x 2.04m); ID hôte: Mur de base: A-cloison FC 10.5 cm; Type: Porte intérieur bois: PP (0.93m x 2.04m); Hauteur sous linteau: 2.04 m
Contraintes - Hauteur de l'appui: 0 m
Cotes - Surface: 2.73088 m2; Volume: 0.094557 m3
Données d'identification - Sous-projet: Menuiseries INT
Graphismes - Angle d'ouverture 2D fixe: no; Angle d'ouverture 3D: 45 deg
Phase de construction - Phase de création: Nouvelle construction
Name (Porte intérieur bois:PP (0.93m x 2.04m):...) | In | Niveau | Identifiant | Variantes
351049 | RDC | Niveau: RDC | 8
382125 | R+2 | Niveau: R+2 | 11 | Modèle de base
759675 | RDC | Niveau: RDC | 24 | Modèle de base
885262 | R+1 | Niveau: R+1 | 26 | Modèle de base
885306 | R+2 | Niveau: R+2 | 27 | Modèle de base
2242073 | RDC | Niveau: RDC | 166
2264024 | R+1 | Niveau: R+1 | 180

# IfcDoor: PP (0.93m x 2.04m) (2)
Type - OperationType: SINGLE_SWING_LEFT; ParameterTakesPrecedence: no; Sizeable: no; Material: AA-Blanc satiné
Type - Autre(Type) - Catégorie: Portes; Nom de la famille: Porte intérieur bois
Type - Construction(Type) - Fonction: Intérieur; Fermeture du mur: Par hôte
Type - Cotes(Type) - Epaisseur: 0.04 m; Hauteur: 2.04 m; Largeur: 0.93 m
Type - Données d'identification(Type) - Marque de type: 36; Nom du type: PP (0.93m x 2.04m); Note d'identification: MI-p93; Sous-projet: Famille : Portes : Porte intérieur bois
Type - Matériaux et finitions(Type) - Ajuster: AA-Blanc satiné; Image: AA-Blanc satiné; Panneau: AA-Blanc satiné; Poignée: AA-Blanc satiné
Type - Propriétés analytiques(Type) - Construction analytique: <Aucun>
Type - Texte(Type) - type porte: MI-p
Type - Porte intérieur bois:PP (0.93m x 2.04m):351249 - PanelOperation: SWINGING
OverallHeight: 2.075 m; OverallWidth: 1 m
Pset_DoorCommon - IsExternal: no; Reference: Porte intérieur bois:PP (0.93m x 2.04m)
Autre - Catégorie: Portes; Famille: Porte intérieur bois: PP (0.93m x 2.04m); Famille et type: Porte intérieur bois: PP (0.93m x 2.04m); ID du type: Porte intérieur bois: PP (0.93m x 2.04m); ID hôte: Mur de base: A-cloison FC 10.5 cm; Type: Porte intérieur bois: PP (0.93m x 2.04m); Hauteur sous linteau: 2.04 m
Contraintes - Hauteur de l'appui: 0 m
Cotes - Surface: 2.73088 m2; Volume: 0.094557 m3
Données d'identification - Sous-projet: Menuiseries INT; Variantes: Modèle de base
Graphismes - Angle d'ouverture 2D fixe: no; Angle d'ouverture 3D: 90 deg
Phase de construction - Phase de création: Nouvelle construction
Name (Porte intérieur bois:PP (0.93m x 2.04m):...) | In | Niveau | Identifiant
351249 | R+1 | Niveau: R+1 | 9
382130 | R+2 | Niveau: R+2 | 13

# IfcDoor: PP (0.93m x 2.04m), Porte intérieur bois:PP (0.93m x 2.04m):892398
In: R-1
Type - OperationType: SINGLE_SWING_LEFT; ParameterTakesPrecedence: no; Sizeable: no; Material: AA-Blanc satiné
Type - Autre(Type) - Catégorie: Portes; Nom de la famille: Porte intérieur bois
Type - Construction(Type) - Fonction: Intérieur; Fermeture du mur: Par hôte
Type - Cotes(Type) - Epaisseur: 0.04 m; Hauteur: 2.04 m; Largeur: 0.93 m
Type - Données d'identification(Type) - Marque de type: 36; Nom du type: PP (0.93m x 2.04m); Note d'identification: MI-p93; Sous-projet: Famille : Portes : Porte intérieur bois
Type - Matériaux et finitions(Type) - Ajuster: AA-Blanc satiné; Image: AA-Blanc satiné; Panneau: AA-Blanc satiné; Poignée: AA-Blanc satiné
Type - Propriétés analytiques(Type) - Construction analytique: <Aucun>
Type - Texte(Type) - type porte: MI-p
Type - Porte intérieur bois:PP (0.93m x 2.04m):892398 - PanelOperation: SWINGING
OverallHeight: 2.075 m; OverallWidth: 1 m
Pset_DoorCommon - IsExternal: no; Reference: Porte intérieur bois:PP (0.93m x 2.04m)
Autre - Catégorie: Portes; Famille: Porte intérieur bois: PP (0.93m x 2.04m); Famille et type: Porte intérieur bois: PP (0.93m x 2.04m); ID du type: Porte intérieur bois: PP (0.93m x 2.04m); Type: Porte intérieur bois: PP (0.93m x 2.04m); ID hôte: Mur de base: Générique - Int. 70 mm; Hauteur sous linteau: 2.04 m
Contraintes - Hauteur de l'appui: 0 m; Niveau: Niveau: R-1
Cotes - Surface: 2.55185 m2; Volume: 0.088334 m3
Données d'identification - Sous-projet: Menuiseries INT; Identifiant: 36
Graphismes - Angle d'ouverture 3D: 90 deg; Angle d'ouverture 2D fixe: yes
Phase de construction - Phase de création: Nouvelle construction

# IfcDoor: PP (0.93m x 2.04m), Porte extérieur + naco R+1:PP (0.93m x 2.04m):691484
In: R+1
Type - OperationType: SINGLE_SWING_RIGHT; ParameterTakesPrecedence: no; Sizeable: no; Material: AA-Aluminium, AA-vitrage, AA-Blanc satiné, AA-bois menuiseries
Type - Porte extérieur + naco R+1:PP (0.93m x 2.04m):691484 - PanelOperation: SWINGING
Type - Autre - Catégorie: Portes; Nom de la famille: Porte extérieur + naco R+1
Type - Construction - Fonction: Intérieur; Fermeture du mur: Par hôte
Type - Cotes - Epaisseur: 0.04 m; Hauteur: 2.04 m; Largeur: 0.93 m
Type - Données d'identification - Marque de type: 60; Nom du type: PP (0.93m x 2.04m); Sous-projet: Famille : Portes : Porte extérieur + naco R+1
Type - Matériaux et finitions - Ajuster: AA-bois menuiseries; Image: AA-bois menuiseries; Panneau: AA-bois menuiseries; Poignée: AA-Blanc satiné
Type - Propriétés analytiques - Construction analytique: <Aucun>
OverallHeight: 3.04571 m; OverallWidth: 1 m
Pset_DoorCommon - IsExternal: no; Reference: Porte extérieur + naco R+1:PP (0.93m x 2.04m)
Autre - Famille: Porte extérieur + naco R+1: PP (0.93m x 2.04m); Famille et type: Porte extérieur + naco R+1: PP (0.93m x 2.04m); Hauteur sous linteau: 2.04 m; ID du type: Porte extérieur + naco R+1: PP (0.93m x 2.04m); ID hôte: Mur de base: A-prémur BTC; Type: Porte extérieur + naco R+1: PP (0.93m x 2.04m)
Contraintes - Niveau: Niveau: R+1; Hauteur de l'appui: 0 m
Cotes - Surface: 5.60879 m2; Volume: 0.159749 m3
Données d'identification - Sous-projet: Menuiseries EXT; Identifiant: 22
Graphismes - Angle d'ouverture 2D fixe: yes; Angle d'ouverture 3D: 0 deg
Phase de construction - Phase de création: Nouvelle construction

# IfcDoor: PP (0.93m x 2.04m), Porte extérieur + naco:PP (0.93m x 2.04m):691498
In: R+2
Type - OperationType: SINGLE_SWING_RIGHT; ParameterTakesPrecedence: no; Sizeable: no; Material: AA-Aluminium, AA-vitrage, AA-Blanc satiné, AA-bois menuiseries
Type - Porte extérieur + naco:PP (0.93m x 2.04m):691498 - PanelOperation: SWINGING
Type - Autre - Catégorie: Portes; Nom de la famille: Porte extérieur + naco
Type - Construction - Fonction: Intérieur; Fermeture du mur: Par hôte
Type - Cotes - Epaisseur: 0.04 m; Hauteur: 2.04 m; Largeur: 0.93 m
Type - Données d'identification - Marque de type: 45; Nom du type: PP (0.93m x 2.04m); Sous-projet: Famille : Portes : Porte extérieur + naco
Type - Matériaux et finitions - Ajuster: AA-bois menuiseries; Image: AA-bois menuiseries; Panneau: AA-bois menuiseries; Poignée: AA-Blanc satiné
Type - Propriétés analytiques - Construction analytique: <Aucun>
Type - Texte - type porte: MI-p
OverallHeight: 2.89571 m; OverallWidth: 1 m
Pset_DoorCommon - IsExternal: no; Reference: Porte extérieur + naco:PP (0.93m x 2.04m)
Autre - ID hôte: Mur de base: A-prémur BTC; Famille: Porte extérieur + naco: PP (0.93m x 2.04m); Famille et type: Porte extérieur + naco: PP (0.93m x 2.04m); Hauteur sous linteau: 2.04 m; ID du type: Porte extérieur + naco: PP (0.93m x 2.04m); Type: Porte extérieur + naco: PP (0.93m x 2.04m)
Contraintes - Hauteur de l'appui: 0 m; Niveau: Niveau: R+2
Cotes - Surface: 4.07708 m2; Volume: 0.117574 m3
Données d'identification - Sous-projet: Menuiseries EXT; Identifiant: 23
Graphismes - Angle d'ouverture 3D: 45 deg; Angle d'ouverture 2D fixe: yes
Phase de construction - Phase de création: Nouvelle construction

# IfcDoor: PP (0.93m x 2.04m), Porte intérieur bois:PP (0.93m x 2.04m):1014763
In: R-1
Type - OperationType: SINGLE_SWING_RIGHT; ParameterTakesPrecedence: no; Sizeable: no; Material: AA-Blanc satiné
Type - Autre(Type) - Catégorie: Portes; Nom de la famille: Porte intérieur bois
Type - Construction(Type) - Fonction: Intérieur; Fermeture du mur: Par hôte
Type - Cotes(Type) - Epaisseur: 0.04 m; Hauteur: 2.04 m; Largeur: 0.93 m
Type - Données d'identification(Type) - Marque de type: 36; Nom du type: PP (0.93m x 2.04m); Note d'identification: MI-p93; Sous-projet: Famille : Portes : Porte intérieur bois
Type - Matériaux et finitions(Type) - Ajuster: AA-Blanc satiné; Image: AA-Blanc satiné; Panneau: AA-Blanc satiné; Poignée: AA-Blanc satiné
Type - Propriétés analytiques(Type) - Construction analytique: <Aucun>
Type - Texte(Type) - type porte: MI-p
Type - Porte intérieur bois:PP (0.93m x 2.04m):1014763 - PanelOperation: SWINGING
OverallHeight: 2.075 m; OverallWidth: 1.01603 m
Pset_DoorCommon - IsExternal: no; Reference: Porte intérieur bois:PP (0.93m x 2.04m)
Autre - Catégorie: Portes; Famille: Porte intérieur bois: PP (0.93m x 2.04m); Famille et type: Porte intérieur bois: PP (0.93m x 2.04m); ID du type: Porte intérieur bois: PP (0.93m x 2.04m); Type: Porte intérieur bois: PP (0.93m x 2.04m); ID hôte: Mur de base: A-mur BA 20 cm; Hauteur sous linteau: 2.04 m
Contraintes - Hauteur de l'appui: 0 m; Niveau: Niveau: R-1
Cotes - Surface: 3.2168 m2; Volume: 0.111448 m3
Données d'identification - Sous-projet: Menuiseries INT; Identifiant: 70
Graphismes - Angle d'ouverture 3D: 90 deg; Angle d'ouverture 2D fixe: yes
Phase de construction - Phase de création: Nouvelle construction

# IfcDoor: PP (0.93m x 2.04m) (2)
In: R-1
Type - OperationType: SINGLE_SWING_RIGHT; ParameterTakesPrecedence: no; Sizeable: no; Material: AA-Blanc satiné
Type - Autre(Type) - Catégorie: Portes; Nom de la famille: Porte intérieur bois
Type - Construction(Type) - Fonction: Intérieur; Fermeture du mur: Par hôte
Type - Cotes(Type) - Epaisseur: 0.04 m; Hauteur: 2.04 m; Largeur: 0.93 m
Type - Données d'identification(Type) - Marque de type: 36; Nom du type: PP (0.93m x 2.04m); Note d'identification: MI-p93; Sous-projet: Famille : Portes : Porte intérieur bois
Type - Matériaux et finitions(Type) - Ajuster: AA-Blanc satiné; Image: AA-Blanc satiné; Panneau: AA-Blanc satiné; Poignée: AA-Blanc satiné
Type - Propriétés analytiques(Type) - Construction analytique: <Aucun>
Type - Texte(Type) - type porte: MI-p
Type - Porte intérieur bois:PP (0.93m x 2.04m):1014764 - PanelOperation: SWINGING
OverallHeight: 2.075 m; OverallWidth: 1 m
Pset_DoorCommon - IsExternal: no; Reference: Porte intérieur bois:PP (0.93m x 2.04m)
Autre - Catégorie: Portes; Famille: Porte intérieur bois: PP (0.93m x 2.04m); Famille et type: Porte intérieur bois: PP (0.93m x 2.04m); ID du type: Porte intérieur bois: PP (0.93m x 2.04m); Type: Porte intérieur bois: PP (0.93m x 2.04m); ID hôte: Mur de base: Générique - Int. 70 mm; Hauteur sous linteau: 2.04 m
Contraintes - Hauteur de l'appui: 0 m; Niveau: Niveau: R-1
Cotes - Surface: 2.55185 m2; Volume: 0.088334 m3
Données d'identification - Sous-projet: Menuiseries INT; Variantes: Modèle de base
Graphismes - Angle d'ouverture 3D: 90 deg; Angle d'ouverture 2D fixe: yes
Phase de construction - Phase de création: Nouvelle construction
Name (Porte intérieur bois:PP (0.93m x 2.04m):...) | Identifiant
1014764 | 71
1231486 | 81

# IfcDoor: PP (0.93m x 2.04m), Porte intérieur bois:PP (0.93m x 2.04m):1014765
In: R-1
Type - OperationType: SINGLE_SWING_RIGHT; ParameterTakesPrecedence: no; Sizeable: no; Material: AA-Blanc satiné
Type - Autre(Type) - Catégorie: Portes; Nom de la famille: Porte intérieur bois
Type - Construction(Type) - Fonction: Intérieur; Fermeture du mur: Par hôte
Type - Cotes(Type) - Epaisseur: 0.04 m; Hauteur: 2.04 m; Largeur: 0.93 m
Type - Données d'identification(Type) - Marque de type: 36; Nom du type: PP (0.93m x 2.04m); Note d'identification: MI-p93; Sous-projet: Famille : Portes : Porte intérieur bois
Type - Matériaux et finitions(Type) - Ajuster: AA-Blanc satiné; Image: AA-Blanc satiné; Panneau: AA-Blanc satiné; Poignée: AA-Blanc satiné
Type - Propriétés analytiques(Type) - Construction analytique: <Aucun>
Type - Texte(Type) - type porte: MI-p
Type - Porte intérieur bois:PP (0.93m x 2.04m):1014765 - PanelOperation: SWINGING
OverallHeight: 2.075 m; OverallWidth: 1 m
Pset_DoorCommon - IsExternal: no; Reference: Porte intérieur bois:PP (0.93m x 2.04m)
Autre - Catégorie: Portes; Famille: Porte intérieur bois: PP (0.93m x 2.04m); Famille et type: Porte intérieur bois: PP (0.93m x 2.04m); ID du type: Porte intérieur bois: PP (0.93m x 2.04m); Type: Porte intérieur bois: PP (0.93m x 2.04m); ID hôte: Mur de base: A-mur BA 20 cm; Hauteur sous linteau: 2.04 m
Contraintes - Hauteur de l'appui: 0 m; Niveau: Niveau: R-1
Cotes - Surface: 3.2168 m2; Volume: 0.111448 m3
Données d'identification - Sous-projet: Menuiseries INT; Identifiant: 72
Graphismes - Angle d'ouverture 2D fixe: no; Angle d'ouverture 3D: 45 deg
Phase de construction - Phase de création: Nouvelle construction

# IfcDoor: PP (0.93m x 2.04m) (2)
Type - OperationType: SINGLE_SWING_RIGHT; ParameterTakesPrecedence: no; Sizeable: no; Material: AA-Blanc satiné
Type - Autre(Type) - Catégorie: Portes; Nom de la famille: Porte intérieur bois
Type - Construction(Type) - Fonction: Intérieur; Fermeture du mur: Par hôte
Type - Cotes(Type) - Epaisseur: 0.04 m; Hauteur: 2.04 m; Largeur: 0.93 m
Type - Données d'identification(Type) - Marque de type: 36; Nom du type: PP (0.93m x 2.04m); Note d'identification: MI-p93; Sous-projet: Famille : Portes : Porte intérieur bois
Type - Matériaux et finitions(Type) - Ajuster: AA-Blanc satiné; Image: AA-Blanc satiné; Panneau: AA-Blanc satiné; Poignée: AA-Blanc satiné
Type - Propriétés analytiques(Type) - Construction analytique: <Aucun>
Type - Texte(Type) - type porte: MI-p
Type - Porte intérieur bois:PP (0.93m x 2.04m):1643345 - PanelOperation: SWINGING
OverallHeight: 2.075 m; OverallWidth: 1 m
Pset_DoorCommon - IsExternal: no; Reference: Porte intérieur bois:PP (0.93m x 2.04m)
Autre - Catégorie: Portes; Famille: Porte intérieur bois: PP (0.93m x 2.04m); Famille et type: Porte intérieur bois: PP (0.93m x 2.04m); ID du type: Porte intérieur bois: PP (0.93m x 2.04m); Type: Porte intérieur bois: PP (0.93m x 2.04m); ID hôte: Mur de base: Générique - Int. 70 mm; Hauteur sous linteau: 2.04 m
Contraintes - Hauteur de l'appui: 0 m
Cotes - Surface: 2.55185 m2; Volume: 0.088334 m3
Données d'identification - Sous-projet: Menuiseries INT; Variantes: Modèle de base
Graphismes - Angle d'ouverture 2D fixe: no; Angle d'ouverture 3D: 45 deg
Phase de construction - Phase de création: Nouvelle construction
Name (Porte intérieur bois:PP (0.93m x 2.04m):...) | In | Niveau | Identifiant
1643345 | R+2 | Niveau: R+2 | 128
2171205 | R+1 | Niveau: R+1 | 162

# IfcDoor: PP (0.93m x 2.04m) (5)
In: R+1
Type - OperationType: SINGLE_SWING_RIGHT; ParameterTakesPrecedence: no; Sizeable: no; Material: AA-Blanc satiné
Type - Autre(Type) - Catégorie: Portes; Nom de la famille: Porte intérieur bois
Type - Construction(Type) - Fonction: Intérieur; Fermeture du mur: Par hôte
Type - Cotes(Type) - Epaisseur: 0.04 m; Hauteur: 2.04 m; Largeur: 0.93 m
Type - Données d'identification(Type) - Marque de type: 36; Nom du type: PP (0.93m x 2.04m); Note d'identification: MI-p93; Sous-projet: Famille : Portes : Porte intérieur bois
Type - Matériaux et finitions(Type) - Ajuster: AA-Blanc satiné; Image: AA-Blanc satiné; Panneau: AA-Blanc satiné; Poignée: AA-Blanc satiné
Type - Propriétés analytiques(Type) - Construction analytique: <Aucun>
Type - Texte(Type) - type porte: MI-p
Type - Porte intérieur bois:PP (0.93m x 2.04m):2261362 - PanelOperation: SWINGING
OverallHeight: 2.075 m; OverallWidth: 1 m
Pset_DoorCommon - IsExternal: no; Reference: Porte intérieur bois:PP (0.93m x 2.04m)
Autre - Catégorie: Portes; Famille: Porte intérieur bois: PP (0.93m x 2.04m); Famille et type: Porte intérieur bois: PP (0.93m x 2.04m); ID du type: Porte intérieur bois: PP (0.93m x 2.04m); Type: Porte intérieur bois: PP (0.93m x 2.04m); ID hôte: Mur de base: A-cloison CP 11.6 cm; Hauteur sous linteau: 2.04 m
Contraintes - Niveau: Niveau: R+1; Hauteur de l'appui: 0 m
Cotes - Surface: 2.78714 m2; Volume: 0.0965128 m3
Données d'identification - Sous-projet: Menuiseries INT
Graphismes - Angle d'ouverture 2D fixe: no; Angle d'ouverture 3D: 45 deg
Phase de construction - Phase de création: Nouvelle construction
Name (Porte intérieur bois:PP (0.93m x 2.04m):...) | Identifiant
2261362 | 176
2261478 | 177
2270242 | 182
2560760 | 189 | Données d'identification - Variantes: Modèle de base
2758900 | 193

# IfcDoor: PP (0.93m x 2.04m) métal (2)
In: R-1
Type - OperationType: SINGLE_SWING_LEFT; ParameterTakesPrecedence: no; Sizeable: no; Material: AA-Blanc satiné, AA-Aluminium
Type - Autre - Catégorie: Portes; Nom de la famille: Int. Simple
Type - Construction - Fermeture du mur: Par hôte
Type - Cotes - Epaisseur: 0.04 m; Hauteur: 2.04 m; Largeur: 0.93 m
Type - Données d'identification - Marque de type: 37; Nom du type: PP (0.93m x 2.04m) métal; Sous-projet: Famille : Portes : Int. Simple
Type - Matériaux et finitions - Ajuster: AA-Aluminium; Image: AA-Aluminium; Panneau: AA-Aluminium; Poignée: AA-Blanc satiné
Type - Propriétés analytiques - Construction analytique: <Aucun>
Type - Texte - type porte: MI-p
Type - Int. Simple:PP (0.93m x 2.04m) métal:1014715 - PanelOperation: SWINGING
OverallHeight: 2.09 m; OverallWidth: 1.03103 m
Pset_DoorCommon - IsExternal: yes; Reference: Int. Simple:PP (0.93m x 2.04m) métal
Autre - Famille: Int. Simple: PP (0.93m x 2.04m) métal; Famille et type: Int. Simple: PP (0.93m x 2.04m) métal; ID du type: Int. Simple: PP (0.93m x 2.04m) métal; Type: Int. Simple: PP (0.93m x 2.04m) métal; Hauteur sous linteau: 2.04 m; ID hôte: Mur de base: A-mur BA 20 cm
Contraintes - Hauteur de l'appui: 0 m; Niveau: Niveau: R-1
Cotes - Surface: 3.2168 m2; Volume: 0.111448 m3
Données d'identification - Sous-projet: Menuiseries INT; Variantes: Modèle de base
Graphismes - Angle d'ouverture 3D: 90 deg; Angle d'ouverture 2D fixe: yes
Phase de construction - Phase de création: Nouvelle construction
Name (Int. Simple:PP (0.93m x 2.04m) métal:...) | Identifiant
1014715 | 65
2603725 | 192

# IfcDoor: PP (0.93m x 2.04m) métal, Int. Simple:PP (0.93m x 2.04m) métal:1014716
In: R-1
Type - OperationType: SINGLE_SWING_LEFT; ParameterTakesPrecedence: no; Sizeable: no; Material: AA-Blanc satiné, AA-Aluminium
Type - Autre - Catégorie: Portes; Nom de la famille: Int. Simple
Type - Construction - Fermeture du mur: Par hôte
Type - Cotes - Epaisseur: 0.04 m; Hauteur: 2.04 m; Largeur: 0.93 m
Type - Données d'identification - Marque de type: 37; Nom du type: PP (0.93m x 2.04m) métal; Sous-projet: Famille : Portes : Int. Simple
Type - Matériaux et finitions - Ajuster: AA-Aluminium; Image: AA-Aluminium; Panneau: AA-Aluminium; Poignée: AA-Blanc satiné
Type - Propriétés analytiques - Construction analytique: <Aucun>
Type - Texte - type porte: MI-p
Type - Int. Simple:PP (0.93m x 2.04m) métal:1014716 - PanelOperation: SWINGING
OverallHeight: 2.09 m; OverallWidth: 1.03 m
Pset_DoorCommon - IsExternal: yes; Reference: Int. Simple:PP (0.93m x 2.04m) métal
Autre - Famille: Int. Simple: PP (0.93m x 2.04m) métal; Famille et type: Int. Simple: PP (0.93m x 2.04m) métal; ID du type: Int. Simple: PP (0.93m x 2.04m) métal; Type: Int. Simple: PP (0.93m x 2.04m) métal; ID hôte: Mur de base: A-mur BA 20 cm; Hauteur sous linteau: 2.04 m
Contraintes - Hauteur de l'appui: 0 m; Niveau: Niveau: R-1
Cotes - Surface: 3.2168 m2; Volume: 0.111448 m3
Données d'identification - Sous-projet: Menuiseries INT; Identifiant: 66
Graphismes - Angle d'ouverture 2D fixe: no; Angle d'ouverture 3D: 45 deg
Phase de construction - Phase de création: Nouvelle construction

# IfcDoor: PP (0.93m x 2.04m) métal, Int. Simple:PP (0.93m x 2.04m) métal:1391208
In: R-1
Type - OperationType: SINGLE_SWING_LEFT; ParameterTakesPrecedence: no; Sizeable: no; Material: AA-Blanc satiné, AA-Aluminium
Type - Autre - Catégorie: Portes; Nom de la famille: Int. Simple
Type - Construction - Fermeture du mur: Par hôte
Type - Cotes - Epaisseur: 0.04 m; Hauteur: 2.04 m; Largeur: 0.93 m
Type - Données d'identification - Marque de type: 37; Nom du type: PP (0.93m x 2.04m) métal; Sous-projet: Famille : Portes : Int. Simple
Type - Matériaux et finitions - Ajuster: AA-Aluminium; Image: AA-Aluminium; Panneau: AA-Aluminium; Poignée: AA-Blanc satiné
Type - Propriétés analytiques - Construction analytique: <Aucun>
Type - Texte - type porte: MI-p
Type - Int. Simple:PP (0.93m x 2.04m) métal:1391208 - PanelOperation: SWINGING
OverallHeight: 2.09 m; OverallWidth: 1.03 m
Pset_DoorCommon - IsExternal: no; Reference: Int. Simple:PP (0.93m x 2.04m) métal
Autre - Famille: Int. Simple: PP (0.93m x 2.04m) métal; Famille et type: Int. Simple: PP (0.93m x 2.04m) métal; ID du type: Int. Simple: PP (0.93m x 2.04m) métal; Type: Int. Simple: PP (0.93m x 2.04m) métal; ID hôte: Mur de base: A-mur parpaing 10; Hauteur sous linteau: 2.04 m
Contraintes - Hauteur de l'appui: 0 m; Niveau: Niveau: R-1
Cotes - Surface: 2.7053 m2; Volume: 0.093668 m3
Données d'identification - Sous-projet: Menuiseries INT; Identifiant: 114
Graphismes - Angle d'ouverture 2D fixe: no; Angle d'ouverture 3D: 45 deg
Phase de construction - Phase de création: Nouvelle construction

# IfcDoor: PP (0.93m x 2.04m) métal (2)
In: R-1
Type - OperationType: SINGLE_SWING_LEFT; ParameterTakesPrecedence: no; Sizeable: no; Material: AA-Blanc satiné, AA-Aluminium
Type - Int. Simple:PP (0.93m x 2.04m) métal:954203 - PanelOperation: SWINGING
Type - Autre - Catégorie: Portes; Nom de la famille: Int. Simple
Type - Construction - Fermeture du mur: Par hôte
Type - Cotes - Epaisseur: 0.04 m; Hauteur: 2.04 m; Largeur: 0.93 m
Type - Données d'identification - Marque de type: 37; Nom du type: PP (0.93m x 2.04m) métal; Sous-projet: Famille : Portes : Int. Simple
Type - Matériaux et finitions - Ajuster: AA-Aluminium; Image: AA-Aluminium; Panneau: AA-Aluminium; Poignée: AA-Blanc satiné
Type - Propriétés analytiques - Construction analytique: <Aucun>
Type - Texte - type porte: MI-p
OverallHeight: 2.09 m; OverallWidth: 1.03 m
Pset_DoorCommon - IsExternal: yes; Reference: Int. Simple:PP (0.93m x 2.04m) métal
Autre - Famille: Int. Simple: PP (0.93m x 2.04m) métal; Famille et type: Int. Simple: PP (0.93m x 2.04m) métal; Hauteur sous linteau: 2.04 m; ID du type: Int. Simple: PP (0.93m x 2.04m) métal; ID hôte: Mur de base: A-mur BA pierre 20 cm; Type: Int. Simple: PP (0.93m x 2.04m) métal
Contraintes - Hauteur de l'appui: 0 m; Niveau: Niveau: R-1
Cotes - Surface: 3.2168 m2; Volume: 0.111448 m3
Données d'identification - Sous-projet: Menuiseries INT
Graphismes - Angle d'ouverture 2D fixe: no; Angle d'ouverture 3D: 45 deg
Phase de construction - Phase de création: Nouvelle construction
Name (Int. Simple:PP (0.93m x 2.04m) métal:...) | Identifiant
954203 | 43
996439 | 62

# IfcDoor: PP (0.93m x 2.04m) métal, Int. Simple:PP (0.93m x 2.04m) métal:1286989
In: R-1
Type - OperationType: SINGLE_SWING_RIGHT; ParameterTakesPrecedence: no; Sizeable: no; Material: AA-Blanc satiné, AA-Aluminium
Type - Autre - Catégorie: Portes; Nom de la famille: Int. Simple
Type - Construction - Fermeture du mur: Par hôte
Type - Cotes - Epaisseur: 0.04 m; Hauteur: 2.04 m; Largeur: 0.93 m
Type - Données d'identification - Marque de type: 37; Nom du type: PP (0.93m x 2.04m) métal; Sous-projet: Famille : Portes : Int. Simple
Type - Matériaux et finitions - Ajuster: AA-Aluminium; Image: AA-Aluminium; Panneau: AA-Aluminium; Poignée: AA-Blanc satiné
Type - Propriétés analytiques - Construction analytique: <Aucun>
Type - Texte - type porte: MI-p
Type - Int. Simple:PP (0.93m x 2.04m) métal:1286989 - PanelOperation: SWINGING
OverallHeight: 2.09 m; OverallWidth: 1.26999 m
Pset_DoorCommon - IsExternal: yes; Reference: Int. Simple:PP (0.93m x 2.04m) métal
Autre - Famille: Int. Simple: PP (0.93m x 2.04m) métal; Famille et type: Int. Simple: PP (0.93m x 2.04m) métal; ID du type: Int. Simple: PP (0.93m x 2.04m) métal; ID hôte: Mur de base: A-mur BA pierre 20 cm; Type: Int. Simple: PP (0.93m x 2.04m) métal; Hauteur sous linteau: 2.04 m
Contraintes - Hauteur de l'appui: 0 m; Niveau: Niveau: R-1
Cotes - Surface: 3.2168 m2; Volume: 0.111448 m3
Données d'identification - Sous-projet: Menuiseries INT; Identifiant: 101; Variantes: Modèle de base
Graphismes - Angle d'ouverture 2D fixe: no; Angle d'ouverture 3D: 105 deg
Phase de construction - Phase de création: Nouvelle construction

# IfcDoor: PP (1.23m x 2.04m) métal, Int. Tierce:PP (1.23m x 2.04m) métal:1387787
In: R-1
Type - OperationType: DOUBLE_DOOR_SINGLE_SWING; ParameterTakesPrecedence: no; Sizeable: no; Material: Finition Peinture - Blanc satiné, AA-Aluminium
Type - Int. Tierce:PP (1.23m x 2.04m) métal:1387787 - PanelOperation: SWINGING
Type - Autre - Catégorie: Portes; Nom de la famille: Int. Tierce
Type - Construction - Fonction: Intérieur; Fermeture du mur: Par hôte
Type - Cotes - Epaisseur: 0.04 m; Hauteur: 2.04 m; Largeur: 1.23 m; Largeur du grand panneau: 0.9 m
Type - Données d'identification - Marque de type: 43; Nom du type: PP (1.23m x 2.04m) métal; Note d'identification: 15.03.02; Sous-projet: Famille : Portes : Int. Tierce
Type - Matériaux et finitions - Coffrage de finition: AA-Aluminium; Image: AA-Aluminium; Panneau: AA-Aluminium; Poignée: Finition Peinture - Blanc satiné
Type - Propriétés analytiques - Coefficient d'apport thermique solaire: 0.86; Coefficient de transfert de chaleur (U): 5.5617; Construction analytique: Grandes fenêtres à vitrage simple; Résistance thermique (R): 0.179801; Transmission de la lumière visible: 0.9
OverallHeight: 2.09 m; OverallWidth: 1.33 m
Pset_DoorCommon - IsExternal: no; Reference: Int. Tierce:PP (1.23m x 2.04m) métal; ThermalTransmittance: 5.5617 kg/K/s3
Autre - ID hôte: Mur de base: A-mur BA 20 cm; Famille: Int. Tierce: PP (1.23m x 2.04m) métal; Famille et type: Int. Tierce: PP (1.23m x 2.04m) métal; Hauteur sous linteau: 2.04 m; ID du type: Int. Tierce: PP (1.23m x 2.04m) métal; Type: Int. Tierce: PP (1.23m x 2.04m) métal
Contraintes - Hauteur de l'appui: 0 m; Niveau: Niveau: R-1
Cotes - Surface: 3.9929 m2; Volume: 0.138028 m3
Données d'identification - Sous-projet: Menuiseries INT; Identifiant: 108
Graphismes - Angle d'ouverture 2D fixe: yes; Angle d'ouverture 3D: 0 deg
Phase de construction - Phase de création: Nouvelle construction

# IfcFlowTerminal: 100 x 47 x 85 cm - Blanc (5)
Material: Métal - Chrome, Céramique - Blanc
Pset_DistributionFlowElementCommon - Reference: Lavabo sur console métallique:100 x 47 x 85 cm - Blanc
Autre - Catégorie: Appareils sanitaires; Famille: Lavabo sur console métallique: 100 x 47 x 85 cm - Blanc; Famille et type: Lavabo sur console métallique: 100 x 47 x 85 cm - Blanc; ID du type: Lavabo sur console métallique: 100 x 47 x 85 cm - Blanc; Type: Lavabo sur console métallique: 100 x 47 x 85 cm - Blanc
Contraintes - Décalage: 0 m; Se déplace avec les éléments voisins: no
Cotes - Surface: 0.941517 m2; Volume: 0.0263963 m3
Données d'identification - Sous-projet: Sous-projet 1
Phase de construction - Phase de création: Nouvelle construction
Autre(Type) - Catégorie: Appareils sanitaires; Nom de la famille: Lavabo sur console métallique
Cotes(Type) - Hauteur: 0.85 m; Largeur: 1 m; Profondeur: 0.47 m
Données d'identification(Type) - Nom du type: 100 x 47 x 85 cm - Blanc; Numéro OmniClass: 23.45.00.00; Sous-projet: Famille : Appareils sanitaires : Lavabo sur console métallique; Titre OmniClass: Sanitary, Laundry, and Cleaning Equipment
Matériaux et finitions(Type) - Bénitier: Céramique - Blanc; Console: Métal - Chrome
Name (Lavabo sur console métallique:100 x 47 x 85 cm - Blanc:...) | In | Niveau | Hôte | Identifiant | Variantes
1231482 | R-1 | Niveau: R-1 | Sol : A-dalle béton 13 cm | 30 | Modèle de base
1688235 | R-1 | Niveau: R-1 | Sol : A-dalle béton 13 cm | 62
1693240 | R+1 | Niveau: R+1 | Sol : A-carrelage sol | 66
2240314 | RDC | Niveau: RDC | Sol : A-sol souple | 71 | Modèle de base
2592611 | R+2 | Niveau: R+2 | Sol : A-carrelage sol | 92 | Modèle de base

# IfcFlowTerminal: 440mm x 350mm (4)
Material: Métal - Chrome poli, Porcelaine - Blanche
Pset_DistributionFlowElementCommon - Reference: Lavabo mural - 05:440mm x 350mm
Autre - Catégorie: Appareils sanitaires; Famille: Lavabo mural - 05: 440mm x 350mm; Famille et type: Lavabo mural - 05: 440mm x 350mm; ID du type: Lavabo mural - 05: 440mm x 350mm; Type: Lavabo mural - 05: 440mm x 350mm
Contraintes - Se déplace avec les éléments voisins: no
Cotes - Surface: 0.258851 m2; Volume: 0.00327224 m3
Données d'identification - Sous-projet: Sous-projet 1
Phase de construction - Phase de création: Nouvelle construction
Autre(Type) - Catégorie: Appareils sanitaires; Nom de la famille: Lavabo mural - 05
Données d'identification(Type) - Nom du type: 440mm x 350mm; Sous-projet: Famille : Appareils sanitaires : Lavabo mural - 05
Matériaux et finitions(Type) - Matériau - Evier: Porcelaine - Blanche; Matériau - Robinet: Métal - Chrome poli
Name (Lavabo mural - 05:440mm x 350mm:...) | In | Décalage (m) | Niveau | Hôte | Identifiant
1231483 | R-1 | 0 | Niveau: R-1 | Sol : A-dalle béton 13 cm | 31
1643411 | R+2 | 0.8 | Niveau: R+2 | Sol : A-carrelage sol | 59
2151840 | R+1 | 0.8 | Niveau: R+1 | Sol : A-carrelage sol | 81
2247821 | RDC | 0.8 | Niveau: RDC | Sol : A-carrelage sol | 88

# IfcFlowTerminal: 47 x 47 x 85 cm - Blanc 2, Lavabo sur console métallique:47 x 47 x 85 cm - Blanc 2:2521089
In: R+2
Material: Métal - Chrome, Céramique - Blanc
Pset_DistributionFlowElementCommon - Reference: Lavabo sur console métallique:47 x 47 x 85 cm - Blanc 2
Autre - Catégorie: Appareils sanitaires; Famille: Lavabo sur console métallique: 47 x 47 x 85 cm - Blanc 2; Famille et type: Lavabo sur console métallique: 47 x 47 x 85 cm - Blanc 2; ID du type: Lavabo sur console métallique: 47 x 47 x 85 cm - Blanc 2; Type: Lavabo sur console métallique: 47 x 47 x 85 cm - Blanc 2
Contraintes - Niveau: Niveau: R+2; Décalage: 0 m; Se déplace avec les éléments voisins: no; Hôte: Sol : A-carrelage sol
Cotes - Surface: 0.555959 m2; Volume: 0.0143906 m3
Données d'identification - Sous-projet: Sous-projet 1; Identifiant: 89; Variantes: Modèle de base
Phase de construction - Phase de création: Nouvelle construction
Autre(Type) - Catégorie: Appareils sanitaires; Nom de la famille: Lavabo sur console métallique
Cotes(Type) - Hauteur: 0.85 m; Largeur: 0.47 m; Profondeur: 0.47 m
Données d'identification(Type) - Sous-projet: Famille : Appareils sanitaires : Lavabo sur console métallique; Nom du type: 47 x 47 x 85 cm - Blanc 2; Numéro OmniClass: 23.45.00.00; Titre OmniClass: Sanitary, Laundry, and Cleaning Equipment
Matériaux et finitions(Type) - Bénitier: Céramique - Blanc; Console: Métal - Chrome

# IfcFlowTerminal: WC à réservoir (11)
Material: Porcelaine - Blanche, Métal - Chrome
Pset_DistributionFlowElementCommon - Reference: WC à réservoir:WC à réservoir
Autre - Catégorie: Appareils sanitaires; Famille: WC à réservoir: WC à réservoir; Famille et type: WC à réservoir: WC à réservoir; ID du type: WC à réservoir: WC à réservoir; Type: WC à réservoir: WC à réservoir
Contraintes - Se déplace avec les éléments voisins: no
Cotes - Surface: 1.0705 m2; Volume: 0.0431081 m3
Données d'identification - Sous-projet: Sous-projet 1
Phase de construction - Phase de création: Nouvelle construction
Autre(Type) - Catégorie: Appareils sanitaires; Nom de la famille: WC à réservoir
Données d'identification(Type) - Nom du type: WC à réservoir; Sous-projet: Famille : Appareils sanitaires : WC à réservoir
Matériaux et finitions(Type) - Matériau: Porcelaine - Blanche; Matériau de bouton: Métal - Chrome
Name (WC à réservoir:WC à réservoir:...) | In | Décalage (m) | Niveau | Hôte | Identifiant | Variantes
1231480 | R-1 | 0 | Niveau: R-1 | Sol : A-dalle béton 13 cm | 28 | Modèle de base
1231481 | R-1 | 0.04 | Niveau: R-1 | Niveau : R-1 | 29
1642789 | R+1 | 0 | Niveau: R+1 | Niveau : R+1 | 52 | Modèle de base
1643028 | R+1 | 0 | Niveau: R+1 | Sol : A-carrelage sol | 54
1643338 | R+2 | 0 | Niveau: R+2 | Sol : A-carrelage sol | 56 | Modèle de base
1689543 | R-1 | 0.04 | Niveau: R-1 | Niveau : R-1 | 63
2521262 | R+2 | 0 | Niveau: R+2 | Sol : A-carrelage sol | 90
2592610 | R+2 | 0 | Niveau: R+2 | Niveau : R+2 | 91 | Modèle de base
2603088 | RDC | 0 | Niveau: RDC | Sol : A-carrelage sol | 93 | Modèle de base
2603089 | RDC | 0 | Niveau: RDC | Sol : A-carrelage sol | 94 | Modèle de base
2603090 | RDC | 0 | Niveau: RDC | Sol : A-carrelage sol | 95 | Modèle de base

# IfcGroup: Groupe de modèles:PORTE MUR COULISSANT (2)
Autre - Catégorie: Groupes de modèles; Famille: Groupe de modèles: PORTE MUR COULISSANT; Famille et type: Groupe de modèles: PORTE MUR COULISSANT; ID du type: Groupe de modèles: PORTE MUR COULISSANT; Type: Groupe de modèles: PORTE MUR COULISSANT
Contraintes - Décalage du niveau de l'origine: 0 m; Niveau de référence: Niveau: RDC
Données d'identification - Sous-projet: Cloisons
Autre(Type) - Catégorie: Groupes de modèles; Nom de la famille: Groupe de modèles
Données d'identification(Type) - Sous-projet: Sous-projet 1; Nom du type: PORTE MUR COULISSANT
Name (Groupe de modèles:PORTE MUR COULISSANT:...)
2677156
2677416 | Données d'identification - Variantes: Modèle de base

# IfcGroup: Groupe de modèles:POTEAUX CLOISONS R+1, Groupe de modèles:POTEAUX CLOISONS R+1:2509806
Autre - Catégorie: Groupes de modèles; Famille: Groupe de modèles: POTEAUX CLOISONS R+1; Famille et type: Groupe de modèles: POTEAUX CLOISONS R+1; ID du type: Groupe de modèles: POTEAUX CLOISONS R+1; Type: Groupe de modèles: POTEAUX CLOISONS R+1
Contraintes - Décalage du niveau de l'origine: 0 m; Niveau de référence: Niveau: R+1
Données d'identification - Sous-projet: Cloisons; Variantes: Modèle de base
Autre(Type) - Catégorie: Groupes de modèles; Nom de la famille: Groupe de modèles
Données d'identification(Type) - Sous-projet: Sous-projet 1; Nom du type: POTEAUX CLOISONS R+1

# IfcGroup: Groupe de modèles:POTEAUX CLOISONS R+2, Groupe de modèles:POTEAUX CLOISONS R+2:2514951
Autre - Catégorie: Groupes de modèles; Famille: Groupe de modèles: POTEAUX CLOISONS R+2; Famille et type: Groupe de modèles: POTEAUX CLOISONS R+2; ID du type: Groupe de modèles: POTEAUX CLOISONS R+2; Type: Groupe de modèles: POTEAUX CLOISONS R+2
Contraintes - Décalage du niveau de l'origine: 0 m; Niveau de référence: Niveau: R+2
Données d'identification - Sous-projet: Cloisons; Variantes: Modèle de base
Autre(Type) - Catégorie: Groupes de modèles; Nom de la famille: Groupe de modèles
Données d'identification(Type) - Sous-projet: Sous-projet 1; Nom du type: POTEAUX CLOISONS R+2

# IfcGroup: Groupe de modèles:POTEAUX CLOISONS RDC, Groupe de modèles:POTEAUX CLOISONS RDC (membre exclu):1442762
Autre - Catégorie: Groupes de modèles; Famille: Groupe de modèles: POTEAUX CLOISONS RDC; Famille et type: Groupe de modèles: POTEAUX CLOISONS RDC; ID du type: Groupe de modèles: POTEAUX CLOISONS RDC; Type: Groupe de modèles: POTEAUX CLOISONS RDC
Contraintes - Décalage du niveau de l'origine: 0 m; Niveau de référence: Niveau: RDC
Données d'identification - Sous-projet: Cloisons
Autre(Type) - Catégorie: Groupes de modèles; Nom de la famille: Groupe de modèles
Données d'identification(Type) - Sous-projet: Sous-projet 1; Nom du type: POTEAUX CLOISONS RDC

# IfcGroup: Groupe de modèles:mur BTC R+2 (4)
Autre - Catégorie: Groupes de modèles; Famille: Groupe de modèles: mur BTC R+2; Famille et type: Groupe de modèles: mur BTC R+2; ID du type: Groupe de modèles: mur BTC R+2; Type: Groupe de modèles: mur BTC R+2
Contraintes - Décalage du niveau de l'origine: 0 m; Niveau de référence: Niveau: R+2
Données d'identification - Sous-projet: BTC
Autre(Type) - Catégorie: Groupes de modèles; Nom de la famille: Groupe de modèles
Données d'identification(Type) - Sous-projet: Sous-projet 1; Nom du type: mur BTC R+2
Name (Groupe de modèles:mur BTC R+2:...)
2029197
2029648 | Données d'identification - Variantes: Modèle de base
2029722
2029800 | Données d'identification - Variantes: Modèle de base

# IfcOpeningElement: Opening (75)
Name | In
Sol:A-isolant 2.5cm:327734:2 | R+1
Sol:A-isolant 2.5cm:327770:2 | R+2
Mur de base:A-cloison FC 10.5 cm:329743 | R+1 | Autre - Catégorie: Portes; Famille: Porte intérieur bois: PP (0.93m x 2.04m); Famille et type: Porte intérieur bois: PP (0.93m x 2.04m); Hauteur sous linteau: 2.04 m; ID du type: Porte intérieur bois: PP (0.93m x 2.04m); ID hôte: Mur de base: A-cloison FC 10.5 cm; Type: Porte intérieur bois: PP (0.93m x 2.04m); Contraintes - Hauteur de l'appui: 0 m; Niveau: Niveau: R+1; Cotes - Surface: 2.73088 m2; Volume: 0.094557 m3; Données d'identification - Identifiant: 26; Sous-projet: Menuiseries INT; Variantes: Modèle de base; Graphismes - Angle d'ouverture 2D fixe: no; Angle d'ouverture 3D: 45 deg; Phase de construction - Phase de création: Nouvelle construction
Sol:A-isolant 4.5 cm:348695:2 | RDC
Mur de base:A-cloison FC 10.5 cm:349321 | RDC | Autre - Catégorie: Portes; Famille: Porte intérieur bois: PP (0.93m x 2.04m); Famille et type: Porte intérieur bois: PP (0.93m x 2.04m); Hauteur sous linteau: 2.04 m; ID du type: Porte intérieur bois: PP (0.93m x 2.04m); ID hôte: Mur de base: A-cloison FC 10.5 cm; Type: Porte intérieur bois: PP (0.93m x 2.04m); Contraintes - Hauteur de l'appui: 0 m; Niveau: Niveau: RDC; Cotes - Surface: 2.73088 m2; Volume: 0.094557 m3; Données d'identification - Identifiant: 24; Sous-projet: Menuiseries INT; Variantes: Modèle de base; Graphismes - Angle d'ouverture 2D fixe: no; Angle d'ouverture 3D: 45 deg; Phase de construction - Phase de création: Nouvelle construction
Mur de base:A-cloison FC 10.5 cm:349321 | RDC | Autre - Catégorie: Portes; Famille: Porte intérieur bois: PP (0.93m x 2.04m); Famille et type: Porte intérieur bois: PP (0.93m x 2.04m); Hauteur sous linteau: 2.04 m; ID du type: Porte intérieur bois: PP (0.93m x 2.04m); ID hôte: Mur de base: Générique - Int. 70 mm; Type: Porte intérieur bois: PP (0.93m x 2.04m); Contraintes - Hauteur de l'appui: 0 m; Niveau: Niveau: RDC; Cotes - Surface: 2.55185 m2; Volume: 0.088334 m3; Données d'identification - Identifiant: 168; Sous-projet: Menuiseries INT; Variantes: Modèle de base; Graphismes - Angle d'ouverture 2D fixe: no; Angle d'ouverture 3D: 45 deg; Phase de construction - Phase de création: Nouvelle construction
Mur de base:A-cloison FC 10.5 cm:382112 | R+2 | Autre - Catégorie: Portes; Famille: Porte intérieur bois: PP (0.93m x 2.04m); Famille et type: Porte intérieur bois: PP (0.93m x 2.04m); Hauteur sous linteau: 2.04 m; ID du type: Porte intérieur bois: PP (0.93m x 2.04m); ID hôte: Mur de base: A-cloison FC 10.5 cm; Type: Porte intérieur bois: PP (0.93m x 2.04m); Contraintes - Hauteur de l'appui: 0 m; Niveau: Niveau: R+2; Cotes - Surface: 2.73088 m2; Volume: 0.094557 m3; Données d'identification - Identifiant: 27; Sous-projet: Menuiseries INT; Variantes: Modèle de base; Graphismes - Angle d'ouverture 2D fixe: no; Angle d'ouverture 3D: 45 deg; Phase de construction - Phase de création: Nouvelle construction
Mur de base:Générique - Int. 70 mm:550287:1 | R-1
Porte intérieur bois:PP (0.93m x 2.04m):2758900:1 | R+1
Porte intérieur bois:PP (0.93m x 2.04m):2560760:1 | R+1
Mur de base:Générique - Int. 70 mm:1231478 | R-1 | Autre - Catégorie: Portes; Famille: Porte intérieur bois: PP (0.73m x 2.04m); Famille et type: Porte intérieur bois: PP (0.73m x 2.04m); Hauteur sous linteau: 2.04 m; ID du type: Porte intérieur bois: PP (0.73m x 2.04m); ID hôte: Mur de base: Générique - Int. 70 mm; Type: Porte intérieur bois: PP (0.73m x 2.04m); Contraintes - Hauteur de l'appui: 0 m; Niveau: Niveau: R-1; Cotes - Surface: 2.11485 m2; Volume: 0.071524 m3; Données d'identification - Identifiant: 130; Sous-projet: Menuiseries INT; Graphismes - Angle d'ouverture 2D fixe: yes; Angle d'ouverture 3D: 90 deg; Phase de construction - Phase de création: Nouvelle construction
Mur de base:A-mur parpaing 10:1389426 | R-1 | Autre - Catégorie: Portes; Famille: Porte intérieur bois: PP (0.73m x 2.04m); Famille et type: Porte intérieur bois: PP (0.73m x 2.04m); Hauteur sous linteau: 2.04 m; ID du type: Porte intérieur bois: PP (0.73m x 2.04m); ID hôte: Mur de base: A-mur parpaing 10; Type: Porte intérieur bois: PP (0.73m x 2.04m); Contraintes - Hauteur de l'appui: 0 m; Niveau: Niveau: R-1; Cotes - Surface: 2.2623 m2; Volume: 0.076648 m3; Données d'identification - Identifiant: 137; Sous-projet: Menuiseries INT; Graphismes - Angle d'ouverture 2D fixe: yes; Angle d'ouverture 3D: 90 deg; Phase de construction - Phase de création: Nouvelle construction
Porte intérieur bois:PP (0.93m x 2.04m):2521086:1 | R+2
Mur de base:A-cloison FC 10.5 cm:1642588 | R+1 | Autre - Catégorie: Portes; Famille: Porte intérieur bois: PP (0.73m x 2.04m); Famille et type: Porte intérieur bois: PP (0.73m x 2.04m); Hauteur sous linteau: 2.04 m; ID du type: Porte intérieur bois: PP (0.73m x 2.04m); ID hôte: Mur de base: Générique - Int. 70 mm; Type: Porte intérieur bois: PP (0.73m x 2.04m); Contraintes - Hauteur de l'appui: 0 m; Niveau: Niveau: R+1; Cotes - Surface: 2.11485 m2; Volume: 0.071524 m3; Données d'identification - Identifiant: 190; Sous-projet: Menuiseries INT; Variantes: Modèle de base; Graphismes - Angle d'ouverture 2D fixe: no; Angle d'ouverture 3D: 90 deg; Phase de construction - Phase de création: Nouvelle construction
Mur de base:A-cloison FC 10.5 cm:1643187 | R+2 | Autre - Catégorie: Portes; Famille: Porte intérieur bois: PP (0.73m x 2.04m); Famille et type: Porte intérieur bois: PP (0.73m x 2.04m); Hauteur sous linteau: 2.04 m; ID du type: Porte intérieur bois: PP (0.73m x 2.04m); ID hôte: Mur de base: Générique - Int. 70 mm; Type: Porte intérieur bois: PP (0.73m x 2.04m); Contraintes - Hauteur de l'appui: 0 m; Niveau: Niveau: R+2; Cotes - Surface: 2.11485 m2; Volume: 0.071524 m3; Données d'identification - Identifiant: 191; Sous-projet: Menuiseries INT; Variantes: Modèle de base; Graphismes - Angle d'ouverture 2D fixe: no; Angle d'ouverture 3D: 90 deg; Phase de construction - Phase de création: Nouvelle construction
Mur de base:A-mur parpaing 20:2444873 | R-1 | Autre - Catégorie: Portes; Famille: Porte intérieur bois: PP (0.93m x 2.04m); Famille et type: Porte intérieur bois: PP (0.93m x 2.04m); Hauteur sous linteau: 2.04 m; ID du type: Porte intérieur bois: PP (0.93m x 2.04m); ID hôte: Mur de base: Générique - Int. 70 mm; Type: Porte intérieur bois: PP (0.93m x 2.04m); Contraintes - Hauteur de l'appui: 0 m; Niveau: Niveau: R-1; Cotes - Surface: 2.55185 m2; Volume: 0.088334 m3; Données d'identification - Identifiant: 36; Sous-projet: Menuiseries INT; Variantes: Modèle de base; Graphismes - Angle d'ouverture 2D fixe: yes; Angle d'ouverture 3D: 90 deg; Phase de construction - Phase de création: Nouvelle construction
Mur de base:A-mur parpaing 20:2446683:1 | R-1
Mur de base:A-mur parpaing 20:2446683 | R-1 | Autre - Catégorie: Portes; Famille: Porte intérieur bois: PP (0.93m x 2.04m); Famille et type: Porte intérieur bois: PP (0.93m x 2.04m); Hauteur sous linteau: 2.04 m; ID du type: Porte intérieur bois: PP (0.93m x 2.04m); ID hôte: Mur de base: Générique - Int. 70 mm; Type: Porte intérieur bois: PP (0.93m x 2.04m); Contraintes - Hauteur de l'appui: 0 m; Niveau: Niveau: R-1; Cotes - Surface: 2.55185 m2; Volume: 0.088334 m3; Données d'identification - Identifiant: 71; Sous-projet: Menuiseries INT; Variantes: Modèle de base; Graphismes - Angle d'ouverture 2D fixe: yes; Angle d'ouverture 3D: 90 deg; Phase de construction - Phase de création: Nouvelle construction
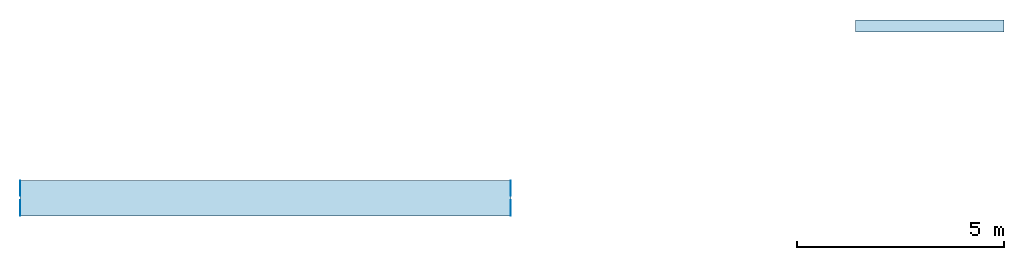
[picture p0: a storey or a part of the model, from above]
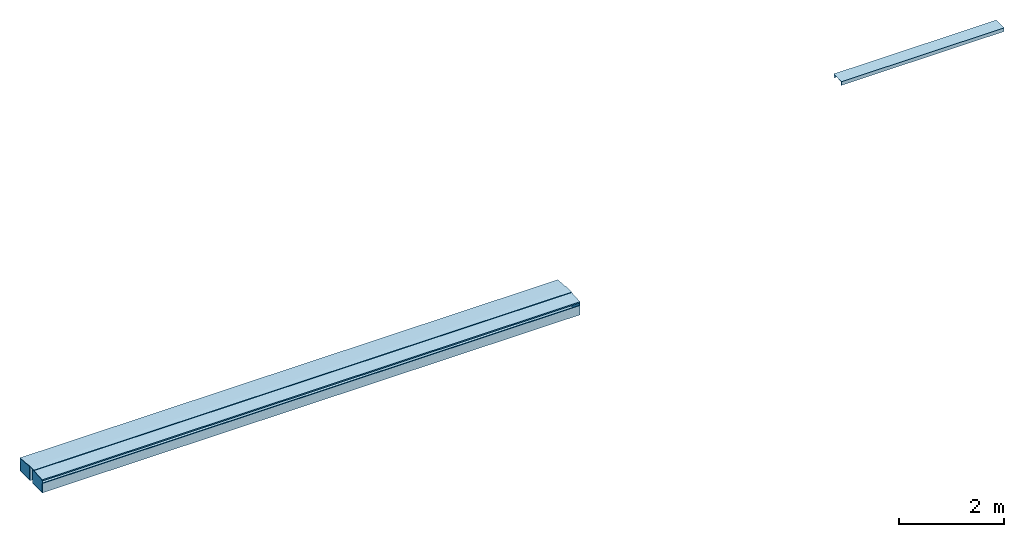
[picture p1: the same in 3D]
Properties of the parts of a building model (IFC2X3), part 4 of 5

# IfcOpeningElement: Opening (75)
Name | In
Mur de base:Générique - Int. 70 mm:2521087 | R+2 | Autre - Catégorie: Portes; Famille: Porte intérieur bois: PP (0.93m x 2.04m); Famille et type: Porte intérieur bois: PP (0.93m x 2.04m); Hauteur sous linteau: 2.04 m; ID du type: Porte intérieur bois: PP (0.93m x 2.04m); ID hôte: Mur de base: Générique - Int. 70 mm; Type: Porte intérieur bois: PP (0.93m x 2.04m); Contraintes - Hauteur de l'appui: 0 m; Niveau: Niveau: R+2; Cotes - Surface: 2.55185 m2; Volume: 0.088334 m3; Données d'identification - Identifiant: 186; Sous-projet: Menuiseries INT; Graphismes - Angle d'ouverture 2D fixe: no; Angle d'ouverture 3D: 45 deg; Phase de construction - Phase de création: Nouvelle construction
Porte intérieur bois:PP (0.93m x 2.04m):2521271:1 | R+2
Mur de base:A-plaque FC:2594001 | R+1 | Autre - Catégorie: Portes; Famille: Porte intérieur bois: PP (0.93m x 2.04m); Famille et type: Porte intérieur bois: PP (0.93m x 2.04m); Hauteur sous linteau: 2.04 m; ID du type: Porte intérieur bois: PP (0.93m x 2.04m); ID hôte: Mur de base: Générique - Int. 70 mm; Type: Porte intérieur bois: PP (0.93m x 2.04m); Contraintes - Hauteur de l'appui: 0 m; Niveau: Niveau: R+1; Cotes - Surface: 2.55185 m2; Volume: 0.088334 m3; Données d'identification - Identifiant: 162; Sous-projet: Menuiseries INT; Variantes: Modèle de base; Graphismes - Angle d'ouverture 2D fixe: no; Angle d'ouverture 3D: 45 deg; Phase de construction - Phase de création: Nouvelle construction
Mur de base:A-carrelage:2594845 | R+1 | Autre - Catégorie: Portes; Famille: Porte intérieur bois: PP (0.93m x 2.04m); Famille et type: Porte intérieur bois: PP (0.93m x 2.04m); Hauteur sous linteau: 2.04 m; ID du type: Porte intérieur bois: PP (0.93m x 2.04m); ID hôte: Mur de base: A-cloison FC 10.5 cm; Type: Porte intérieur bois: PP (0.93m x 2.04m); Contraintes - Hauteur de l'appui: 0 m; Niveau: Niveau: R+1; Cotes - Surface: 2.73088 m2; Volume: 0.094557 m3; Données d'identification - Identifiant: 26; Sous-projet: Menuiseries INT; Variantes: Modèle de base; Graphismes - Angle d'ouverture 2D fixe: no; Angle d'ouverture 3D: 45 deg; Phase de construction - Phase de création: Nouvelle construction
Mur de base:A-plaque FC:2596335 | R+2 | Autre - Catégorie: Portes; Famille: Porte intérieur bois: PP (0.93m x 2.04m); Famille et type: Porte intérieur bois: PP (0.93m x 2.04m); Hauteur sous linteau: 2.04 m; ID du type: Porte intérieur bois: PP (0.93m x 2.04m); ID hôte: Mur de base: Générique - Int. 70 mm; Type: Porte intérieur bois: PP (0.93m x 2.04m); Contraintes - Hauteur de l'appui: 0 m; Niveau: Niveau: R+2; Cotes - Surface: 2.55185 m2; Volume: 0.088334 m3; Données d'identification - Identifiant: 128; Sous-projet: Menuiseries INT; Graphismes - Angle d'ouverture 2D fixe: no; Angle d'ouverture 3D: 45 deg; Phase de construction - Phase de création: Nouvelle construction
Mur de base:A-carrelage:2596551 | R+2 | Autre - Catégorie: Portes; Famille: Porte intérieur bois: PP (0.93m x 2.04m); Famille et type: Porte intérieur bois: PP (0.93m x 2.04m); Hauteur sous linteau: 2.04 m; ID du type: Porte intérieur bois: PP (0.93m x 2.04m); ID hôte: Mur de base: Générique - Int. 70 mm; Type: Porte intérieur bois: PP (0.93m x 2.04m); Contraintes - Hauteur de l'appui: 0 m; Niveau: Niveau: R+2; Cotes - Surface: 2.55185 m2; Volume: 0.088334 m3; Données d'identification - Identifiant: 128; Sous-projet: Menuiseries INT; Graphismes - Angle d'ouverture 2D fixe: no; Angle d'ouverture 3D: 45 deg; Phase de construction - Phase de création: Nouvelle construction
Mur de base:A-carrelage:2596552 | R+2 | Autre - Catégorie: Portes; Famille: Porte intérieur bois: PP (0.93m x 2.04m); Famille et type: Porte intérieur bois: PP (0.93m x 2.04m); Hauteur sous linteau: 2.04 m; ID du type: Porte intérieur bois: PP (0.93m x 2.04m); ID hôte: Mur de base: Générique - Int. 70 mm; Type: Porte intérieur bois: PP (0.93m x 2.04m); Contraintes - Hauteur de l'appui: 0 m; Niveau: Niveau: R+2; Cotes - Surface: 2.55185 m2; Volume: 0.088334 m3; Données d'identification - Identifiant: 128; Sous-projet: Menuiseries INT; Graphismes - Angle d'ouverture 2D fixe: no; Angle d'ouverture 3D: 45 deg; Phase de construction - Phase de création: Nouvelle construction
Mur de base:A-carrelage:2596553 | R+2 | Autre - Catégorie: Portes; Famille: Porte intérieur bois: PP (0.93m x 2.04m); Famille et type: Porte intérieur bois: PP (0.93m x 2.04m); Hauteur sous linteau: 2.04 m; ID du type: Porte intérieur bois: PP (0.93m x 2.04m); ID hôte: Mur de base: A-cloison FC 10.5 cm; Type: Porte intérieur bois: PP (0.93m x 2.04m); Contraintes - Hauteur de l'appui: 0 m; Niveau: Niveau: R+2; Cotes - Surface: 2.73088 m2; Volume: 0.094557 m3; Données d'identification - Identifiant: 27; Sous-projet: Menuiseries INT; Variantes: Modèle de base; Graphismes - Angle d'ouverture 2D fixe: no; Angle d'ouverture 3D: 45 deg; Phase de construction - Phase de création: Nouvelle construction
Mur de base:A-carrelage:2596559 | R+2 | Autre - Catégorie: Portes; Famille: Porte intérieur bois: PP (0.73m x 2.04m); Famille et type: Porte intérieur bois: PP (0.73m x 2.04m); Hauteur sous linteau: 2.04 m; ID du type: Porte intérieur bois: PP (0.73m x 2.04m); ID hôte: Mur de base: Générique - Int. 70 mm; Type: Porte intérieur bois: PP (0.73m x 2.04m); Contraintes - Hauteur de l'appui: 0 m; Niveau: Niveau: R+2; Cotes - Surface: 2.11485 m2; Volume: 0.071524 m3; Données d'identification - Identifiant: 191; Sous-projet: Menuiseries INT; Graphismes - Angle d'ouverture 2D fixe: no; Angle d'ouverture 3D: 90 deg; Phase de construction - Phase de création: Nouvelle construction
Mur de base:A-carrelage:2596560 | R+2 | Autre - Catégorie: Portes; Famille: Porte intérieur bois: PP (0.73m x 2.04m); Famille et type: Porte intérieur bois: PP (0.73m x 2.04m); Hauteur sous linteau: 2.04 m; ID du type: Porte intérieur bois: PP (0.73m x 2.04m); ID hôte: Mur de base: Générique - Int. 70 mm; Type: Porte intérieur bois: PP (0.73m x 2.04m); Contraintes - Hauteur de l'appui: 0 m; Niveau: Niveau: R+2; Cotes - Surface: 2.11485 m2; Volume: 0.071524 m3; Données d'identification - Identifiant: 191; Sous-projet: Menuiseries INT; Graphismes - Angle d'ouverture 2D fixe: no; Angle d'ouverture 3D: 90 deg; Phase de construction - Phase de création: Nouvelle construction
Mur de base:A-carrelage:2602508 | RDC | Autre - Catégorie: Portes; Famille: Porte intérieur bois: PP (0.93m x 2.04m); Famille et type: Porte intérieur bois: PP (0.93m x 2.04m); Hauteur sous linteau: 2.04 m; ID du type: Porte intérieur bois: PP (0.93m x 2.04m); ID hôte: Mur de base: Générique - Int. 70 mm; Type: Porte intérieur bois: PP (0.93m x 2.04m); Contraintes - Hauteur de l'appui: 0 m; Niveau: Niveau: RDC; Cotes - Surface: 2.55185 m2; Volume: 0.088334 m3; Données d'identification - Identifiant: 168; Sous-projet: Menuiseries INT; Graphismes - Angle d'ouverture 2D fixe: no; Angle d'ouverture 3D: 45 deg; Phase de construction - Phase de création: Nouvelle construction
Mur de base:A-carrelage:2608546 | R-1 | Autre - Catégorie: Portes; Famille: Porte intérieur bois: PP (0.73m x 2.04m); Famille et type: Porte intérieur bois: PP (0.73m x 2.04m); Hauteur sous linteau: 2.04 m; ID du type: Porte intérieur bois: PP (0.73m x 2.04m); ID hôte: Mur de base: Générique - Int. 70 mm; Type: Porte intérieur bois: PP (0.73m x 2.04m); Contraintes - Hauteur de l'appui: 0 m; Niveau: Niveau: R-1; Cotes - Surface: 2.11485 m2; Volume: 0.071524 m3; Données d'identification - Identifiant: 130; Sous-projet: Menuiseries INT; Graphismes - Angle d'ouverture 2D fixe: yes; Angle d'ouverture 3D: 90 deg; Phase de construction - Phase de création: Nouvelle construction
Mur de base:A-carrelage:2608591 | R-1 | Autre - Catégorie: Portes; Famille: Porte intérieur bois: PP (0.73m x 2.04m); Famille et type: Porte intérieur bois: PP (0.73m x 2.04m); Hauteur sous linteau: 2.04 m; ID du type: Porte intérieur bois: PP (0.73m x 2.04m); ID hôte: Mur de base: Générique - Int. 70 mm; Type: Porte intérieur bois: PP (0.73m x 2.04m); Contraintes - Hauteur de l'appui: 0 m; Niveau: Niveau: R-1; Cotes - Surface: 2.11485 m2; Volume: 0.071524 m3; Données d'identification - Identifiant: 130; Sous-projet: Menuiseries INT; Graphismes - Angle d'ouverture 2D fixe: yes; Angle d'ouverture 3D: 90 deg; Phase de construction - Phase de création: Nouvelle construction
Mur de base:A-carrelage:2608637 | R-1 | Autre - Catégorie: Portes; Famille: Porte intérieur bois: PP (0.73m x 2.04m); Famille et type: Porte intérieur bois: PP (0.73m x 2.04m); Hauteur sous linteau: 2.04 m; ID du type: Porte intérieur bois: PP (0.73m x 2.04m); ID hôte: Mur de base: Générique - Int. 70 mm; Type: Porte intérieur bois: PP (0.73m x 2.04m); Contraintes - Hauteur de l'appui: 0 m; Niveau: Niveau: R-1; Cotes - Surface: 2.11485 m2; Volume: 0.071524 m3; Données d'identification - Identifiant: 130; Sous-projet: Menuiseries INT; Graphismes - Angle d'ouverture 2D fixe: yes; Angle d'ouverture 3D: 90 deg; Phase de construction - Phase de création: Nouvelle construction
Porte intérieur bois:PP (0.93m x 2.04m):2520686:1 | R+2
Mur de base:A-carrelage:2608680 | R-1 | Autre - Catégorie: Portes; Famille: Porte intérieur bois: PP (0.73m x 2.04m); Famille et type: Porte intérieur bois: PP (0.73m x 2.04m); Hauteur sous linteau: 2.04 m; ID du type: Porte intérieur bois: PP (0.73m x 2.04m); ID hôte: Mur de base: Générique - Int. 70 mm; Type: Porte intérieur bois: PP (0.73m x 2.04m); Contraintes - Hauteur de l'appui: 0 m; Niveau: Niveau: R-1; Cotes - Surface: 2.11485 m2; Volume: 0.071524 m3; Données d'identification - Identifiant: 130; Sous-projet: Menuiseries INT; Graphismes - Angle d'ouverture 2D fixe: yes; Angle d'ouverture 3D: 90 deg; Phase de construction - Phase de création: Nouvelle construction
Mur de base:A-carrelage:2777611 | R-1 | Autre - Catégorie: Portes; Famille: Porte intérieur bois: PP (0.73m x 2.04m); Famille et type: Porte intérieur bois: PP (0.73m x 2.04m); Hauteur sous linteau: 2.04 m; ID du type: Porte intérieur bois: PP (0.73m x 2.04m); ID hôte: Mur de base: A-mur parpaing 10; Type: Porte intérieur bois: PP (0.73m x 2.04m); Contraintes - Hauteur de l'appui: 0 m; Niveau: Niveau: R-1; Cotes - Surface: 2.2623 m2; Volume: 0.076648 m3; Données d'identification - Identifiant: 137; Sous-projet: Menuiseries INT; Variantes: Modèle de base; Graphismes - Angle d'ouverture 2D fixe: yes; Angle d'ouverture 3D: 90 deg; Phase de construction - Phase de création: Nouvelle construction
Mur de base:A-carrelage:2778549 | R-1 | Autre - Catégorie: Portes; Famille: Porte intérieur bois: PP (0.73m x 2.04m); Famille et type: Porte intérieur bois: PP (0.73m x 2.04m); Hauteur sous linteau: 2.04 m; ID du type: Porte intérieur bois: PP (0.73m x 2.04m); ID hôte: Mur de base: A-mur parpaing 10; Type: Porte intérieur bois: PP (0.73m x 2.04m); Contraintes - Hauteur de l'appui: 0 m; Niveau: Niveau: R-1; Cotes - Surface: 2.2623 m2; Volume: 0.076648 m3; Données d'identification - Identifiant: 137; Sous-projet: Menuiseries INT; Variantes: Modèle de base; Graphismes - Angle d'ouverture 2D fixe: yes; Angle d'ouverture 3D: 90 deg; Phase de construction - Phase de création: Nouvelle construction
Porte intérieur bois:PP (0.93m x 2.04m):2270242:1 | R+1
Porte intérieur bois:PP (0.93m x 2.04m):351249:1 | R+1
Porte intérieur bois:PP (0.93m x 2.04m):2261362:1 | R+1
Porte intérieur bois:PP (0.93m x 2.04m):340214:1 | R+1
Porte intérieur bois:PP (0.93m x 2.04m):351049:1 | RDC
Porte intérieur bois:PP (0.93m x 2.04m):350800:1 | RDC
Porte intérieur bois:PP (0.93m x 2.04m):349355:1 | RDC
Porte intérieur bois:PP (0.93m x 2.04m):759675:1 | RDC
Porte intérieur bois:PP (0.93m x 2.04m):382125:1 | R+2
Porte intérieur bois:PP (0.93m x 2.04m):382130:1 | R+2
Porte intérieur bois:PP (0.93m x 2.04m):892398:1 | R-1
Porte intérieur bois:PP (0.93m x 2.04m):1014764:1 | R-1
Porte extérieur + naco RDC:PP (0.93m x 2.04m):2242261:1 | RDC
Porte extérieur + naco R+1:PP (0.93m x 2.04m):691484:1 | R+1
Coulissante - Apparente:1.4m x 2.1m:1643670:1 | R+2
Porte extérieur + naco:PP (0.93m x 2.04m):691498:1 | R+2
Porte intérieur bois:PP (0.93m x 2.04m):885262:1 | R+1
Porte intérieur bois:PP (0.93m x 2.04m):885306:1 | R+2
Porte intérieur bois:PP (0.93m x 2.04m):2264024:1 | R+1
Porte intérieur bois:PP (0.93m x 2.04m):1231486:1 | R-1
Porte intérieur bois:PP (0.93m x 2.04m):1689171:1 | R-1
Porte intérieur bois:PP (0.93m x 2.04m):1643345:1 | R+2
Porte intérieur bois:PP (0.73m x 2.04m):2592781:1 | R+2
Porte intérieur bois:PP (0.73m x 2.04m):1643992:1 | R-1
Porte intérieur bois:PP (0.83m x 2.04m):1687137:1 | R-1
Porte intérieur bois:PP (0.73m x 2.04m):1689552:1 | R-1
Porte intérieur bois:PP (0.73m x 2.04m):1689553:1 | R-1
Porte intérieur bois:PP (0.93m x 2.04m):1689555:1 | R-1
Porte intérieur bois:PP (0.93m x 2.04m):2171205:1 | R+1
Porte intérieur bois:PP (0.73m x 2.04m):2592097:1 | R+1
Porte intérieur bois:PP (0.93m x 2.04m):2242073:1 | RDC
Porte intérieur bois:PP (0.93m x 2.04m):2247722:1 | RDC
Porte intérieur bois:PP (0.73m x 2.04m):2247726:1 | RDC
Porte intérieur bois:PP (0.73m x 2.04m):2247725:1 | RDC
Porte intérieur bois:PP (0.93m x 2.04m):2262082:1 | R+1
Porte intérieur bois:PP (0.93m x 2.04m):2261478:1 | R+1
Porte intérieur bois:PP (0.93m x 2.04m):2262081:1 | R+1
Porte intérieur bois:PP (0.93m x 2.04m):2250794:1 | R+1
Mur de base:A-cloison CP 11.6 cm:2267714 | RDC

# IfcPlate: GRILLE AVEC PORTE, GRILLE AVEC PORTE:GRILLE AVEC PORTE:1536323
In: R-1
Type - ElementType: GRILLE AVEC PORTE; Material: AA-Tôle déployée, AA-Aluminium
Type - Autre - Catégorie: Raidisseurs; Nom de la famille: GRILLE AVEC PORTE
Type - Données d'identification - Sous-projet: Menuiseries EXT; Nom du type: GRILLE AVEC PORTE
Pset_PlateCommon - LoadBearing: yes; IsExternal: no; Reference: GRILLE AVEC PORTE:GRILLE AVEC PORTE
Autre - Famille: GRILLE AVEC PORTE: GRILLE AVEC PORTE; Famille et type: GRILLE AVEC PORTE: GRILLE AVEC PORTE; ID du type: GRILLE AVEC PORTE: GRILLE AVEC PORTE; Type: GRILLE AVEC PORTE: GRILLE AVEC PORTE
Contraintes - Se déplace avec les éléments voisins: no; Elévation: 0 m
Cotes - Surface: 13.4401 m2; Volume: 0.183692 m3
Données d'identification - Variantes: Modèle de base
Phase de construction - Phase de création: Nouvelle construction

# IfcPlate: GRILLE AVEC PORTE, GRILLE AVEC PORTE1:GRILLE AVEC PORTE:1641234
In: R-1
Type - ElementType: GRILLE AVEC PORTE; Material: AA-Tôle déployée, AA-Aluminium
Type - Autre - Catégorie: Raidisseurs; Nom de la famille: GRILLE AVEC PORTE1
Type - Données d'identification - Sous-projet: Menuiseries EXT; Nom du type: GRILLE AVEC PORTE
Pset_PlateCommon - LoadBearing: yes; IsExternal: no; Reference: GRILLE AVEC PORTE1:GRILLE AVEC PORTE
Autre - Famille: GRILLE AVEC PORTE1: GRILLE AVEC PORTE; Famille et type: GRILLE AVEC PORTE1: GRILLE AVEC PORTE; ID du type: GRILLE AVEC PORTE1: GRILLE AVEC PORTE; Type: GRILLE AVEC PORTE1: GRILLE AVEC PORTE
Contraintes - Se déplace avec les éléments voisins: no; Elévation: 0 m
Cotes - Surface: 13.027 m2; Volume: 0.163038 m3
Phase de construction - Phase de création: Nouvelle construction

# IfcRailing: Garde-corps:Au Mur (2)
In: R-1
Material: Pin (1)
Pset_RailingCommon - IsExternal: no; Reference: Garde-corps:Au Mur; Height: 0.9 m
Autre - Catégorie: Garde-corps; Famille: Garde-corps: Au Mur; Famille et type: Garde-corps: Au Mur; ID du type: Garde-corps: Au Mur; Type: Garde-corps: Au Mur
Contraintes - Décalage inférieur: 0 m; Décalage à partir de la trajectoire: -0.05 m
Données d'identification - Sous-projet: Sous-projet 1; Variantes: Modèle de base
Phase de construction - Phase de création: Nouvelle construction
Autre(Type) - Catégorie: Garde-corps; Nom de la famille: Garde-corps
Construction(Type) - Connexion des traverses: Ajuster; Décalage des barreaux: 0 m; Hauteur du garde-corps: 0 m; Joints d'angle: Ajouter des segments verticaux/horizontaux; Joints tangents: Prolonger la traverse jusqu'à; Réglage de la hauteur du palier: 0 m; Utiliser le réglage de la hauteur du palier: no
Données d'identification(Type) - Nom du type: Au Mur; Sous-projet: Type de garde-corps
Main courante 1(Type) - Décalage latéral: 0.120609 m; Hauteur: 0.9 m; Position: Gauche; Type: Type de main courante: Elliptique - Montage mural
Main courante 2(Type) - Position: Aucune
Traverse haute(Type) - Hauteur: 0.9 m; Utiliser une traverse haute: no
Name (Garde-corps:Au Mur:...) | Longueur (m)
958934 | 10.4188
959549 | 10.4266

# IfcRoof: Toit de base:Toit toile tendue:632751 (6)
In: Couverture
Material: AA-toile tendue
Pset_RoofCommon - IsExternal: yes; Reference: Toit de base:Toit toile tendue
Autre - Catégorie: Toits; Famille: Toit de base: Toit toile tendue; Famille et type: Toit de base: Toit toile tendue; ID du type: Toit de base: Toit toile tendue; Type: Toit de base: Toit toile tendue
Construction - Coupe en chevron: Coupe verticale; Profondeur du bord de toiture: 0 m
Contraintes - Lié au volume: no; Limite de pièce: yes; Décalage de niveau: 0.476445 m; Niveau de référence: Niveau: Couverture; Plan de construction: <non associé>
Cotes - Epaisseur: 0.01 m
Données d'identification - Sous-projet: Sous-projet 1
Phase de construction - Phase de création: Nouvelle construction
Autre(Type) - Catégorie: Toits; Nom de la famille: Toit de base
Construction(Type) - Epaisseur par défaut: 0.01 m
Données d'identification(Type) - Nom du type: Toit toile tendue; Sous-projet: Types de toits
Graphismes(Type) - Couleur vue détail faible: 0
Propriétés analytiques(Type) - Rugosité: 3; Coefficient d'absorbance: 0.7; Coefficient de transfert de chaleur (U): 1620; Masse thermique: 40000; Résistance thermique (R): 0.000617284
Name (Toit de base:Toit toile tendue:...) | TotalArea (m2) = Surface (m2) | ProjectedArea (m2) | Début de l'extrusion (m) | Fin de l'extrusion (m) | Volume (m3)
1708758 | 24.4267 | 24.3306 | -0.21 | 3.79 | 0.244267 | Données d'identification - Variantes: Modèle de base
1708767 | 13.7547 | 13.6862 | 0.07 | 4.07 | 0.137547 | Données d'identification - Variantes: Modèle de base
1708771 | 13.515 | 13.4473 | -0.21 | 3.79 | 0.13515
1708775 | 15.5419 | 15.4688 | 3.99816e-07 | 3.79 | 0.155419 | Données d'identification - Variantes: Modèle de base
1708779 | 17.8833 | 17.8019 | 0.07 | 4.07 | 0.178833
1708783 | 9.23479 | 9.18469 | 0.07 | 3.86 | 0.0923478

# IfcRoof: coffre toile rétractable1:coffre toile rétractable:1708850, coffre toile rétractable1:coffre toile rétractable:1708852
In: Toiture
Material: AA-Aluminium
Pset_RoofCommon - IsExternal: yes; Reference: coffre toile rétractable1:coffre toile rétractable; TotalArea: 0.214179 m2
Autre - Catégorie: Toits; Famille: coffre toile rétractable1: coffre toile rétractable; Famille et type: coffre toile rétractable1: coffre toile rétractable; ID du type: coffre toile rétractable1: coffre toile rétractable; Type: coffre toile rétractable1: coffre toile rétractable
Contraintes - Limite de pièce: yes; Se déplace avec les éléments voisins: no; Elévation: 0.476445 m
Cotes - Surface: 0.214179 m2; Volume: 0.00187647 m3
Données d'identification - Sous-projet: Sous-projet 1; Variantes: Modèle de base
Phase de construction - Phase de création: Nouvelle construction
Autre(Type) - Catégorie: Toits; Nom de la famille: coffre toile rétractable1
Données d'identification(Type) - Sous-projet: Sous-projet 1; Nom du type: coffre toile rétractable

# IfcRoof: coffre toile rétractable2:coffre toile rétractable:1708874, coffre toile rétractable2:coffre toile rétractable:1708876
In: Toiture
Material: AA-Aluminium
Pset_RoofCommon - IsExternal: yes; Reference: coffre toile rétractable2:coffre toile rétractable; TotalArea: 0.214179 m2
Autre - Catégorie: Toits; Famille: coffre toile rétractable2: coffre toile rétractable; Famille et type: coffre toile rétractable2: coffre toile rétractable; ID du type: coffre toile rétractable2: coffre toile rétractable; Type: coffre toile rétractable2: coffre toile rétractable
Contraintes - Limite de pièce: yes; Se déplace avec les éléments voisins: no; Elévation: 0.476445 m
Cotes - Surface: 0.214179 m2; Volume: 0.00187647 m3
Données d'identification - Sous-projet: Sous-projet 1
Phase de construction - Phase de création: Nouvelle construction
Autre(Type) - Catégorie: Toits; Nom de la famille: coffre toile rétractable2
Données d'identification(Type) - Sous-projet: Sous-projet 1; Nom du type: coffre toile rétractable

# IfcRoof: coffre toile rétractable:coffre toile rétractable:1708845, coffre toile rétractable:coffre toile rétractable:1708847
In: Toiture
Material: AA-Aluminium
Pset_RoofCommon - IsExternal: yes; Reference: coffre toile rétractable:coffre toile rétractable; TotalArea: 0.0280214 m2
Autre - Catégorie: Toits; Famille: coffre toile rétractable: coffre toile rétractable; Famille et type: coffre toile rétractable: coffre toile rétractable; ID du type: coffre toile rétractable: coffre toile rétractable; Type: coffre toile rétractable: coffre toile rétractable
Contraintes - Limite de pièce: yes; Se déplace avec les éléments voisins: no; Elévation: 0.476445 m
Cotes - Surface: 0.0280214 m2; Volume: 0.331577 m3
Données d'identification - Sous-projet: Sous-projet 1; Variantes: Modèle de base
Phase de construction - Phase de création: Nouvelle construction
Autre(Type) - Catégorie: Toits; Nom de la famille: coffre toile rétractable
Données d'identification(Type) - Sous-projet: Sous-projet 1; Nom du type: coffre toile rétractable

# IfcRoof: couvertine25:couvertine:2178160, couvertine25:couvertine:2178162
In: Toiture
Material: AA-Aluminium
Pset_RoofCommon - IsExternal: yes; Reference: couvertine25:couvertine; TotalArea: 0.00141589 m2
Autre - Catégorie: Toits; Famille: couvertine25: couvertine; Famille et type: couvertine25: couvertine; ID du type: couvertine25: couvertine; Type: couvertine25: couvertine
Contraintes - Limite de pièce: yes; Se déplace avec les éléments voisins: no; Elévation: 3.72975 m
Cotes - Surface: 0.00141589 m2; Volume: 0.00506888 m3
Données d'identification - Sous-projet: Sous-projet 1; Variantes: Modèle de base
Phase de construction - Phase de création: Nouvelle construction
Autre(Type) - Catégorie: Toits; Nom de la famille: couvertine25
Données d'identification(Type) - Sous-projet: Sous-projet 1; Nom du type: couvertine

# IfcSlab: Sol:A-BA13 12.5mm (11)
PredefinedType: FLOOR; Material: AA-fermacell peint 0.0125 m
Pset_SlabCommon - IsExternal: yes; LoadBearing: no; Reference: Sol:A-BA13 12.5mm
Autre - Catégorie: Sols; Famille: Sol: A-BA13 12.5mm; Famille et type: Sol: A-BA13 12.5mm; ID du type: Sol: A-BA13 12.5mm; Type: Sol: A-BA13 12.5mm
Contraintes - Lié au volume: no; Limite de pièce: yes
Cotes - Epaisseur: 0.0125 m
Données d'identification - Sous-projet: Sous-projet 1
Phase de construction - Phase de création: Nouvelle construction
Structure - Activer le modèle analytique: no; Structure: no
Autre(Type) - Catégorie: Sols; Nom de la famille: Sol
Construction(Type) - Fonction: Extérieur; Epaisseur par défaut: 0.0125 m
Données d'identification(Type) - Sous-projet: Types de sols; Nom du type: A-BA13 12.5mm
Graphismes(Type) - Couleur vue détail faible: 0; Motif vue détail faible: Bois - Type 1
Matériaux et finitions(Type) - Matériau structurel: AA-fermacell peint
Propriétés analytiques(Type) - Rugosité: 3; Coefficient d'absorbance: 0.7
Name (Sol:A-BA13 12.5mm:...) | In | Niveau | Décalage par rapport au niveau (m) | Elévation à la base (m) | Elévation en haut (m) | Périmètre (m) | Surface (m2) | Volume (m3)
1261782 | R+1 | Niveau: R+1 | 2.6725 | 6.93 | 6.9425 | 24.4602 | 14.2595 | 0.178275
1261782:2 | R+1 | Niveau: R+1 | 2.6725 | 6.93 | 6.9425 | 24.4602 | 14.2595 | 0.178275
1261863 | RDC | Niveau: RDC | 3.3825 | 3.37 | 3.3825 | 14.3502 | 12.4524 | 0.155655 | Pset_SlabCommon - PitchAngle: 0 deg
1261911 | R+2 | Niveau: R+2 | 2.4125 | 10.23 | 10.2425 | 12.8302 | 9.36616 | 0.117108 | Pset_SlabCommon - PitchAngle: 0 deg
1391274 | R-1 | Niveau: R-1 | 3.4225 | -1.21 | -1.1975 | 39.0489 | 31.8918 | 0.398648 | Données d'identification - Variantes: Modèle de base
1391274:2 | R-1 | Niveau: R-1 | 3.4225 | -1.21 | -1.1975 | 39.0489 | 31.8918 | 0.398648 | Données d'identification - Variantes: Modèle de base
1391274:3 | R-1 | Niveau: R-1 | 3.4225 | -1.21 | -1.1975 | 39.0489 | 31.8918 | 0.398648 | Données d'identification - Variantes: Modèle de base
2055474 | R-1 | Niveau: R-1 | 3.4225 | -1.21 | -1.1975 | 65.9087 | 62.3675 | 0.779594
2055474:2 | R-1 | Niveau: R-1 | 3.4225 | -1.21 | -1.1975 | 65.9087 | 62.3675 | 0.779594
2055474:3 | R-1 | Niveau: R-1 | 3.4225 | -1.21 | -1.1975 | 65.9087 | 62.3675 | 0.779594
2055474:4 | R-1 | Niveau: R-1 | 3.4225 | -1.21 | -1.1975 | 65.9087 | 62.3675 | 0.779594

# IfcSlab: Sol:A-carrelage sol (6)
PredefinedType: FLOOR; Material: AA-sol carrelage 0.01 m
Pset_SlabCommon - IsExternal: no; LoadBearing: no; Reference: Sol:A-carrelage sol
Autre - Catégorie: Sols; Famille: Sol: A-carrelage sol; Famille et type: Sol: A-carrelage sol; ID du type: Sol: A-carrelage sol; Type: Sol: A-carrelage sol
Contraintes - Lié au volume: no; Limite de pièce: yes
Cotes - Epaisseur: 0.01 m
Données d'identification - Sous-projet: Sous-projet 1
Phase de construction - Phase de création: Nouvelle construction
Structure - Activer le modèle analytique: no; Structure: no
Autre(Type) - Catégorie: Sols; Nom de la famille: Sol
Construction(Type) - Fonction: Intérieur; Epaisseur par défaut: 0.01 m
Données d'identification(Type) - Sous-projet: Types de sols; Nom du type: A-carrelage sol
Graphismes(Type) - Couleur vue détail faible: 0
Matériaux et finitions(Type) - Matériau structurel: AA-sol carrelage
Propriétés analytiques(Type) - Rugosité: 3; Coefficient d'absorbance: 0.7
Name (Sol:A-carrelage sol:...) | In | PitchAngle (deg) | Décalage par rapport au niveau (m) | Niveau | Elévation à la base (m) | Elévation en haut (m) | Périmètre (m) | Surface (m2) | Volume (m3)
382119 | R+2 | 0 | 0 | Niveau: R+2 | 7.82 | 7.83 | 13.3882 | 10.6979 | 0.106979
1004562 | R+1 | 0 | 0 | Niveau: R+1 | 4.26 | 4.27 | 13.3882 | 10.6979 | 0.106979 | Données d'identification - Variantes: Modèle de base
1308562 | R-1 |  | 0.01 | Niveau: R-1 | -4.62 | -4.61 | 46.7708 | 65.9915 | 0.659915
1308562:2 | R-1 |  | 0.01 | Niveau: R-1 | -4.62 | -4.61 | 46.7708 | 65.9915 | 0.659915
2241800 | RDC | 0 | 0 | Niveau: RDC | -0.01 | 0 | 14.8282 | 13.6458 | 0.136458 | Données d'identification - Variantes: Modèle de base
2521081 | R+2 | 0 | 0 | Niveau: R+2 | 7.82 | 7.83 | 9.72211 | 5.65095 | 0.0565095 | Données d'identification - Variantes: Modèle de base

# IfcSlab: Sol:A-isolant 2.5cm (3)
PredefinedType: FLOOR; Material: AA-isolant plancher 0.025 m
Pset_SlabCommon - Reference: Sol:A-isolant 2.5cm; IsExternal: yes; LoadBearing: yes
Autre - Catégorie: Sols; Famille: Sol: A-isolant 2.5cm; Famille et type: Sol: A-isolant 2.5cm; ID du type: Sol: A-isolant 2.5cm; Type: Sol: A-isolant 2.5cm
Contraintes - Décalage par rapport au niveau: -0.01 m; Lié au volume: no; Limite de pièce: yes
Cotes - Epaisseur: 0.025 m; Epaisseur du porteur: 0.025 m
Données d'identification - Sous-projet: Sous-projet 1; Variantes: Modèle de base
Phase de construction - Phase de création: Nouvelle construction
Structure - Activer le modèle analytique: yes; Enrobage d'armature - Autres faces: Paramètres de l'enrobage d'armature: Enrobage d'armature 1; Enrobage d'armature - Face inférieure: Paramètres de l'enrobage d'armature: Enrobage d'armature 1; Enrobage d'armature - Face supérieure: Paramètres de l'enrobage d'armature: Enrobage d'armature 1; Structure: yes
Autre(Type) - Catégorie: Sols; Nom de la famille: Sol
Construction(Type) - Epaisseur par défaut: 0.025 m; Fonction: Extérieur
Données d'identification(Type) - Nom du type: A-isolant 2.5cm; Sous-projet: Types de sols
Graphismes(Type) - Couleur vue détail faible: 0; Motif vue détail faible: Bois - Type 1
Matériaux et finitions(Type) - Matériau structurel: AA-isolant plancher
Propriétés analytiques(Type) - Coefficient d'absorbance: 0.7; Rugosité: 3
Name (Sol:A-isolant 2.5cm:...) | In | Niveau | Elévation à la base (m) = Elévation au niveau du noyau inférieur (m) = Etude de l'élévation à la base (m) | Elévation au niveau du noyau supérieur (m) = Elévation en haut (m) = Etude de l'élévation en haut (m) | Périmètre (m) | Surface (m2) | Volume (m3)
327734 | R+1 | Niveau: R+1 | 4.235 | 4.26 | 121.465 | 315.988 | 7.89971
327734:2 | R+1 | Niveau: R+1 | 4.235 | 4.26 | 121.465 | 315.988 | 7.89971
327770 | R+2 | Niveau: R+2 | 7.795 | 7.82 | 62.2903 | 154.827 | 3.87068

# IfcSlab: Sol:A-isolant 4.5 cm (2)
In: RDC
PredefinedType: FLOOR; Material: AA-isolant plancher 0.045 m
Pset_SlabCommon - IsExternal: yes; LoadBearing: yes; Reference: Sol:A-isolant 4.5 cm
Autre - Catégorie: Sols; Famille: Sol: A-isolant 4.5 cm; Famille et type: Sol: A-isolant 4.5 cm; ID du type: Sol: A-isolant 4.5 cm; Type: Sol: A-isolant 4.5 cm
Contraintes - Lié au volume: no; Limite de pièce: yes; Décalage par rapport au niveau: -0.01 m; Niveau: Niveau: RDC
Cotes - Elévation à la base: -0.055 m; Elévation au niveau du noyau inférieur: -0.055 m; Elévation au niveau du noyau supérieur: -0.01 m; Elévation en haut: -0.01 m; Epaisseur: 0.045 m; Epaisseur du porteur: 0.045 m; Etude de l'élévation à la base: -0.055 m; Etude de l'élévation en haut: -0.01 m
Données d'identification - Sous-projet: Sous-projet 1; Variantes: Modèle de base
Phase de construction - Phase de création: Nouvelle construction
Structure - Activer le modèle analytique: yes; Enrobage d'armature - Autres faces: Paramètres de l'enrobage d'armature: Enrobage d'armature 1; Enrobage d'armature - Face inférieure: Paramètres de l'enrobage d'armature: Enrobage d'armature 1; Enrobage d'armature - Face supérieure: Paramètres de l'enrobage d'armature: Enrobage d'armature 1; Structure: yes
Autre(Type) - Catégorie: Sols; Nom de la famille: Sol
Construction(Type) - Fonction: Extérieur; Epaisseur par défaut: 0.045 m
Données d'identification(Type) - Sous-projet: Types de sols; Nom du type: A-isolant 4.5 cm
Graphismes(Type) - Couleur vue détail faible: 0; Motif vue détail faible: Bois - Type 1
Matériaux et finitions(Type) - Matériau structurel: AA-isolant plancher
Propriétés analytiques(Type) - Rugosité: 3; Coefficient d'absorbance: 0.7
Name (Sol:A-isolant 4.5 cm:...) | Périmètre (m) | Surface (m2) | Volume (m3)
348695 | 70.1145 | 187.437 | 8.43465
351882 | 49.4503 | 128.037 | 5.76165 | Pset_SlabCommon - PitchAngle: 0 deg

# IfcSlab: Sol:A-isolant 8 cm (2)
In: R+2
PredefinedType: FLOOR; Material: AA-isolant plancher 0.08 m
Pset_SlabCommon - IsExternal: yes; LoadBearing: no; Reference: Sol:A-isolant 8 cm
Autre - Catégorie: Sols; Famille: Sol: A-isolant 8 cm; Famille et type: Sol: A-isolant 8 cm; ID du type: Sol: A-isolant 8 cm; Type: Sol: A-isolant 8 cm
Contraintes - Lié au volume: no; Limite de pièce: yes; Niveau: Niveau: R+2; Décalage par rapport au niveau: -0.22 m
Cotes - Elévation à la base: 7.53 m; Elévation en haut: 7.61 m; Epaisseur: 0.08 m; Périmètre: 72.0559 m; Surface: 160.236 m2; Volume: 12.8189 m3
Données d'identification - Sous-projet: Sous-projet 1
Phase de construction - Phase de création: Nouvelle construction
Structure - Activer le modèle analytique: no; Structure: no
Autre(Type) - Catégorie: Sols; Nom de la famille: Sol
Construction(Type) - Fonction: Extérieur; Epaisseur par défaut: 0.08 m
Données d'identification(Type) - Sous-projet: Types de sols; Nom du type: A-isolant 8 cm
Graphismes(Type) - Couleur vue détail faible: 0; Motif vue détail faible: Bois - Type 1
Matériaux et finitions(Type) - Matériau structurel: AA-isolant plancher
Propriétés analytiques(Type) - Rugosité: 3; Coefficient d'absorbance: 0.7
Name (Sol:A-isolant 8 cm:...)
1030147
1030147:2

# IfcSlab: Sol:A-laine de bois 5cm (22)
PredefinedType: FLOOR; Material: AA-laine bois 0.05 m
Pset_SlabCommon - IsExternal: yes; LoadBearing: no; Reference: Sol:A-laine de bois 5cm
Autre - Catégorie: Sols; Famille: Sol: A-laine de bois 5cm; Famille et type: Sol: A-laine de bois 5cm; ID du type: Sol: A-laine de bois 5cm; Type: Sol: A-laine de bois 5cm
Contraintes - Lié au volume: no; Limite de pièce: yes
Cotes - Epaisseur: 0.05 m
Données d'identification - Sous-projet: Sous-projet 1
Phase de construction - Phase de création: Nouvelle construction
Structure - Activer le modèle analytique: no; Structure: no
Autre(Type) - Catégorie: Sols; Nom de la famille: Sol
Construction(Type) - Fonction: Extérieur; Epaisseur par défaut: 0.05 m
Données d'identification(Type) - Sous-projet: Types de sols; Nom du type: A-laine de bois 5cm
Graphismes(Type) - Couleur vue détail faible: 0; Motif vue détail faible: Bois - Type 1
Matériaux et finitions(Type) - Matériau structurel: AA-laine bois
Propriétés analytiques(Type) - Rugosité: 3; Coefficient d'absorbance: 0.7
Name (Sol:A-laine de bois 5cm:...) | In | Niveau | Décalage par rapport au niveau (m) | Elévation à la base (m) | Elévation en haut (m) | Périmètre (m) | Surface (m2) | Volume (m3)
1192946 | RDC | Niveau: RDC | 3.42 | 3.37 | 3.42 | 103.847 | 112.75 | 5.63752
1192946:2 | RDC | Niveau: RDC | 3.42 | 3.37 | 3.42 | 103.847 | 112.75 | 5.63752
1192946:3 | RDC | Niveau: RDC | 3.42 | 3.37 | 3.42 | 103.847 | 112.75 | 5.63752
1192946:4 | RDC | Niveau: RDC | 3.42 | 3.37 | 3.42 | 103.847 | 112.75 | 5.63752
1261704 | R+1 | Niveau: R+1 | 2.55 | 6.77 | 6.82 | 69.004 | 41.7702 | 2.08851
1261704:2 | R+1 | Niveau: R+1 | 2.55 | 6.77 | 6.82 | 69.004 | 41.7702 | 2.08851
1261704:3 | R+1 | Niveau: R+1 | 2.55 | 6.77 | 6.82 | 69.004 | 41.7702 | 2.08851
1261704:4 | R+1 | Niveau: R+1 | 2.55 | 6.77 | 6.82 | 69.004 | 41.7702 | 2.08851
1261704:5 | R+1 | Niveau: R+1 | 2.55 | 6.77 | 6.82 | 69.004 | 41.7702 | 2.08851
1261704:6 | R+1 | Niveau: R+1 | 2.55 | 6.77 | 6.82 | 69.004 | 41.7702 | 2.08851
1261704:7 | R+1 | Niveau: R+1 | 2.55 | 6.77 | 6.82 | 69.004 | 41.7702 | 2.08851
2598912 | R+2 | Niveau: R+2 | 2.55 | 10.33 | 10.38 | 59.1457 | 56.0589 | 2.80294 | Données d'identification - Variantes: Modèle de base
2598912:2 | R+2 | Niveau: R+2 | 2.55 | 10.33 | 10.38 | 59.1457 | 56.0589 | 2.80294 | Données d'identification - Variantes: Modèle de base
2598912:3 | R+2 | Niveau: R+2 | 2.55 | 10.33 | 10.38 | 59.1457 | 56.0589 | 2.80294 | Données d'identification - Variantes: Modèle de base
2598912:4 | R+2 | Niveau: R+2 | 2.55 | 10.33 | 10.38 | 59.1457 | 56.0589 | 2.80294 | Données d'identification - Variantes: Modèle de base
2598965 | R+1 | Niveau: R+1 | 2.71 | 6.93 | 6.98 | 80.264 | 65.5657 | 3.27829
2598965:2 | R+1 | Niveau: R+1 | 2.71 | 6.93 | 6.98 | 80.264 | 65.5657 | 3.27829
2598965:3 | R+1 | Niveau: R+1 | 2.71 | 6.93 | 6.98 | 80.264 | 65.5657 | 3.27829
2598965:4 | R+1 | Niveau: R+1 | 2.71 | 6.93 | 6.98 | 80.264 | 65.5657 | 3.27829
2598965:5 | R+1 | Niveau: R+1 | 2.71 | 6.93 | 6.98 | 80.264 | 65.5657 | 3.27829
2598965:6 | R+1 | Niveau: R+1 | 2.71 | 6.93 | 6.98 | 80.264 | 65.5657 | 3.27829
2928998 | R+2 | Niveau: R+2 | 2.45 | 10.23 | 10.28 | 9.71811 | 5.6471 | 0.282355 | Pset_SlabCommon - PitchAngle: 0 deg

# IfcSlab: Sol:A-sol souple (5)
PredefinedType: FLOOR; Material: AA-sol souple 0.01 m
Pset_SlabCommon - Reference: Sol:A-sol souple; IsExternal: no; LoadBearing: no; PitchAngle: 0 deg
Autre - Catégorie: Sols; Famille: Sol: A-sol souple; Famille et type: Sol: A-sol souple; ID du type: Sol: A-sol souple; Type: Sol: A-sol souple
Contraintes - Lié au volume: no; Limite de pièce: yes; Décalage par rapport au niveau: 0 m
Cotes - Epaisseur: 0.01 m
Données d'identification - Sous-projet: Sous-projet 1
Phase de construction - Phase de création: Nouvelle construction
Structure - Activer le modèle analytique: no; Structure: no
Autre(Type) - Catégorie: Sols; Nom de la famille: Sol
Construction(Type) - Epaisseur par défaut: 0.01 m; Fonction: Intérieur
Données d'identification(Type) - Sous-projet: Types de sols; Nom du type: A-sol souple
Graphismes(Type) - Couleur vue détail faible: 0
Matériaux et finitions(Type) - Matériau structurel: AA-sol souple
Propriétés analytiques(Type) - Rugosité: 3; Coefficient d'absorbance: 0.7
Name (Sol:A-sol souple:...) | In | Niveau | Elévation à la base (m) | Elévation en haut (m) | Périmètre (m) | Surface (m2) | Volume (m3)
328523 | R+1 | Niveau: R+1 | 4.26 | 4.27 | 51.4383 | 125.962 | 1.25962 | Données d'identification - Variantes: Modèle de base
328583 | R+1 | Niveau: R+1 | 4.26 | 4.27 | 69.9497 | 177.139 | 1.77139
328632 | R+2 | Niveau: R+2 | 7.82 | 7.83 | 65.5844 | 137.884 | 1.37884
349316 | RDC | Niveau: RDC | -0.01 | 0 | 69.1913 | 172.804 | 1.72804
351982 | RDC | Niveau: RDC | -0.01 | 0 | 51.0723 | 124.992 | 1.24992

# IfcSlab: coffre toile rétractable1:coffre toile rétractable:1708850, coffre toile rétractable1:coffre toile rétractable:1708852:1
In: Toiture
PredefinedType: ROOF; Material: AA-Aluminium
Pset_SlabCommon - IsExternal: yes; PitchAngle: 0 deg; Reference: coffre toile rétractable1:coffre toile rétractable

# IfcSlab: coffre toile rétractable2:coffre toile rétractable:1708874, coffre toile rétractable2:coffre toile rétractable:1708876:1
In: Toiture
PredefinedType: ROOF; Material: AA-Aluminium
Pset_SlabCommon - IsExternal: yes; PitchAngle: 0 deg; Reference: coffre toile rétractable2:coffre toile rétractable

# IfcSlab: coffre toile rétractable:coffre toile rétractable:1708845, coffre toile rétractable:coffre toile rétractable:1708847:1
In: Toiture
PredefinedType: ROOF; Material: AA-Aluminium
Pset_SlabCommon - IsExternal: yes; PitchAngle: 0 deg; Reference: coffre toile rétractable:coffre toile rétractable

# IfcSlab: couvertine25:couvertine:2178160, couvertine25:couvertine:2178162:1
In: Toiture
PredefinedType: ROOF; Material: AA-Aluminium
Pset_SlabCommon - IsExternal: yes; PitchAngle: 0 deg; Reference: couvertine25:couvertine

# IfcWallStandardCase: Mur de base:A-carrelage (71)
Type - PredefinedType: STANDARD; Material: AA-sol carrelage 0.01 m
Type - Autre - Catégorie: Murs; Nom de la famille: Mur de base
Type - Construction - Fonction: Intérieur; Retournement aux extrémités: Aucun(e); Retournement aux insertions: Ne pas retourner; Largeur: 0.01 m
Type - Données d'identification - Sous-projet: Types de murs; Commentaires du type: Int. Plâtre 100 mm; Nom du type: A-carrelage
Type - Graphismes - Couleur vue détail faible: 0
Type - Propriétés analytiques - Rugosité: 3; Coefficient d'absorbance: 0.7
Autre - Famille: Mur de base: A-carrelage; Famille et type: Mur de base: A-carrelage; ID du type: Mur de base: A-carrelage; Type: Mur de base: A-carrelage
Contraintes - Lié au volume: no; Extension inférieure: 0 m; Extension supérieure: 0 m; Partie inférieure attachée: no; Partie supérieure attachée: no; Ligne de justification: Nu fini: Extérieur; Décalage supérieur: 1.5 m
Données d'identification - Sous-projet: Cloisons
Phase de construction - Phase de création: Nouvelle construction
Structure - Activer le modèle analytique: no; Structure: no; Utilisation structurelle: Non porteur
Pset_WallCommon - IsExternal: no; LoadBearing: no; ExtendToStructure: no; Reference: Mur de base:A-carrelage
Name (Mur de base:A-carrelage:...) | In | Contrainte inférieure = Contrainte supérieure | Décalage inférieur (m) | Limite de pièce | Hauteur non contrainte (m) | Longueur (m) | Surface (m2) | Volume (m3)
2594313 | R+1 | Niveau: R+1 | 0 | no | 1.5 | 1.659 | 2.436 | 0.02436 | Données d'identification - Variantes: Modèle de base
2594675 | R+1 | Niveau: R+1 | 0 | no | 1.5 | 1.0285 | 1.49025 | 0.0149025
2594845 | R+1 | Niveau: R+1 | 0 | no | 1.5 | 1.70858 | 2.49162 | 0.0249162
2594997 | R+1 | Niveau: R+1 | 0 | no | 1.5 | 1.9835 | 2.97525 | 0.0297525
2595066 | R+1 | Niveau: R+1 | 0 | no | 1.5 | 0.656081 | 0.976622 | 0.00976622 | Données d'identification - Variantes: Modèle de base
2595451 | R+1 | Niveau: R+1 | 0 | no | 1.5 | 0.1005 | 0.15825 | 0.0015825 | Données d'identification - Variantes: Modèle de base
2595604 | R+1 | Niveau: R+1 | 0 | no | 1.5 | 1.9835 | 2.97525 | 0.0297525 | Données d'identification - Variantes: Modèle de base
2595686 | R+1 | Niveau: R+1 | 0 | no | 1.5 | 0.8955 | 1.34325 | 0.0134325 | Données d'identification - Variantes: Modèle de base
2595808 | R+1 | Niveau: R+1 | 0 | no | 1.5 | 2.0235 | 2.97525 | 0.0297525
2595887 | R+1 | Niveau: R+1 | 0 | no | 1.5 | 1.989 | 2.931 | 0.02931
2596067 | R+1 | Niveau: R+1 | 0 | yes | 1.5 | 0.836581 | 1.25487 | 0.0125487
2596551 | R+2 | Niveau: R+2 | 0 | no | 1.5 | 1.659 | 2.436 | 0.02436 | Données d'identification - Variantes: Modèle de base
2596552 | R+2 | Niveau: R+2 | 0 | no | 1.5 | 1.0285 | 1.49025 | 0.0149025 | Données d'identification - Variantes: Modèle de base
2596553 | R+2 | Niveau: R+2 | 0 | no | 1.5 | 1.70858 | 2.49162 | 0.0249162
2596554 | R+2 | Niveau: R+2 | 0 | no | 1.5 | 1.9835 | 2.97525 | 0.0297525
2596555 | R+2 | Niveau: R+2 | 0 | no | 1.5 | 0.656081 | 0.976622 | 0.00976622 | Données d'identification - Variantes: Modèle de base
2596556 | R+2 | Niveau: R+2 | 0 | no | 1.5 | 0.1005 | 0.15825 | 0.0015825
2596557 | R+2 | Niveau: R+2 | 0 | no | 1.5 | 1.9835 | 2.97525 | 0.0297525 | Données d'identification - Variantes: Modèle de base
2596558 | R+2 | Niveau: R+2 | 0 | no | 1.5 | 0.8955 | 1.34325 | 0.0134325
2596559 | R+2 | Niveau: R+2 | 0 | no | 1.5 | 2.0235 | 2.97525 | 0.0297525 | Données d'identification - Variantes: Modèle de base
2596560 | R+2 | Niveau: R+2 | 0 | no | 1.5 | 1.989 | 2.931 | 0.02931
2596561 | R+2 | Niveau: R+2 | 0 | yes | 1.5 | 0.836581 | 1.25487 | 0.0125487
2602300 | RDC | Niveau: RDC | 0 | yes | 1.5 | 2.6875 | 4.03125 | 0.0403125
2602415 | RDC | Niveau: RDC | 0 | yes | 1.5 | 1.64958 | 2.34312 | 0.0234312 | Données d'identification - Variantes: Modèle de base
2602508 | RDC | Niveau: RDC | 0 | yes | 1.5 | 1.7945 | 2.64675 | 0.0264675 | Données d'identification - Variantes: Modèle de base
2602552 | RDC | Niveau: RDC | 0 | yes | 1.5 | 2.2275 | 3.34125 | 0.0334125
2602613 | RDC | Niveau: RDC | 0 | yes | 1.5 | 1.7545 | 2.63175 | 0.0263175
2602644 | RDC | Niveau: RDC | 0 | yes | 1.5 | 1.2325 | 1.84125 | 0.0184125
2602773 | RDC | Niveau: RDC | 0 | yes | 1.5 | 1.7945 | 2.64675 | 0.0264675
2602814 | RDC | Niveau: RDC | 0 | yes | 1.5 | 0.83 | 1.245 | 0.01245 | Données d'identification - Variantes: Modèle de base
2602853 | RDC | Niveau: RDC | 0 | yes | 1.5 | 1.7945 | 2.63175 | 0.0263175 | Données d'identification - Variantes: Modèle de base
2602912 | RDC | Niveau: RDC | 0 | yes | 1.5 | 1.7945 | 2.64675 | 0.0264675 | Données d'identification - Variantes: Modèle de base
2602913 | RDC | Niveau: RDC | 0 | yes | 1.5 | 0.83 | 1.2375 | 0.012375 | Données d'identification - Variantes: Modèle de base
2602986 | RDC | Niveau: RDC | 0 | yes | 1.5 | 1.3475 | 2.02125 | 0.0202125 | Données d'identification - Variantes: Modèle de base
2608393 | R-1 | Niveau: R-1 | 0 | yes | 1.5 | 2.04 | 3.015 | 0.03015 | Données d'identification - Variantes: Modèle de base
2608449 | R-1 | Niveau: R-1 | 0 | yes | 1.5 | 0.714582 | 1.01937 | 0.0101937
2608496 | R-1 | Niveau: R-1 | 0 | yes | 1.5 | 0.754582 | 1.13937 | 0.0113937 | Données d'identification - Variantes: Modèle de base
2608546 | R-1 | Niveau: R-1 | 0 | yes | 1.5 | 0.625 | 0.8775 | 0.008775
2608591 | R-1 | Niveau: R-1 | 0 | yes | 1.5 | 1.455 | 2.1375 | 0.021375
2608637 | R-1 | Niveau: R-1 | 0 | yes | 1.5 | 1.495 | 2.10955 | 0.0210955
2608680 | R-1 | Niveau: R-1 | 0 | yes | 1.5 | 1.575 | 2.31 | 0.0231
2608723 | R-1 | Niveau: R-1 | 0 | yes | 1.5 | 0.095 | 0.15 | 0.0015
2608801 | R-1 | Niveau: R-1 | 0 | yes | 1.5 | 2.65658 | 3.89176 | 0.0389176
2656806 | RDC | Niveau: RDC | 0 | yes | 1.5 | 2.25 | 3.29625 | 0.0329625
2777030 | R-1 | Niveau: R-1 | 0.43 | yes | 1.07 | 0.895 | 0.8453 | 0.008453
2777088 | R-1 | Niveau: R-1 | 0.43 | yes | 1.07 | 1.74658 | 1.86884 | 0.0186884 | Données d'identification - Variantes: Modèle de base
2777179 | R-1 | Niveau: R-1 | 0.43 | yes | 1.07 | 0.0719997 | 0.0823897 | 0.000823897
2777228 | R-1 | Niveau: R-1 | 0.43 | yes | 1.07 | 1.865 | 1.98485 | 0.0198485 | Données d'identification - Variantes: Modèle de base
2777369 | R-1 | Niveau: R-1 | 0.43 | yes | 1.07 | 1.185 | 1.2733 | 0.012733 | Données d'identification - Variantes: Modèle de base
2777514 | R-1 | Niveau: R-1 | 0.43 | yes | 1.07 | 0.0719997 | 0.0716897 | 0.000716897 | Données d'identification - Variantes: Modèle de base
2777611 | R-1 | Niveau: R-1 | 0 | yes | 1.5 | 1.64 | 2.3925 | 0.023925
2777676 | R-1 | Niveau: R-1 | 0 | yes | 1.5 | 0.11 | 0.1725 | 0.001725 | Données d'identification - Variantes: Modèle de base
2777722 | R-1 | Niveau: R-1 | 0 | yes | 1.5 | 1.585 | 2.3775 | 0.023775 | Données d'identification - Variantes: Modèle de base
2777797 | R-1 | Niveau: R-1 | 0 | yes | 1.5 | 0.905 | 1.3425 | 0.013425 | Données d'identification - Variantes: Modèle de base
2777885 | R-1 | Niveau: R-1 | 0 | yes | 1.5 | 1.64 | 2.3925 | 0.023925
2777886 | R-1 | Niveau: R-1 | 0 | yes | 1.5 | 0.11 | 0.1725 | 0.001725 | Données d'identification - Variantes: Modèle de base
2777887 | R-1 | Niveau: R-1 | 0 | yes | 1.5 | 1.585 | 2.3775 | 0.023775 | Données d'identification - Variantes: Modèle de base
2777888 | R-1 | Niveau: R-1 | 0 | yes | 1.5 | 0.905 | 1.3425 | 0.013425
2777953 | R-1 | Niveau: R-1 | 0 | yes | 1.5 | 1.64 | 2.3925 | 0.023925
2777954 | R-1 | Niveau: R-1 | 0 | yes | 1.5 | 0.81 | 1.2225 | 0.012225 | Données d'identification - Variantes: Modèle de base
2777955 | R-1 | Niveau: R-1 | 0 | yes | 1.5 | 1.585 | 2.3775 | 0.023775
2777956 | R-1 | Niveau: R-1 | 0 | yes | 1.5 | 1.81 | 2.7 | 0.027
2778154 | R-1 | Niveau: R-1 | 0 | yes | 1.5 | 0.0987181 | 0.155577 | 0.00155577 | Données d'identification - Variantes: Modèle de base
2778265 | R-1 | Niveau: R-1 | 0 | yes | 1.5 | 3.84 | 5.76 | 0.0576
2778324 | R-1 | Niveau: R-1 | 0 | yes | 1.5 | 1.33667 | 1.8475 | 0.018475
2778373 | R-1 | Niveau: R-1 | 0 | yes | 1.5 | 2.81119 | 4.07428 | 0.0407428 | Données d'identification - Variantes: Modèle de base
2778420 | R-1 | Niveau: R-1 | 0 | yes | 1.5 | 0.81 | 1.2075 | 0.012075
2778449 | R-1 | Niveau: R-1 | 0 | yes | 1.5 | 0.22 | 0.33 | 0.0033
2778486 | R-1 | Niveau: R-1 | 0 | yes | 1.5 | 0.215 | 0.3225 | 0.003225
2778549 | R-1 | Niveau: R-1 | 0 | yes | 1.5 | 2.86619 | 4.07428 | 0.0407428
2778602 | R-1 | Niveau: R-1 | 0 | yes | 1.5 | 0.237951 | 0.206926 | 0.00206926

# IfcWallStandardCase: Mur de base:A-cloison CP 11.6 cm (32)
Type - PredefinedType: STANDARD; Material: AA-mur cloison finition 0.018 m, AA-isolant plancher 0.08 m, AA-mur cloison finition 0.018 m
Type - Autre - Catégorie: Murs; Nom de la famille: Mur de base
Type - Construction - Fonction: Intérieur; Largeur: 0.116 m; Retournement aux extrémités: Aucun(e); Retournement aux insertions: Ne pas retourner
Type - Données d'identification - Commentaires du type: Int. Plâtre 100 mm; Nom du type: A-cloison CP 11.6 cm; Sous-projet: Types de murs
Type - Graphismes - Couleur vue détail faible: 0
Type - Propriétés analytiques - Rugosité: 3; Coefficient d'absorbance: 0.7; Coefficient de transfert de chaleur (U): 29.0556; Masse thermique: 54399.6; Résistance thermique (R): 0.0344168
Autre - Famille: Mur de base: A-cloison CP 11.6 cm; Famille et type: Mur de base: A-cloison CP 11.6 cm; ID du type: Mur de base: A-cloison CP 11.6 cm; Type: Mur de base: A-cloison CP 11.6 cm
Contraintes - Lié au volume: no; Extension inférieure: 0 m; Extension supérieure: 0 m; Partie inférieure attachée: no
Données d'identification - Sous-projet: Cloisons
Phase de construction - Phase de création: Nouvelle construction
Structure - Activer le modèle analytique: no; Structure: no; Utilisation structurelle: Non porteur
Pset_WallCommon - IsExternal: no; LoadBearing: no; Reference: Mur de base:A-cloison CP 11.6 cm; ThermalTransmittance: 29.0556 kg/K/s3
Name (Mur de base:A-cloison CP 11.6 cm:...) | In | Limite de pièce | Contrainte inférieure | Contrainte supérieure | Décalage inférieur (m) | Décalage supérieur (m) | Hauteur non contrainte (m) | Ligne de justification | Partie supérieure attachée = ExtendToStructure | Longueur (m) | Surface (m2) | Volume (m3) | Variantes
328865 | R+1 | yes | Niveau: R+1 | Niveau: R+2 | 0 | -0.52 | 3.04 | Axe du mur | no | 2.70958 | 8.06081 | 0.935054 | Modèle de base
329588 | R+1 | yes | Niveau: R+1 | Niveau: R+2 | 0 | -0.46 | 3.1 | Axe du mur | no | 3.43 | 10.2734 | 1.19171 | Modèle de base
329679 | R+1 | yes | Niveau: R+1 | Niveau: R+2 | 0 | -0.52 | 3.04 | Axe du mur | no | 8.30316 | 25.2416 | 2.92803 | Modèle de base
329720 | R+1 | yes | Niveau: R+1 | Niveau: R+2 | 0 | -0.52 | 3.04 | Axe du mur | no | 8.30316 | 23.1666 | 2.68733 | Modèle de base
329747 | R+1 | yes | Niveau: R+1 | Niveau: R+2 | 0 | -1.5 | 2.06 | Axe du mur | yes | 8.25316 | 23.787 | 2.75929
349323 | RDC | yes | Niveau: RDC | Niveau: R+1 | 0 | -0.55 | 3.72 | Axe du mur | yes | 8.25316 | 29.6467 | 3.43902 | Modèle de base
1038672 | RDC | yes | Niveau: RDC | Niveau: R+1 | -0.01 | -0.27 | 4.01 | Axe du mur | no | 0.779 | 2.79898 | 0.324682
1038673 | RDC | yes | Niveau: RDC | Niveau: R+1 | -0.01 | -0.26 | 4.02 | Axe du mur | no | 0.779 | 2.80596 | 0.325491
1039060 | R+1 | yes | Niveau: R+1 | Niveau: R+2 | 0 | -0.5 | 3.06 | Axe du mur | no | 0.779 | 1.78092 | 0.206587 | Modèle de base
1039064 | R+1 | yes | Niveau: R+1 | Niveau: R+2 | -0.26 | -0.47 | 3.35 | Axe du mur | no | 0.779 | 1.9497 | 0.226165
1040266 | RDC | yes | Niveau: RDC | Niveau: R+1 | -0.01 | -0.27 | 4.01 | Axe du mur | no | 0.79 | 2.49422 | 0.28933 | Modèle de base
1040860 | R+1 | yes | Niveau: R+1 | Niveau: R+2 | -0.27 | -0.5 | 3.33 | Axe du mur | no | 0.79 | 2.07126 | 0.240266 | Modèle de base
1282184 | RDC | yes | Niveau: RDC | Niveau: R+1 | 0 | -0.27 | 4 | Axe du mur | no | 0.79 | 2.952 | 0.342432 | Modèle de base
1284380 | R+1 | yes | Niveau: R+1 | Niveau: R+2 | 0 | -0.48 | 3.08 | Axe du mur | no | 0.79 | 1.91576 | 0.222228
1413364 | RDC | yes | Niveau: RDC | Niveau: R+1 | -0.01 | -0.26 | 4.02 | Axe du mur | no | 2.884 | 11.5937 | 1.34487 | Modèle de base
1413804 | R+1 | yes | Niveau: R+1 | Niveau: R+2 | -0.01 | -0.47 | 3.1 | Axe du mur | no | 2.907 | 9.3 | 1.0788 | Modèle de base
1413957 | R+1 | yes | Niveau: R+1 | Niveau: R+2 | -0.01 | -0.47 | 3.1 | Axe du mur | no | 2.884 | 9.3 | 1.0788
1414089 | RDC | yes | Niveau: RDC | Niveau: R+1 | -0.01 | -0.26 | 4.02 | Axe du mur | no | 2.884 | 11.1274 | 1.29077
2250788 | R+1 | yes | Niveau: R+1 | Niveau: R+2 | 0 | -0.31 | 3.25 | Axe du mur | no | 8.06316 | 22.0553 | 2.55841
2250789 | R+1 | yes | Niveau: R+1 | Niveau: R+2 | 0 | -0.31 | 3.25 | Axe du mur | no | 8.06316 | 24.1303 | 2.79911
2250790 | R+1 | yes | Niveau: R+1 | Niveau: R+2 | 0 | -0.31 | 3.25 | Axe du mur | no | 8.06316 | 24.1303 | 2.79911
2267714 | RDC | no | Niveau: RDC | Niveau: R+1 | 0 | -0.31 | 3.96 | Axe du mur | no | 8.25316 | 22.5725 | 2.61841
2520688 | R+2 | yes | Niveau: R+2 | Niveau: Toiture | 0 | -0.23 | 2.99 | Axe du mur | no | 8.06316 | 22.0339 | 2.55593 | Modèle de base
2520694 | R+2 | yes | Niveau: R+2 | Niveau: Toiture | 0 | -0.23 | 2.99 | Axe du mur | no | 8.25316 | 22.602 | 2.62183 | Modèle de base
2560756 | R+1 | yes | Niveau: R+1 | Niveau: R+2 | -0.09 | -0.45 | 3.2 | Axe du mur | no | 2.884 | 7.525 | 0.8729 | Modèle de base
2560757 | R+1 | yes | Niveau: R+1 | Niveau: R+2 | 0 | -0.46 | 3.1 | Axe du mur | no | 1.884 | 5.8404 | 0.677486
2560758 | R+1 | yes | Niveau: R+1 | Niveau: R+2 | 0 | -0.45 | 3.11 | Axe du mur | no | 2.884 | 8.96924 | 1.04043
2560759 | R+1 | yes | Niveau: R+1 | Niveau: R+2 | 0 | -0.3 | 3.26 | Axe du mur | no | 1.884 | 5.76368 | 0.668587 | Modèle de base
2563546 | R+1 | yes | Niveau: R+1 | Niveau: R+2 | 0 | -0.52 | 3.04 | Axe du mur | no | 2.70958 | 8.06081 | 0.935054 | Modèle de base
2676693 | RDC | yes | Niveau: RDC | Niveau: RDC | 0.02 | 3.35 | 3.33 | Nu fini: Extérieur | no | 1.58 | 5.2614 | 0.610322 | Modèle de base | Group: Groupe de modèles:PORTE MUR COULISSANT:2677156
2677407 | RDC | yes | Niveau: RDC | Niveau: RDC | 0.02 | 3.35 | 3.33 | Nu fini: Extérieur | no | 1.58 | 5.2614 | 0.610322 | Modèle de base | Group: Groupe de modèles:PORTE MUR COULISSANT:2677416
2757830 | R+1 | yes | Niveau: R+1 | Niveau: R+2 | 0 | -0.31 | 3.25 | Axe du mur | no | 4 | 10.548 | 1.22357 | Modèle de base

# IfcWallStandardCase: Mur de base:A-cloison FC 10.5 cm (24)
Type - PredefinedType: STANDARD; Material: AA-peinture blanc satiné 0.0125 m, AA-isolant plancher 0.08 m, AA-peinture blanc satiné 0.0125 m
Type - Autre - Catégorie: Murs; Nom de la famille: Mur de base
Type - Construction - Fonction: Intérieur; Retournement aux extrémités: Aucun(e); Retournement aux insertions: Ne pas retourner; Largeur: 0.105 m
Type - Données d'identification - Sous-projet: Types de murs; Commentaires du type: Int. Plâtre 100 mm; Nom du type: A-cloison FC 10.5 cm
Type - Graphismes - Couleur vue détail faible: 0
Type - Propriétés analytiques - Rugosité: 3; Coefficient d'absorbance: 0.7
Autre - Famille: Mur de base: A-cloison FC 10.5 cm; Famille et type: Mur de base: A-cloison FC 10.5 cm; ID du type: Mur de base: A-cloison FC 10.5 cm; Type: Mur de base: A-cloison FC 10.5 cm
Contraintes - Lié au volume: no; Limite de pièce: yes; Extension inférieure: 0 m; Extension supérieure: 0 m; Ligne de justification: Axe du mur; Partie inférieure attachée: no
Données d'identification - Sous-projet: Cloisons
Phase de construction - Phase de création: Nouvelle construction
Structure - Activer le modèle analytique: no; Structure: no; Utilisation structurelle: Non porteur
Pset_WallCommon - IsExternal: no; LoadBearing: no; Reference: Mur de base:A-cloison FC 10.5 cm
Name (Mur de base:A-cloison FC 10.5 cm:...) | In | Contrainte inférieure | Contrainte supérieure | Décalage inférieur (m) | Décalage supérieur (m) | Hauteur non contrainte (m) | Partie supérieure attachée = ExtendToStructure | Longueur (m) | Surface (m2) | Volume (m3)
329743 | R+1 | Niveau: R+1 | Niveau: R+2 | -0.09 | -0.4 | 3.25 | yes | 5.02158 | 15.1926 | 1.59522 | Données d'identification - Variantes: Modèle de base
349321 | RDC | Niveau: RDC | Niveau: R+1 | 0 | -0.31 | 3.96 | no | 5.39158 | 19.0678 | 2.00212 | Données d'identification - Variantes: Modèle de base
349353 | RDC | Niveau: RDC | Niveau: R+1 | 0 | -0.4 | 3.87 | no | 1.64 | 3.68163 | 0.386571 | Données d'identification - Variantes: Modèle de base
382112 | R+2 | Niveau: R+2 | Niveau: Toiture | -0.09 | -0.23 | 3.08 | no | 8.30316 | 21.4237 | 2.24949 | Données d'identification - Variantes: Modèle de base
885257 | R+1 | Niveau: R+1 | Niveau: R+2 | 0 | -0.23 | 3.33 | no | 1.64 | 2.87838 | 0.302229 | Données d'identification - Variantes: Modèle de base
885301 | R+2 | Niveau: R+2 | Niveau: Toiture | 0 | -0.4 | 2.82 | no | 1.64 | 2.11975 | 0.222574
887420 | R+1 | Niveau: R+1 | Niveau: R+2 | 0 | -0.23 | 3.33 | no | 0.66 | 2.1978 | 0.230769
887512 | R+1 | Niveau: R+1 | Niveau: R+2 | 0 | -0.23 | 3.33 | no | 0.922 | 3.07026 | 0.322377
887571 | R+1 | Niveau: R+1 | Niveau: R+2 | -0.01 | -0.01 | 3.56 | no | 0.66 | 1.97685 | 0.207569
888889 | RDC | Niveau: RDC | Niveau: R+1 | 0 | -0.23 | 4.04 | no | 0.66 | 2.2422 | 0.235431
888890 | RDC | Niveau: RDC | Niveau: R+1 | 0 | -0.23 | 4.04 | no | 3.052 | 12.3301 | 1.29466 | Données d'identification - Variantes: Modèle de base
888907 | R+2 | Niveau: R+2 | Niveau: Toiture | -0.01 | -0.18 | 3.05 | no | 0.66 | 1.69275 | 0.177739 | Données d'identification - Variantes: Modèle de base
1005957 | R+1 | Niveau: R+1 | Niveau: R+2 | -0.09 | -0.26 | 3.39 | no | 2.462 | 8.35458 | 0.877231
1006063 | R+1 | Niveau: R+1 | Niveau: R+2 | 0 | -0.23 | 3.33 | no | 0.66 | 2.1978 | 0.230769
1006081 | R+1 | Niveau: R+1 | Niveau: R+2 | 0 | -0.4 | 3.16 | yes | 2.45958 | 6.07297 | 0.637662 | Données d'identification - Variantes: Modèle de base
1240756 | R+2 | Niveau: R+2 | Niveau: Toiture | 0 | -0.17 | 3.05 | no | 0.66 | 1.69275 | 0.177739
1272143 | R+1 | Niveau: R+1 | Niveau: R+2 | 0 | -0.23 | 3.33 | no | 0.66 | 2.1978 | 0.230769
1272536 | R+2 | Niveau: R+2 | Niveau: Toiture | 0 | -0.17 | 3.05 | no | 0.66 | 1.69275 | 0.177739 | Données d'identification - Variantes: Modèle de base
1272956 | RDC | Niveau: RDC | Niveau: R+1 | -0.275 | -0.01 | 4.535 | no | 0.66 | 2.51693 | 0.264277
1314524 | R+2 | Niveau: R+2 | Niveau: Toiture | 0 | -0.2 | 3.02 | no | 0.66 | 1.6761 | 0.17599
1412725 | R+2 | Niveau: R+2 | Niveau: Toiture | -0.09 | -0.18 | 3.13 | no | 3.384 | 10.9206 | 1.14666
1642588 | R+1 | Niveau: R+1 | Niveau: R+2 | 0 | -0.23 | 3.33 | no | 4.07 | 13.3783 | 1.40472
1643187 | R+2 | Niveau: R+2 | Niveau: Toiture | 0 | -0.2 | 3.02 | no | 4.07 | 12.1329 | 1.27395 | Données d'identification - Variantes: Modèle de base
2240591 | RDC | Niveau: RDC | Niveau: R+1 | 0 | -0.23 | 4.04 | no | 8.22 | 30.4551 | 3.19778

# IfcWallStandardCase: Mur de base:A-mur BTC + iso + BA13 (4)
Type - PredefinedType: STANDARD; Material: AA-BTC 0.22 m, AA-air 0.025 m, AA-isolant plancher 0.02 m, AA-fermacell peint 0.013 m
Type - Autre - Catégorie: Murs; Nom de la famille: Mur de base
Type - Construction - Fonction: Extérieur; Retournement aux extrémités: Intérieur; Retournement aux insertions: Les deux; Largeur: 0.278 m
Type - Données d'identification - Sous-projet: Types de murs; Commentaires du type: Extérieur voile BA 20; Nom du type: A-mur BTC + iso + BA13
Type - Graphismes - Couleur vue détail faible: 0
Type - Matériaux et finitions - Matériau structurel: AA-BTC
Type - Propriétés analytiques - Rugosité: 3; Coefficient d'absorbance: 0.7; Coefficient de transfert de chaleur (U): 4.26939; Masse thermique: 370220; Résistance thermique (R): 0.234226
Autre - Famille: Mur de base: A-mur BTC + iso + BA13; Famille et type: Mur de base: A-mur BTC + iso + BA13; ID du type: Mur de base: A-mur BTC + iso + BA13; Type: Mur de base: A-mur BTC + iso + BA13
Contraintes - Lié au volume: no; Limite de pièce: yes; Extension inférieure: 0 m; Extension supérieure: 0 m; Ligne de justification: Axe du mur; Partie inférieure attachée: no; Partie supérieure attachée: no
Données d'identification - Sous-projet: BTC
Phase de construction - Phase de création: Nouvelle construction
Structure - Activer le modèle analytique: no; Structure: no; Utilisation structurelle: Non porteur
Pset_WallCommon - IsExternal: yes; LoadBearing: no; ExtendToStructure: no; Reference: Mur de base:A-mur BTC + iso + BA13; ThermalTransmittance: 4.26939 kg/K/s3
Name (Mur de base:A-mur BTC + iso + BA13:...) | In | Contrainte inférieure | Contrainte supérieure | Décalage inférieur (m) | Décalage supérieur (m) | Hauteur non contrainte (m) | Longueur (m) | Surface (m2) | Volume (m3) | Variantes
675114 | RDC | Niveau: RDC | Niveau: R+1 | 0.3 | -0.55 | 3.42 | 1.63 | 5.5746 | 1.54974 | Modèle de base
1400864 | RDC | Niveau: RDC | Niveau: R+1 | 0.3 | -0.51 | 3.46 | 5.95316 | 20.5979 | 5.72623
1606275 | R+1 | Niveau: R+1 | Niveau: R+2 | -0.09 | -0.46 | 3.19 | 4.39158 | 14.0091 | 3.89454 | Modèle de base
1606277 | R+1 | Niveau: R+1 | Niveau: R+2 | -0.13 | -0.46 | 3.23 | 3.19158 | 10.3088 | 2.86585 | Modèle de base

# IfcWallStandardCase: Mur de base:A-mur BTC 14 cm (6)
Type - PredefinedType: STANDARD; Material: AA-BTC 0.14 m
Type - Autre - Catégorie: Murs; Nom de la famille: Mur de base
Type - Construction - Fonction: Extérieur; Retournement aux extrémités: Intérieur; Retournement aux insertions: Les deux; Largeur: 0.14 m
Type - Données d'identification - Sous-projet: Types de murs; Commentaires du type: Extérieur voile BA 20; Nom du type: A-mur BTC 14 cm
Type - Graphismes - Couleur vue détail faible: 0
Type - Matériaux et finitions - Matériau structurel: AA-BTC
Type - Propriétés analytiques - Rugosité: 3; Coefficient d'absorbance: 0.7; Coefficient de transfert de chaleur (U): 7.47143; Masse thermique: 211554; Résistance thermique (R): 0.133843
Autre - Famille: Mur de base: A-mur BTC 14 cm; Famille et type: Mur de base: A-mur BTC 14 cm; ID du type: Mur de base: A-mur BTC 14 cm; Type: Mur de base: A-mur BTC 14 cm
Contraintes - Lié au volume: no; Limite de pièce: yes; Extension inférieure: 0 m; Extension supérieure: 0 m; Partie inférieure attachée: no; Partie supérieure attachée: no
Données d'identification - Sous-projet: BTC
Phase de construction - Phase de création: Nouvelle construction
Structure - Activer le modèle analytique: no; Structure: no; Utilisation structurelle: Non porteur
Pset_WallCommon - IsExternal: yes; LoadBearing: no; ExtendToStructure: no; Reference: Mur de base:A-mur BTC 14 cm; ThermalTransmittance: 7.47143 kg/K/s3
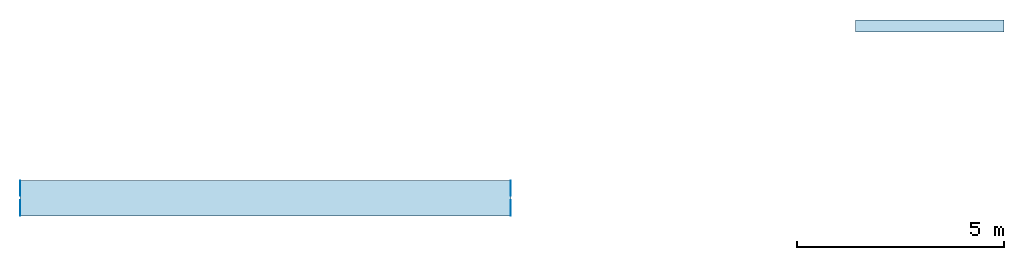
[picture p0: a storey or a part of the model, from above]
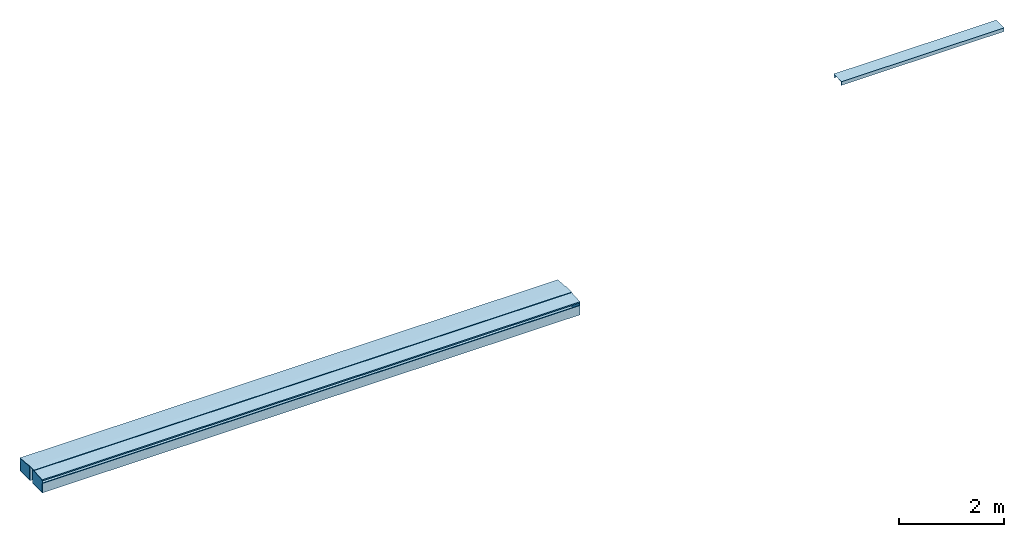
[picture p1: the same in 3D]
Properties of the parts of a building model (IFC2X3), part 5 of 5

# IfcWallStandardCase: Mur de base:A-mur BTC 14 cm (6)
Name (Mur de base:A-mur BTC 14 cm:...) | In | Décalage inférieur (m) | Ligne de justification | Contrainte inférieure | Contrainte supérieure | Décalage supérieur (m) | Hauteur non contrainte (m) | Longueur (m) | Surface (m2) | Volume (m3) | Variantes
1233076 | RDC | 0 | Axe du mur | Niveau: RDC | Niveau: R+1 | -0.27 | 4 | 0.44 | 1.4 | 0.196 | Modèle de base
1233513 | R+1 | -0.04 | Axe du mur | Niveau: R+1 | Niveau: R+2 | -0.4 | 3.2 | 0.44 | 1.12 | 0.1568 | Modèle de base
1233580 | R+2 | -0.01 | Axe du mur | Niveau: R+2 | Niveau: Toiture | -0.18 | 3.05 | 0.44 | 1.0675 | 0.14945 | Modèle de base
1296426 | RDC | 0.2 | Axe du mur | Niveau: RDC | Niveau: R+1 | -0.46 | 3.61 | 2.2627 | 8.16834 | 1.14357 | Modèle de base
1296521 | R+1 | 0.1 | Nu fini: Extérieur | Niveau: R+1 | Niveau: R+2 | -0.5 | 2.96 | 2.25457 | 6.67353 | 0.934294
1296791 | R+2 | 0.1 | Nu fini: Extérieur | Niveau: R+2 | Niveau: Toiture | -0.32 | 2.8 | 2.25238 | 6.30667 | 0.882934 | Modèle de base

# IfcWallStandardCase: Mur de base:A-mur parpaing 10 (10)
In: R-1
Type - PredefinedType: STANDARD; Material: AA-parpaing 0.1 m
Type - Autre - Catégorie: Murs; Nom de la famille: Mur de base
Type - Construction - Fonction: Intérieur; Retournement aux extrémités: Aucun(e); Retournement aux insertions: Ne pas retourner; Largeur: 0.1 m
Type - Données d'identification - Sous-projet: Types de murs; Nom du type: A-mur parpaing 10
Type - Graphismes - Couleur vue détail faible: 0
Type - Propriétés analytiques - Rugosité: 3; Coefficient d'absorbance: 0.7; Coefficient de transfert de chaleur (U): 10.46; Masse thermique: 151110; Résistance thermique (R): 0.0956023
Autre - Famille: Mur de base: A-mur parpaing 10; Famille et type: Mur de base: A-mur parpaing 10; ID du type: Mur de base: A-mur parpaing 10; Type: Mur de base: A-mur parpaing 10
Contraintes - Lié au volume: no; Décalage inférieur: 0 m; Extension inférieure: 0 m; Extension supérieure: 0 m; Ligne de justification: Axe du mur; Partie inférieure attachée: no; Partie supérieure attachée: no; Contrainte inférieure: Niveau: R-1; Contrainte supérieure: Niveau: RDC
Données d'identification - Sous-projet: Cloisons
Phase de construction - Phase de création: Nouvelle construction
Structure - Activer le modèle analytique: no; Structure: no; Utilisation structurelle: Non porteur
Pset_WallCommon - IsExternal: no; LoadBearing: no; ExtendToStructure: no; Reference: Mur de base:A-mur parpaing 10; ThermalTransmittance: 10.46 kg/K/s3
Name (Mur de base:A-mur parpaing 10:...) | Limite de pièce | Décalage supérieur (m) | Hauteur non contrainte (m) | Longueur (m) | Surface (m2) | Volume (m3) | Variantes
1040186 | yes | -0.255 | 4.365 | 0.817 | 2.91145 | 0.291145 | Modèle de base
1249925 | yes | -0.255 | 4.365 | 7.453 | 31.8776 | 3.18776 | Modèle de base
1387716 | yes | -0.255 | 4.365 | 1.44167 | 3.34488 | 0.334488
1389426 | yes | -0.275 | 4.345 | 4.56119 | 19.1666 | 1.91666
1413132 | yes | -0.275 | 4.345 | 2.019 | 9.20705 | 0.920705 | Modèle de base
1686133 | yes | -0.275 | 4.345 | 4.56119 | 19.1666 | 1.91666 | Modèle de base
1686434 | yes | -0.255 | 4.365 | 2.155 | 6.88432 | 0.688432 | Modèle de base
1689541 | no | -0.275 | 4.345 | 1.695 | 6.93027 | 0.693027 | Modèle de base
1689551 | no | -0.255 | 4.365 | 4 | 11.4102 | 1.14102
1689554 | no | -0.275 | 4.345 | 1.695 | 6.93027 | 0.693027 | Modèle de base

# IfcWallStandardCase: Mur de base:A-mur parpaing 20 (10)
In: R-1
Type - PredefinedType: STANDARD; Material: AA-mur parpaing 20 0.2 m
Type - Autre - Catégorie: Murs; Nom de la famille: Mur de base
Type - Construction - Fonction: Extérieur; Retournement aux extrémités: Aucun(e); Retournement aux insertions: Ne pas retourner; Largeur: 0.2 m
Type - Données d'identification - Sous-projet: Types de murs; Commentaires du type: Extérieur voile BA 20; Nom du type: A-mur parpaing 20
Type - Graphismes - Couleur vue détail faible: 0
Type - Matériaux et finitions - Matériau structurel: AA-mur parpaing 20
Type - Propriétés analytiques - Rugosité: 3; Coefficient d'absorbance: 0.7; Coefficient de transfert de chaleur (U): 5.23; Masse thermique: 302220; Résistance thermique (R): 0.191205
Autre - Famille: Mur de base: A-mur parpaing 20; Famille et type: Mur de base: A-mur parpaing 20; ID du type: Mur de base: A-mur parpaing 20; Type: Mur de base: A-mur parpaing 20
Contraintes - Lié au volume: no; Limite de pièce: yes; Décalage inférieur: 0 m; Extension inférieure: 0 m; Extension supérieure: 0 m; Ligne de justification: Axe du mur; Partie inférieure attachée: no; Partie supérieure attachée: no; Contrainte inférieure: Niveau: R-1; Décalage supérieur: 0 m; Hauteur non contrainte: 0.43 m
Données d'identification - Sous-projet: Cloisons
Phase de construction - Phase de création: Nouvelle construction
Structure - Activer le modèle analytique: no; Structure: no; Utilisation structurelle: Non porteur
Pset_WallCommon - IsExternal: yes; LoadBearing: no; ExtendToStructure: no; Reference: Mur de base:A-mur parpaing 20; ThermalTransmittance: 5.23 kg/K/s3
Name (Mur de base:A-mur parpaing 20:...) | Longueur (m) | Surface (m2) | Volume (m3)
897771 | 0.702 | 0.38786 | 0.077572 | Données d'identification - Variantes: Modèle de base
897772 | 2.214 | 0.86602 | 0.173204 | Données d'identification - Variantes: Modèle de base
1273259 | 0.702 | 0.30186 | 0.060372 | Données d'identification - Variantes: Modèle de base
2444873 | 3.18158 | 0.89508 | 0.179016
2445491 | 4.27 | 1.7501 | 0.35002
2445994 | 2.214 | 0.86602 | 0.173204
2446021 | 2.74958 | 1.18232 | 0.236464
2446274 | 3.298 | 1.33214 | 0.266428 | Données d'identification - Variantes: Modèle de base
2446476 | 8 | 3.354 | 0.6708
2446683 | 8.27416 | 2.94342 | 0.588684 | Données d'identification - Variantes: Modèle de base

# IfcWallStandardCase: Mur de base:A-plaque FC (10)
Type - PredefinedType: STANDARD; Material: AA-fermacell peint 0.0125 m
Type - Autre - Catégorie: Murs; Nom de la famille: Mur de base
Type - Construction - Fonction: Intérieur; Retournement aux extrémités: Aucun(e); Retournement aux insertions: Ne pas retourner; Largeur: 0.0125 m
Type - Données d'identification - Sous-projet: Types de murs; Commentaires du type: Int. Plâtre 100 mm; Nom du type: A-plaque FC
Type - Graphismes - Couleur vue détail faible: 0
Type - Propriétés analytiques - Rugosité: 3; Coefficient d'absorbance: 0.7
Autre - Famille: Mur de base: A-plaque FC; Famille et type: Mur de base: A-plaque FC; ID du type: Mur de base: A-plaque FC; Type: Mur de base: A-plaque FC
Contraintes - Lié au volume: no; Limite de pièce: yes; Extension inférieure: 0 m; Extension supérieure: 0 m; Partie inférieure attachée: no; Partie supérieure attachée: no
Données d'identification - Sous-projet: Cloisons
Phase de construction - Phase de création: Nouvelle construction
Structure - Activer le modèle analytique: no; Structure: no; Utilisation structurelle: Non porteur
Pset_WallCommon - IsExternal: no; LoadBearing: no; ExtendToStructure: no; Reference: Mur de base:A-plaque FC
Name (Mur de base:A-plaque FC:...) | In | Contrainte inférieure | Contrainte supérieure | Décalage inférieur (m) | Ligne de justification | Décalage supérieur (m) | Hauteur non contrainte (m) | Longueur (m) | Surface (m2) | Volume (m3)
2594001 | R+1 | Niveau: R+1 | Niveau: R+2 | 0 | Nu fini: Extérieur | -0.26 | 3.3 | 2.2 | 7.26 | 0.09075 | Données d'identification - Variantes: Modèle de base
2596335 | R+2 | Niveau: R+2 | Niveau: Toiture | 0 | Nu fini: Extérieur | -0.18 | 3.04 | 2.2 | 6.688 | 0.0836 | Données d'identification - Variantes: Modèle de base
2602177 | RDC | Niveau: RDC | Niveau: R+1 | 0 | Axe du mur | -0.4 | 3.87 | 2.2 | 8.514 | 0.106425
2609226 | R-1 | Niveau: R-1 | Niveau: R-1 | 0 | Nu fini: Extérieur | 3.41 | 3.41 | 2.73625 | 9.01093 | 0.112637
2609253 | R-1 | Niveau: R-1 | Niveau: R-1 | 0 | Nu fini: Extérieur | 3.41 | 3.41 | 0.6475 | 2.20798 | 0.0275997 | Données d'identification - Variantes: Modèle de base
2609267 | R-1 | Niveau: R-1 | Niveau: R-1 | 0 | Nu fini: Extérieur | 3.41 | 3.41 | 0.10625 | 0.341 | 0.0042625 | Données d'identification - Variantes: Modèle de base
2609310 | R-1 | Niveau: R-1 | Niveau: R-1 | 0 | Nu fini: Extérieur | 3.41 | 3.41 | 0.10625 | 0.042625 | 0.000532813
2609337 | R-1 | Niveau: R-1 | Niveau: R-1 | 0 | Nu fini: Extérieur | 3.41 | 3.41 | 0.23125 | 0.76725 | 0.00959062
2666366 | R-1 | Niveau: R-1 | Niveau: R-1 | 3.4225 | Nu fini: Extérieur | 4.345 | 0.9225 | 3.36 | 3.00735 | 0.0375919
2776571 | R-1 | Niveau: R-1 | Niveau: R-1 | 0 | Nu fini: Extérieur | 3.41 | 3.41 | 0.10625 | 0.341 | 0.0042625

# IfcWallStandardCase: Mur de base:A-prémur BTC (109)
Type - PredefinedType: STANDARD; Material: AA-BTC 0.22 m
Type - Autre - Catégorie: Murs; Nom de la famille: Mur de base
Type - Construction - Fonction: Extérieur; Largeur: 0.22 m; Retournement aux extrémités: Intérieur; Retournement aux insertions: Les deux
Type - Données d'identification - Sous-projet: Types de murs; Commentaires du type: Extérieur voile BA 20; Nom du type: A-prémur BTC
Type - Graphismes - Couleur vue détail faible: 0
Type - Matériaux et finitions - Matériau structurel: AA-BTC
Type - Propriétés analytiques - Rugosité: 3; Coefficient d'absorbance: 0.7; Coefficient de transfert de chaleur (U): 4.75455; Masse thermique: 332442; Résistance thermique (R): 0.210325
Autre - Famille: Mur de base: A-prémur BTC; Famille et type: Mur de base: A-prémur BTC; ID du type: Mur de base: A-prémur BTC; Type: Mur de base: A-prémur BTC
Contraintes - Lié au volume: no; Limite de pièce: yes; Extension inférieure: 0 m; Extension supérieure: 0 m; Ligne de justification: Axe du mur; Partie inférieure attachée: no; Partie supérieure attachée: no
Données d'identification - Sous-projet: BTC
Phase de construction - Phase de création: Nouvelle construction
Structure - Activer le modèle analytique: no; Structure: no; Utilisation structurelle: Non porteur
Pset_WallCommon - IsExternal: yes; LoadBearing: no; ExtendToStructure: no; Reference: Mur de base:A-prémur BTC; ThermalTransmittance: 4.75455 kg/K/s3
Name (Mur de base:A-prémur BTC:...) | In | Contrainte inférieure | Contrainte supérieure | Décalage inférieur (m) | Décalage supérieur (m) | Hauteur non contrainte (m) | Longueur (m) | Surface (m2) | Volume (m3)
553342 | RDC | Niveau: RDC | Niveau: R+1 | 0.3 | -0.46 | 3.51 | 0.7 | 2.457 | 0.54054 | Données d'identification - Variantes: Modèle de base
553435 | RDC | Niveau: RDC | Niveau: R+1 | 0.3 | -0.46 | 3.51 | 0.7 | 2.457 | 0.54054 | Données d'identification - Variantes: Modèle de base
553453 | RDC | Niveau: RDC | Niveau: R+1 | 0.3 | -0.46 | 3.51 | 0.7 | 2.457 | 0.54054
553467 | RDC | Niveau: RDC | Niveau: R+1 | 0.3 | -0.46 | 3.51 | 0.7 | 2.457 | 0.54054 | Données d'identification - Variantes: Modèle de base
646224 | RDC | Niveau: RDC | Niveau: R+1 | 0.3 | -0.51 | 3.46 | 2.66158 | 5.75336 | 1.26574 | Données d'identification - Variantes: Modèle de base
647095 | RDC | Niveau: RDC | Niveau: R+1 | 0.3 | -0.46 | 3.51 | 0.7 | 2.457 | 0.54054 | Données d'identification - Variantes: Modèle de base
647113 | RDC | Niveau: RDC | Niveau: R+1 | 0.3 | -0.46 | 3.51 | 0.7 | 2.457 | 0.54054 | Données d'identification - Variantes: Modèle de base
674039 | RDC | Niveau: RDC | Niveau: R+1 | 0.3 | -0.46 | 3.51 | 0.7 | 2.457 | 0.54054 | Données d'identification - Variantes: Modèle de base
674042 | RDC | Niveau: RDC | Niveau: R+1 | 0.3 | -0.46 | 3.51 | 0.7 | 2.457 | 0.54054
674045 | RDC | Niveau: RDC | Niveau: R+1 | 0.3 | -0.46 | 3.51 | 0.7 | 2.457 | 0.54054 | Données d'identification - Variantes: Modèle de base
674048 | RDC | Niveau: RDC | Niveau: R+1 | 0.3 | -0.46 | 3.51 | 0.7 | 2.457 | 0.54054
674051 | RDC | Niveau: RDC | Niveau: R+1 | 0.3 | -0.46 | 3.51 | 0.7 | 2.457 | 0.54054 | Données d'identification - Variantes: Modèle de base
674636 | R+1 | Niveau: R+1 | Niveau: R+2 | -3.97 | -0.46 | 7.07 | 1.63 | 11.5241 | 2.5353 | Données d'identification - Variantes: Modèle de base
675032 | RDC | Niveau: RDC | Niveau: R+1 | 0.3 | -0.46 | 3.51 | 0.7 | 2.457 | 0.54054
675047 | RDC | Niveau: RDC | Niveau: R+1 | 0.3 | -0.46 | 3.51 | 0.7 | 2.457 | 0.54054
675058 | RDC | Niveau: RDC | Niveau: R+1 | 0.3 | -0.46 | 3.51 | 0.7 | 2.457 | 0.54054
675069 | RDC | Niveau: RDC | Niveau: R+1 | 0.3 | -0.46 | 3.51 | 0.7 | 2.457 | 0.54054
675084 | RDC | Niveau: RDC | Niveau: R+1 | 0.3 | -0.46 | 3.51 | 0.7 | 2.457 | 0.54054 | Données d'identification - Variantes: Modèle de base
675087 | RDC | Niveau: RDC | Niveau: R+1 | 0.3 | -0.46 | 3.51 | 0.7 | 2.457 | 0.54054 | Données d'identification - Variantes: Modèle de base
675090 | RDC | Niveau: RDC | Niveau: R+1 | 0.3 | -0.46 | 3.51 | 0.7 | 2.457 | 0.54054 | Données d'identification - Variantes: Modèle de base
675093 | RDC | Niveau: RDC | Niveau: R+1 | 0.3 | -0.46 | 3.51 | 0.7 | 2.457 | 0.54054
691483 | R+1 | Niveau: R+1 | Niveau: R+2 | 0.1 | -0.51 | 2.95 | 3.29158 | 9.71017 | 2.13624
691497 | R+2 | Niveau: R+2 | Niveau: Toiture | 0.1 | -0.32 | 2.8 | 3.29158 | 6.35643 | 1.39841
692200 | RDC | Niveau: RDC | Niveau: R+1 | 0.2 | -0.46 | 3.61 | 1.43 | 4.8013 | 1.05508
692252 | R+1 | Niveau: R+1 | Niveau: R+2 | 0.1 | -0.5 | 2.96 | 1.54 | 4.2624 | 0.935834 | Données d'identification - Variantes: Modèle de base
939297 | RDC | Niveau: RDC | Niveau: R+1 | 0.3 | -0.46 | 3.51 | 0.7 | 2.457 | 0.54054
939374 | RDC | Niveau: RDC | Niveau: R+1 | 0.3 | -0.46 | 3.51 | 0.7 | 2.457 | 0.54054 | Données d'identification - Variantes: Modèle de base
939380 | RDC | Niveau: RDC | Niveau: R+1 | 0.3 | -0.46 | 3.51 | 0.7 | 2.457 | 0.54054 | Données d'identification - Variantes: Modèle de base
939383 | RDC | Niveau: RDC | Niveau: R+1 | 0.3 | -0.46 | 3.51 | 0.7 | 2.457 | 0.54054 | Données d'identification - Variantes: Modèle de base
939386 | RDC | Niveau: RDC | Niveau: R+1 | 0.3 | -0.46 | 3.51 | 0.7 | 2.457 | 0.54054 | Données d'identification - Variantes: Modèle de base
939389 | RDC | Niveau: RDC | Niveau: R+1 | 0.3 | -0.46 | 3.51 | 0.7 | 2.457 | 0.54054 | Données d'identification - Variantes: Modèle de base
939392 | RDC | Niveau: RDC | Niveau: R+1 | 0.3 | -0.46 | 3.51 | 0.7 | 2.457 | 0.54054
939395 | RDC | Niveau: RDC | Niveau: R+1 | 0.3 | -0.46 | 3.51 | 0.7 | 2.457 | 0.54054
939398 | RDC | Niveau: RDC | Niveau: R+1 | 0.3 | -0.46 | 3.51 | 0.7 | 2.457 | 0.54054
939401 | RDC | Niveau: RDC | Niveau: R+1 | 0.3 | -0.46 | 3.51 | 0.7 | 2.457 | 0.54054 | Données d'identification - Variantes: Modèle de base
939404 | RDC | Niveau: RDC | Niveau: R+1 | 0.3 | -0.46 | 3.51 | 0.7 | 2.457 | 0.54054
939407 | RDC | Niveau: RDC | Niveau: R+1 | 0.3 | -0.46 | 3.51 | 0.7 | 2.457 | 0.54054 | Données d'identification - Variantes: Modèle de base
939410 | RDC | Niveau: RDC | Niveau: R+1 | 0.3 | -0.46 | 3.51 | 0.7 | 2.457 | 0.54054 | Données d'identification - Variantes: Modèle de base
939413 | RDC | Niveau: RDC | Niveau: R+1 | 0.3 | -0.46 | 3.51 | 0.7 | 2.457 | 0.54054 | Données d'identification - Variantes: Modèle de base
939416 | RDC | Niveau: RDC | Niveau: R+1 | 0.3 | -0.46 | 3.51 | 0.7 | 2.457 | 0.54054
939419 | RDC | Niveau: RDC | Niveau: R+1 | 0.3 | -0.46 | 3.51 | 0.7 | 2.457 | 0.54054 | Données d'identification - Variantes: Modèle de base
939422 | RDC | Niveau: RDC | Niveau: R+1 | 0.3 | -0.46 | 3.51 | 0.7 | 2.457 | 0.54054 | Données d'identification - Variantes: Modèle de base
939425 | RDC | Niveau: RDC | Niveau: R+1 | 0.3 | -0.46 | 3.51 | 0.7 | 2.457 | 0.54054 | Données d'identification - Variantes: Modèle de base
939428 | RDC | Niveau: RDC | Niveau: R+1 | 0.3 | -0.46 | 3.51 | 0.7 | 2.457 | 0.54054
989660 | R+1 | Niveau: R+1 | Niveau: R+2 | 0.1 | -0.46 | 3 | 0.7 | 2.1 | 0.462
989663 | R+1 | Niveau: R+1 | Niveau: R+2 | 0.1 | -0.46 | 3 | 0.7 | 2.1 | 0.462
989676 | R+1 | Niveau: R+1 | Niveau: R+2 | 0.1 | -0.46 | 3 | 0.7 | 2.1 | 0.462 | Données d'identification - Variantes: Modèle de base
989679 | R+1 | Niveau: R+1 | Niveau: R+2 | 0.1 | -0.46 | 3 | 0.7 | 2.1 | 0.462
989684 | R+1 | Niveau: R+1 | Niveau: R+2 | 0.1 | -0.46 | 3 | 0.7 | 2.1 | 0.462
989687 | R+1 | Niveau: R+1 | Niveau: R+2 | 0.1 | -0.46 | 3 | 0.7 | 2.1 | 0.462 | Données d'identification - Variantes: Modèle de base
989692 | R+1 | Niveau: R+1 | Niveau: R+2 | 0.1 | -0.46 | 3 | 0.7 | 2.1 | 0.462 | Données d'identification - Variantes: Modèle de base
989695 | R+1 | Niveau: R+1 | Niveau: R+2 | 0.1 | -0.46 | 3 | 0.7 | 2.1 | 0.462 | Données d'identification - Variantes: Modèle de base
989708 | R+1 | Niveau: R+1 | Niveau: R+2 | 0.1 | -0.46 | 3 | 0.7 | 2.1 | 0.462 | Données d'identification - Variantes: Modèle de base
989711 | R+1 | Niveau: R+1 | Niveau: R+2 | 0.1 | -0.46 | 3 | 0.7 | 2.1 | 0.462 | Données d'identification - Variantes: Modèle de base
989724 | R+1 | Niveau: R+1 | Niveau: R+2 | 0.1 | -0.46 | 3 | 0.7 | 2.1 | 0.462
989727 | R+1 | Niveau: R+1 | Niveau: R+2 | 0.1 | -0.46 | 3 | 0.7 | 2.1 | 0.462
989732 | R+1 | Niveau: R+1 | Niveau: R+2 | 0.1 | -0.46 | 3 | 0.7 | 2.1 | 0.462
989735 | R+1 | Niveau: R+1 | Niveau: R+2 | 0.1 | -0.46 | 3 | 0.7 | 2.1 | 0.462
989740 | R+1 | Niveau: R+1 | Niveau: R+2 | 0.1 | -0.46 | 3 | 0.7 | 2.1 | 0.462
989743 | R+1 | Niveau: R+1 | Niveau: R+2 | 0.1 | -0.46 | 3 | 0.7 | 2.1 | 0.462
989772 | R+1 | Niveau: R+1 | Niveau: R+2 | 0.1 | -0.46 | 3 | 0.7 | 2.1 | 0.462
989775 | R+1 | Niveau: R+1 | Niveau: R+2 | 0.1 | -0.46 | 3 | 0.7 | 2.1 | 0.462
1062627 | R+1 | Niveau: R+1 | Niveau: R+2 | 0.1 | -0.46 | 3 | 0.7 | 2.1 | 0.462 | Données d'identification - Variantes: Modèle de base
1062630 | R+1 | Niveau: R+1 | Niveau: R+2 | 0.1 | -0.46 | 3 | 0.7 | 2.1 | 0.462
1062666 | R+1 | Niveau: R+1 | Niveau: R+2 | 0.1 | -0.46 | 3 | 0.7 | 2.1 | 0.462 | Données d'identification - Variantes: Modèle de base
1062669 | R+1 | Niveau: R+1 | Niveau: R+2 | 0.1 | -0.46 | 3 | 0.7 | 2.1 | 0.462
1062707 | R+1 | Niveau: R+1 | Niveau: R+2 | 0.1 | -0.46 | 3 | 0.7 | 2.1 | 0.462
1062710 | R+1 | Niveau: R+1 | Niveau: R+2 | 0.1 | -0.46 | 3 | 0.7 | 2.1 | 0.462
1062749 | R+1 | Niveau: R+1 | Niveau: R+2 | 0.1 | -0.46 | 3 | 0.7 | 2.1 | 0.462
1062752 | R+1 | Niveau: R+1 | Niveau: R+2 | 0.1 | -0.46 | 3 | 0.7 | 2.1 | 0.462 | Données d'identification - Variantes: Modèle de base
1062758 | R+1 | Niveau: R+1 | Niveau: R+2 | 0.1 | -0.46 | 3 | 0.7 | 2.1 | 0.462
1062761 | R+1 | Niveau: R+1 | Niveau: R+2 | 0.1 | -0.46 | 3 | 0.7 | 2.1 | 0.462
1062767 | R+1 | Niveau: R+1 | Niveau: R+2 | 0.1 | -0.46 | 3 | 0.7 | 2.1 | 0.462
1062770 | R+1 | Niveau: R+1 | Niveau: R+2 | 0.1 | -0.46 | 3 | 0.7 | 2.1 | 0.462 | Données d'identification - Variantes: Modèle de base
1062776 | R+1 | Niveau: R+1 | Niveau: R+2 | 0.1 | -0.46 | 3 | 0.7 | 2.1 | 0.462 | Données d'identification - Variantes: Modèle de base
1062779 | R+1 | Niveau: R+1 | Niveau: R+2 | 0.1 | -0.46 | 3 | 0.7 | 2.1 | 0.462 | Données d'identification - Variantes: Modèle de base
1063009 | R+1 | Niveau: R+1 | Niveau: R+2 | 0.1 | -0.46 | 3 | 0.7 | 2.1 | 0.462
1063012 | R+1 | Niveau: R+1 | Niveau: R+2 | 0.1 | -0.46 | 3 | 0.7 | 2.1 | 0.462
1063018 | R+1 | Niveau: R+1 | Niveau: R+2 | 0.1 | -0.46 | 3 | 0.7 | 2.1 | 0.462
1063021 | R+1 | Niveau: R+1 | Niveau: R+2 | 0.1 | -0.46 | 3 | 0.7 | 2.1 | 0.462
1063696 | R+2 | Niveau: R+2 | Niveau: Toiture | 0.1 | -0.28 | 2.84 | 0.7 | 1.988 | 0.43736 | Group: Groupe de modèles:mur BTC R+2:2029197
1063699 | R+2 | Niveau: R+2 | Niveau: Toiture | 0.1 | -0.28 | 2.84 | 0.7 | 1.988 | 0.43736 | Group: Groupe de modèles:mur BTC R+2:2029197
1063849 | R+2 | Niveau: R+2 | Niveau: Toiture | 0.1 | -0.32 | 2.8 | 1.43 | 3.724 | 0.818346
1081938 | RDC | Niveau: RDC | Niveau: R+1 | 0.3 | -0.46 | 3.51 | 0.711582 | 2.49765 | 0.549483
1081940 | RDC | Niveau: RDC | Niveau: R+1 | 0.3 | -0.46 | 3.51 | 0.711582 | 2.49765 | 0.549483
1082548 | R+1 | Niveau: R+1 | Niveau: R+2 | 0 | -0.46 | 3.1 | 0.711582 | 2.2059 | 0.485299
1082549 | R+1 | Niveau: R+1 | Niveau: R+2 | 0 | -0.46 | 3.1 | 0.711582 | 2.2059 | 0.485299
1163333 | RDC | Niveau: RDC | Niveau: R+1 | 0.3 | -0.51 | 3.46 | 3.29158 | 11.3889 | 2.50555 | Données d'identification - Variantes: Modèle de base
1163553 | R+1 | Niveau: R+1 | Niveau: R+2 | 0.1 | -0.51 | 2.95 | 2.66158 | 4.90596 | 1.07931 | Données d'identification - Variantes: Modèle de base
1163709 | R+2 | Niveau: R+2 | Niveau: Toiture | 0.1 | -0.32 | 2.8 | 2.66158 | 4.65672 | 1.02448
1164014 | R+1 | Niveau: R+1 | Niveau: R+2 | -3.97 | -0.46 | 7.07 | 3.26158 | 23.0594 | 5.07306
1401075 | R+1 | Niveau: R+1 |  | -3.97 | 0 | 3.46 | 2.69158 | 9.31287 | 2.04883 | Données d'identification - Variantes: Modèle de base
1540225 | R+1 | Niveau: R+1 | Niveau: R+2 | -0.09 | -0.46 | 3.19 | 2.69158 | 8.58614 | 1.88895 | Données d'identification - Variantes: Modèle de base
2029527 | R+2 | Niveau: R+2 | Niveau: Toiture | 0.1 | -0.28 | 2.84 | 0.7 | 1.988 | 0.43736 | Données d'identification - Variantes: Modèle de base
2029528 | R+2 | Niveau: R+2 | Niveau: Toiture | 0.1 | -0.28 | 2.84 | 0.7 | 1.988 | 0.43736 | Données d'identification - Variantes: Modèle de base
2029579 | R+2 | Niveau: R+2 | Niveau: Toiture | 0.1 | -0.28 | 2.84 | 0.7 | 1.988 | 0.43736
2029580 | R+2 | Niveau: R+2 | Niveau: Toiture | 0.1 | -0.28 | 2.84 | 0.7 | 1.988 | 0.43736
2029642 | R+2 | Niveau: R+2 | Niveau: Toiture | 0.1 | -0.28 | 2.84 | 0.7 | 1.988 | 0.43736 | Données d'identification - Variantes: Modèle de base; Group: Groupe de modèles:mur BTC R+2:2029648
2029643 | R+2 | Niveau: R+2 | Niveau: Toiture | 0.1 | -0.28 | 2.84 | 0.7 | 1.988 | 0.43736 | Données d'identification - Variantes: Modèle de base; Group: Groupe de modèles:mur BTC R+2:2029648
2029653 | R+2 | Niveau: R+2 | Niveau: Toiture | 0.1 | -0.28 | 2.84 | 0.7 | 1.988 | 0.43736
2029654 | R+2 | Niveau: R+2 | Niveau: Toiture | 0.1 | -0.28 | 2.84 | 0.7 | 1.988 | 0.43736
2029716 | R+2 | Niveau: R+2 | Niveau: Toiture | 0.1 | -0.28 | 2.84 | 0.7 | 1.988 | 0.43736 | Données d'identification - Variantes: Modèle de base; Group: Groupe de modèles:mur BTC R+2:2029722
2029717 | R+2 | Niveau: R+2 | Niveau: Toiture | 0.1 | -0.28 | 2.84 | 0.76 | 2.1584 | 0.474848 | Données d'identification - Variantes: Modèle de base; Group: Groupe de modèles:mur BTC R+2:2029722
2029727 | R+2 | Niveau: R+2 | Niveau: Toiture | 0.1 | -0.28 | 2.84 | 0.7 | 1.988 | 0.43736 | Données d'identification - Variantes: Modèle de base
2029728 | R+2 | Niveau: R+2 | Niveau: Toiture | 0.1 | -0.28 | 2.84 | 0.76 | 2.2578 | 0.496716 | Données d'identification - Variantes: Modèle de base
2029794 | R+2 | Niveau: R+2 | Niveau: Toiture | 0.1 | -0.28 | 2.84 | 0.7 | 1.988 | 0.43736 | Group: Groupe de modèles:mur BTC R+2:2029800
2029795 | R+2 | Niveau: R+2 | Niveau: Toiture | 0.1 | -0.28 | 2.84 | 0.76 | 2.1584 | 0.474848 | Données d'identification - Variantes: Modèle de base; Group: Groupe de modèles:mur BTC R+2:2029800
2029805 | R+2 | Niveau: R+2 | Niveau: Toiture | 0.1 | -0.28 | 2.84 | 0.7 | 1.988 | 0.43736 | Données d'identification - Variantes: Modèle de base
2029806 | R+2 | Niveau: R+2 | Niveau: Toiture | 0.1 | -0.28 | 2.84 | 0.7 | 1.988 | 0.43736

# IfcWallStandardCase: Mur de base:Générique - Int. 70 mm (43)
Type - PredefinedType: STANDARD; Material: AA-fermacell peint 0.0125 m, AA-isolant plancher 0.045 m, AA-fermacell peint 0.0125 m
Type - Autre - Catégorie: Murs; Nom de la famille: Mur de base
Type - Construction - Fonction: Intérieur; Retournement aux extrémités: Aucun(e); Retournement aux insertions: Ne pas retourner; Largeur: 0.07 m
Type - Données d'identification - Sous-projet: Types de murs; Nom du type: Générique - Int. 70 mm
Type - Graphismes - Couleur vue détail faible: 0
Type - Propriétés analytiques - Rugosité: 3; Coefficient d'absorbance: 0.7
Autre - Famille: Mur de base: Générique - Int. 70 mm; Famille et type: Mur de base: Générique - Int. 70 mm; ID du type: Mur de base: Générique - Int. 70 mm; Type: Mur de base: Générique - Int. 70 mm
Contraintes - Lié au volume: no; Extension inférieure: 0 m; Extension supérieure: 0 m; Partie inférieure attachée: no
Données d'identification - Sous-projet: Cloisons
Phase de construction - Phase de création: Nouvelle construction
Structure - Activer le modèle analytique: no; Structure: no; Utilisation structurelle: Non porteur
Pset_WallCommon - IsExternal: no; LoadBearing: no; Reference: Mur de base:Générique - Int. 70 mm
Name (Mur de base:Générique - Int. 70 mm:...) | In | Limite de pièce | Ligne de justification | Partie supérieure attachée = ExtendToStructure | Contrainte inférieure | Contrainte supérieure | Décalage inférieur (m) | Décalage supérieur (m) | Hauteur non contrainte (m) | Longueur (m) | Surface (m2) | Volume (m3) | Variantes
549560 | R-1 | yes | Axe du mur | no | Niveau: R-1 | Niveau: RDC | 0.43 | -0.275 | 3.915 | 5.51258 | 19.2947 | 1.35063 | Modèle de base
549968 | R-1 | yes | Axe du mur | yes | Niveau: R-1 | Niveau: RDC | 0.43 | -0.28 | 3.91 | 8.27416 | 29.8518 | 2.08963
550287 | R-1 | yes | Axe du mur | yes | Niveau: R-1 | Niveau: RDC | 0.43 | -0.28 | 3.91 | 8 | 30.2629 | 2.11841
996157 | R-1 | yes | Axe du mur | no | Niveau: R-1 | Niveau: RDC | 0.43 | -0.275 | 3.915 | 3.298 | 12.3831 | 0.86682
1000776 | R-1 | yes | Axe du mur | no | Niveau: R-1 | Niveau: RDC | 0.43 | -0.275 | 3.915 | 4.972 | 19.2109 | 1.34476
1040859 | R+1 | yes | Axe du mur | no | Niveau: R+1 | Niveau: R+2 | 0 | -0.46 | 3.1 | 0.79 | 1.9282 | 0.134974 | Modèle de base
1231478 | R-1 | no | Axe du mur | no | Niveau: R-1 | Niveau: RDC | -0.01 | -0.275 | 4.355 | 2.08 | 9.0298 | 0.632086 | Modèle de base
1231479 | R-1 | no | Axe du mur | no | Niveau: R-1 | Niveau: RDC | -0.01 | -1.21 | 3.42 | 1.82658 | 3.89863 | 0.272904
1239446 | RDC | yes | Axe du mur | no | Niveau: RDC | Niveau: R+1 | 0 | -0.27 | 4 | 0.64 | 2.328 | 0.16296
1642791 | R+1 | no | Axe du mur | no | Niveau: R+1 |  | 0 | 0 | 3.3 | 2.081 | 6.57855 | 0.460498 | Modèle de base
1643341 | R+2 | no | Axe du mur | no | Niveau: R+2 | Niveau: Toiture | 0 | -0.18 | 3.04 | 2.081 | 6.06024 | 0.424217 | Modèle de base
1643342 | R+2 | no | Axe du mur | no | Niveau: R+2 | Niveau: Toiture | 0 | -0.82 | 2.4 | 2.69533 | 2.5928 | 0.181496
1643991 | R-1 | no | Axe du mur | no | Niveau: R-1 | Niveau: RDC | -0.01 | -1.37 | 3.26 | 0.935 | 0.948 | 0.06636 | Modèle de base
2171202 | R+1 | no | Axe du mur | no | Niveau: R+1 |  | 0 | 0 | 2.66 | 2.69533 | 3.27831 | 0.229481
2247721 | RDC | no | Axe du mur | no | Niveau: RDC | Niveau: R+1 | 0 | -0.26 | 4.01 | 4.22 | 10.8756 | 0.76129
2247723 | RDC | yes | Axe du mur | no | Niveau: RDC | Niveau: R+1 | 0 | -0.9 | 3.37 | 1.852 | 5.94637 | 0.416246
2247724 | RDC | no | Axe du mur | no | Niveau: RDC | Niveau: R+1 | 0 | -0.9 | 3.37 | 1.852 | 5.94637 | 0.416246 | Modèle de base
2260734 | R+1 | yes | Nu fini: Extérieur | no | Niveau: R+1 | Niveau: R+2 | 0 | -0.175 | 3.385 | 4 | 13.1473 | 0.920314 | Modèle de base
2261318 | R+1 | yes | Nu fini: Extérieur | no | Niveau: R+1 | Niveau: R+2 | 0 | -0.175 | 3.385 | 4 | 13.1473 | 0.920314 | Modèle de base
2270091 | R+1 | yes | Nu fini: Extérieur | no | Niveau: R+1 | Niveau: R+2 | 0 | -0.4 | 3.16 | 3.43 | 10.4722 | 0.733057 | Modèle de base
2445934 | R-1 | yes | Axe du mur | yes | Niveau: R-1 | Niveau: RDC | 0.43 | -0.275 | 3.915 | 2.76158 | 10.2831 | 0.719815
2447855 | R-1 | yes | Axe du mur | no | Niveau: R-1 | Niveau: RDC | 0.43 | -0.275 | 3.915 | 2.202 | 8.62083 | 0.603458
2448015 | R-1 | yes | Axe du mur | no | Niveau: R-1 | Niveau: RDC | 0.43 | -0.275 | 3.915 | 0.702 | 2.47428 | 0.1732 | Modèle de base
2521078 | R+2 | yes | Axe du mur | no | Niveau: R+2 | Niveau: Toiture | 0 | -0.17 | 3.05 | 3.03 | 7.09635 | 0.496744
2521087 | R+2 | yes | Axe du mur | no | Niveau: R+2 | Niveau: Toiture | 0 | -0.17 | 3.05 | 2.08906 | 5.92937 | 0.415056
2564344 | R+2 | yes | Axe du mur | no | Niveau: R+2 | Niveau: Toiture | 0 | -0.17 | 3.05 | 0.365 | 0.8845 | 0.061915 | Modèle de base
2564413 | R+2 | yes | Axe du mur | no | Niveau: R+2 | Niveau: Toiture | 0 | -0.17 | 3.05 | 0.533269 | 1.51972 | 0.106381 | Modèle de base
2564585 | R+1 | yes | Axe du mur | no | Niveau: R+1 | Niveau: R+2 | 0 | -0.51 | 3.05 | 0.365 | 0.8845 | 0.061915 | Modèle de base
2564586 | R+1 | yes | Axe du mur | no | Niveau: R+1 | Niveau: R+2 | 0 | -0.51 | 3.05 | 0.533317 | 1.51987 | 0.106391
2589947 | R+2 | yes | Axe du mur | no | Niveau: R+2 | Niveau: Toiture | 0 | -0.82 | 2.4 | 3.582 | 8.5968 | 0.601776
2590577 | R+2 | yes | Axe du mur | no | Niveau: R+2 | Niveau: Toiture | 0 | -0.82 | 2.4 | 0.435 | 1.128 | 0.07896 | Modèle de base
2590863 | R+2 | yes | Axe du mur | no | Niveau: R+2 | Niveau: Toiture | 0 | -0.82 | 2.4 | 0.435 | 0.96 | 0.0672 | Modèle de base
2607213 | RDC | yes | Axe du mur | no | Niveau: RDC | Niveau: R+1 | 0 | -0.26 | 4.01 | 0.365 | 1.1629 | 0.081403 | Modèle de base
2607214 | RDC | yes | Axe du mur | no | Niveau: RDC | Niveau: R+1 | 0 | -0.26 | 4.01 | 0.49 | 1.9649 | 0.137543 | Modèle de base
2607262 | RDC | yes | Axe du mur | no | Niveau: RDC | Niveau: R+1 | 0 | -0.51 | 3.76 | 0.215 | 0.6768 | 0.047376 | Modèle de base
2607339 | R-1 | yes | Axe du mur | no | Niveau: R-1 | Niveau: RDC | 0 | -1.57 | 3.05 | 0.365 | 0.915 | 0.06405
2607340 | R-1 | yes | Axe du mur | no | Niveau: R-1 | Niveau: RDC | 0 | -1.57 | 3.05 | 0.59 | 1.55805 | 0.109063 | Modèle de base
2923832 | RDC | yes | Axe du mur | no | Niveau: RDC | Niveau: R+1 | 0 | -1.22 | 3.05 | 0.195 | 0.7015 | 0.049105 | Modèle de base
2923833 | RDC | yes | Axe du mur | no | Niveau: RDC | Niveau: R+1 | 0 | -1.22 | 3.05 | 0.37 | 1.1285 | 0.0789949 | Modèle de base
2923834 | RDC | yes | Axe du mur | no | Niveau: RDC | Niveau: R+1 | 0 | -1.22 | 3.05 | 0.195 | 0.488 | 0.03416
2924508 | R+1 | yes | Axe du mur | no | Niveau: R+1 | Niveau: R+2 | 0 | -0.51 | 3.05 | 0.275 | 0.9455 | 0.066185 | Modèle de base
2924509 | R+1 | yes | Axe du mur | no | Niveau: R+1 | Niveau: R+2 | 0 | -0.51 | 3.05 | 0.368317 | 1.12337 | 0.0786356
2924601 | R+1 | yes | Axe du mur | no | Niveau: R+1 | Niveau: R+2 | 0 | -0.51 | 3.05 | 0.275 | 0.732 | 0.05124

# IfcWallStandardCase: Mur de base:bambou tressé (3)
Type - PredefinedType: STANDARD; Material: AA-bambou 0.02 m
Type - Autre - Catégorie: Murs; Nom de la famille: Mur de base
Type - Construction - Fonction: Intérieur; Retournement aux extrémités: Aucun(e); Retournement aux insertions: Ne pas retourner; Largeur: 0.02 m
Type - Données d'identification - Sous-projet: Types de murs; Nom du type: bambou tressé
Type - Graphismes - Couleur vue détail faible: 0
Type - Propriétés analytiques - Rugosité: 3; Coefficient d'absorbance: 0.7
Autre - Famille: Mur de base: bambou tressé; Famille et type: Mur de base: bambou tressé; ID du type: Mur de base: bambou tressé; Type: Mur de base: bambou tressé
Contraintes - Lié au volume: no; Limite de pièce: yes; Extension inférieure: 0 m; Extension supérieure: 0 m; Partie inférieure attachée: no; Partie supérieure attachée: no; Décalage supérieur: 0 m; Ligne de justification: Nu fini: Extérieur; Décalage inférieur: 2.29966 m
Cotes - Longueur: 1.84 m
Données d'identification - Sous-projet: Cloisons
Phase de construction - Phase de création: Nouvelle construction
Structure - Activer le modèle analytique: no; Structure: no; Utilisation structurelle: Non porteur
Pset_WallCommon - IsExternal: no; LoadBearing: no; ExtendToStructure: no; Reference: Mur de base:bambou tressé
Name (Mur de base:bambou tressé:...) | In | Contrainte inférieure | Hauteur non contrainte (m) | Surface (m2) | Volume (m3) | Variantes
1403055 | R+1 | Niveau: R+1 | 0.75034 | 1.3281 | 0.026562 | Modèle de base
1403374 | RDC | Niveau: RDC | 1.42034 | 2.514 | 0.05028
1403424 | R+2 | Niveau: R+2 | 0.60034 | 1.0626 | 0.021252 | Modèle de base
